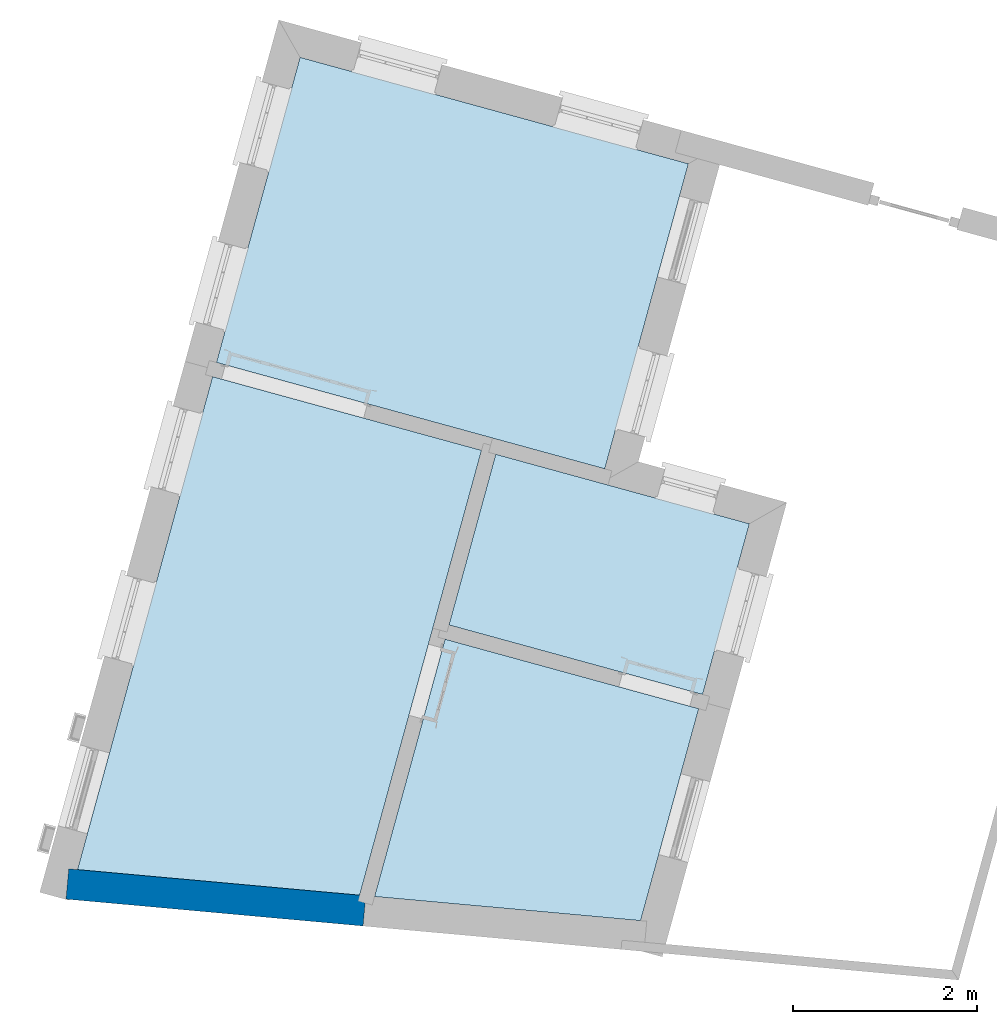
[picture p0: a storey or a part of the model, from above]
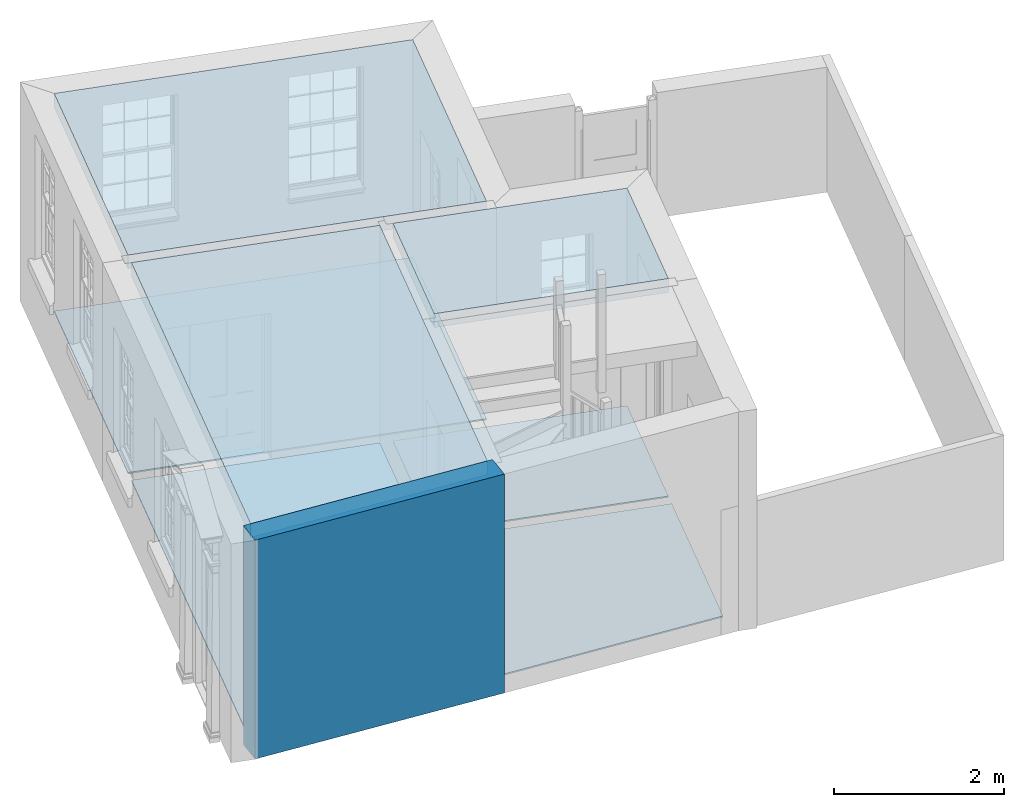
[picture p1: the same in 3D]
Properties of the parts of a building model (IFC4), part 1 of 4

# File
Description: ViewDefinition[DesignTransferView]
File name: model.ifc
Time: 2024-10-11T11:25:13+01:00
Author: bruno
Written by: IfcOpenShell 0.0.0
Made in: Bonsai 0.0.0

# IfcProject, Molior Project
Document: Building plot-0; plot-0 0; plot-0 1; plot-0 2; Building plot-0 NORTH; Building plot-0 SOUTH; Building plot-0 WEST; Building plot-0 EAST; Building plot-0 LOCATION; Building plot-1; plot-1 0; plot-1 1; plot-1 2; Building plot-1 NORTH; Building plot-1 SOUTH; Building plot-1 WEST; Building plot-1 EAST; Building plot-1 LOCATION; Building plot-2; plot-2 0; plot-2 1; plot-2 2; Building plot-2 NORTH; Building plot-2 SOUTH; Building plot-2 WEST; Building plot-2 EAST; Building plot-2 LOCATION; Building plot-3; plot-3 0; plot-3 1; plot-3 2; Building plot-3 NORTH; Building plot-3 SOUTH; Building plot-3 WEST; Building plot-3 EAST; Building plot-3 LOCATION; Building plot-4; plot-4 0; plot-4 1; plot-4 2; Building plot-4 NORTH; Building plot-4 SOUTH; Building plot-4 WEST; Building plot-4 EAST; Building plot-4 LOCATION; Building plot-5; plot-5 0; plot-5 1; plot-5 2; Building plot-5 NORTH; Building plot-5 SOUTH; Building plot-5 WEST; Building plot-5 EAST; Building plot-5 LOCATION; Building plot-6; plot-6 0; plot-6 1; plot-6 2; Building plot-6 NORTH; Building plot-6 SOUTH; Building plot-6 WEST; Building plot-6 EAST; Building plot-6 LOCATION; Building plot-7; plot-7 0; plot-7 1; plot-7 2; Building plot-7 NORTH; Building plot-7 SOUTH; Building plot-7 WEST; Building plot-7 EAST; Building plot-7 LOCATION; Building plot-8; plot-8 0; plot-8 1; plot-8 2; Building plot-8 NORTH; Building plot-8 SOUTH; Building plot-8 WEST; Building plot-8 EAST; Building plot-8 LOCATION; Building plot-9; plot-9 0; plot-9 1; Building plot-9 NORTH; Building plot-9 SOUTH; Building plot-9 WEST; Building plot-9 EAST; Building plot-9 LOCATION; Building plot-10; plot-10 0; plot-10 1; plot-10 2; plot-10 3; Building plot-10 NORTH; Building plot-10 SOUTH; Building plot-10 WEST; Building plot-10 EAST; Building plot-10 LOCATION; Building plot-11; plot-11 0; plot-11 1; plot-11 2; Building plot-11 NORTH; Building plot-11 SOUTH; Building plot-11 WEST; Building plot-11 EAST; Building plot-11 LOCATION; Building plot-12; plot-12 0; plot-12 1; plot-12 2; Building plot-12 NORTH; Building plot-12 SOUTH; Building plot-12 WEST; Building plot-12 EAST; Building plot-12 LOCATION; Building plot-13; plot-13 0; plot-13 1; plot-13 2; Building plot-13 NORTH; Building plot-13 SOUTH; Building plot-13 WEST; Building plot-13 EAST; Building plot-13 LOCATION; Building plot-14; plot-14 0; plot-14 1; plot-14 2; plot-14 3; Building plot-14 NORTH; Building plot-14 SOUTH; Building plot-14 WEST; Building plot-14 EAST; Building plot-14 LOCATION; Building plot-15; plot-15 0; plot-15 1; plot-15 2; Building plot-15 NORTH; Building plot-15 SOUTH; Building plot-15 WEST; Building plot-15 EAST; Building plot-15 LOCATION; Building plot-16; plot-16 0; plot-16 1; plot-16 2; plot-16 3; Building plot-16 NORTH; Building plot-16 SOUTH; Building plot-16 WEST; Building plot-16 EAST; Building plot-16 LOCATION; Building plot-17; plot-17 0; plot-17 1; plot-17 2; Building plot-17 NORTH; Building plot-17 SOUTH; Building plot-17 WEST; Building plot-17 EAST; Building plot-17 LOCATION; Building plot-18; plot-18 0; plot-18 1; plot-18 2; plot-18 3; Building plot-18 NORTH; Building plot-18 SOUTH; Building plot-18 WEST; Building plot-18 EAST; Building plot-18 LOCATION; Building plot-19; plot-19 0; plot-19 1; Building plot-19 NORTH; Building plot-19 SOUTH; Building plot-19 WEST; Building plot-19 EAST; Building plot-19 LOCATION; Building plot-20; plot-20 0; plot-20 1; plot-20 2; Building plot-20 NORTH; Building plot-20 SOUTH; Building plot-20 WEST; Building plot-20 EAST; Building plot-20 LOCATION; Building plot-21; plot-21 0; plot-21 1; plot-21 2; Building plot-21 NORTH; Building plot-21 SOUTH; Building plot-21 WEST; Building plot-21 EAST; Building plot-21 LOCATION; Building plot-22; plot-22 0; plot-22 1; plot-22 2; Building plot-22 NORTH; Building plot-22 SOUTH; Building plot-22 WEST; Building plot-22 EAST; Building plot-22 LOCATION; Building plot-23; plot-23 0; plot-23 1; plot-23 2; Building plot-23 NORTH; Building plot-23 SOUTH; Building plot-23 WEST; Building plot-23 EAST; Building plot-23 LOCATION; Building plot-24; plot-24 0; plot-24 1; plot-24 2; Building plot-24 NORTH; Building plot-24 SOUTH; Building plot-24 WEST; Building plot-24 EAST; Building plot-24 LOCATION; Building plot-25; plot-25 0; plot-25 1; Building plot-25 NORTH; Building plot-25 SOUTH; Building plot-25 WEST; Building plot-25 EAST; Building plot-25 LOCATION; Building plot-26; plot-26 0; plot-26 1; plot-26 2; Building plot-26 NORTH; Building plot-26 SOUTH; Building plot-26 WEST; Building plot-26 EAST; Building plot-26 LOCATION; Building plot-27; plot-27 0; plot-27 1; plot-27 2; Building plot-27 NORTH; Building plot-27 SOUTH; Building plot-27 WEST; Building plot-27 EAST; Building plot-27 LOCATION; Building plot-28; plot-28 0; plot-28 1; plot-28 2; Building plot-28 NORTH; Building plot-28 SOUTH; Building plot-28 WEST; Building plot-28 EAST; Building plot-28 LOCATION; Building plot-29; plot-29 0; plot-29 1; plot-29 2; Building plot-29 NORTH; Building plot-29 SOUTH; Building plot-29 WEST; Building plot-29 EAST; Building plot-29 LOCATION; Building plot-30; plot-30 0; plot-30 1; plot-30 2; Building plot-30 NORTH; Building plot-30 SOUTH; Building plot-30 WEST; Building plot-30 EAST; Building plot-30 LOCATION; Building plot-31; plot-31 0; plot-31 1; plot-31 2; Building plot-31 NORTH; Building plot-31 SOUTH; Building plot-31 WEST; Building plot-31 EAST; Building plot-31 LOCATION

# IfcSite (33)
Name
Site plot-0
Site plot-1
Site plot-10
Site plot-11
Site plot-12
Site plot-13
Site plot-14
Site plot-15
Site plot-16
Site plot-17
Site plot-18
Site plot-19
Site plot-2
Site plot-20
Site plot-21
Site plot-22
Site plot-23
Site plot-24
Site plot-25
Site plot-26
Site plot-27
Site plot-28
Site plot-29
Site plot-3
Site plot-30
Site plot-31
Site plot-4
Site plot-5
Site plot-6
Site plot-7
Site plot-8
Site plot-9
Tamar | RefLatitude: 50, 417; RefLongitude: -4, 25

# IfcBuildingStorey (97)
Name | In | Elevation (m)
plot-0 0 | Building plot-0 | 26
plot-0 1 | Building plot-0 | 29.3
plot-0 2 | Building plot-0 | 32.3
plot-1 0 | Building plot-1 | 26
plot-1 1 | Building plot-1 | 29.6
plot-1 2 | Building plot-1 | 33.2
plot-10 0 | Building plot-10 | 26.8
plot-10 1 | Building plot-10 | 30.1
plot-10 2 | Building plot-10 | 32.8
plot-10 3 | Building plot-10 | 35.5
plot-11 0 | Building plot-11 | 26.8
plot-11 1 | Building plot-11 | 30.1
plot-11 2 | Building plot-11 | 33.4
plot-12 0 | Building plot-12 | 26
plot-12 1 | Building plot-12 | 29.6
plot-12 2 | Building plot-12 | 32.3
plot-13 0 | Building plot-13 | 26
plot-13 1 | Building plot-13 | 29
plot-13 2 | Building plot-13 | 31.85
plot-14 0 | Building plot-14 | 26.8
plot-14 1 | Building plot-14 | 30.4
plot-14 2 | Building plot-14 | 33.55
plot-14 3 | Building plot-14 | 36.25
plot-15 0 | Building plot-15 | 26.8
plot-15 1 | Building plot-15 | 29.95
plot-15 2 | Building plot-15 | 32.95
plot-16 0 | Building plot-16 | 26
plot-16 1 | Building plot-16 | 29.45
plot-16 2 | Building plot-16 | 32.15
plot-16 3 | Building plot-16 | 34.85
plot-17 0 | Building plot-17 | 26.8
plot-17 1 | Building plot-17 | 30.4
plot-17 2 | Building plot-17 | 34
plot-18 0 | Building plot-18 | 26
plot-18 1 | Building plot-18 | 29.6
plot-18 2 | Building plot-18 | 32.3
plot-18 3 | Building plot-18 | 35.3
plot-19 0 | Building plot-19 | 26.8
plot-19 1 | Building plot-19 | 30.4
plot-2 0 | Building plot-2 | 26
plot-2 1 | Building plot-2 | 28.7
plot-2 2 | Building plot-2 | 31.55
plot-20 0 | Building plot-20 | 26
plot-20 1 | Building plot-20 | 29.15
plot-20 2 | Building plot-20 | 31.85
plot-21 0 | Building plot-21 | 26
plot-21 1 | Building plot-21 | 29.6
plot-21 2 | Building plot-21 | 32.3
plot-22 0 | Building plot-22 | 24.5
plot-22 1 | Building plot-22 | 27.8
plot-22 2 | Building plot-22 | 30.5
plot-23 0 | Building plot-23 | 26
plot-23 1 | Building plot-23 | 29.6
plot-23 2 | Building plot-23 | 33.2
plot-24 0 | Building plot-24 | 26
plot-24 1 | Building plot-24 | 29.3
plot-24 2 | Building plot-24 | 32
plot-25 0 | Building plot-25 | 26
plot-25 1 | Building plot-25 | 29.45
plot-26 0 | Building plot-26 | 26
plot-26 1 | Building plot-26 | 29.15
plot-26 2 | Building plot-26 | 32.75
plot-27 0 | Building plot-27 | 26
plot-27 1 | Building plot-27 | 29.3
plot-27 2 | Building plot-27 | 32
plot-28 0 | Building plot-28 | 24
plot-28 1 | Building plot-28 | 27.15
plot-28 2 | Building plot-28 | 29.85
plot-29 0 | Building plot-29 | 25
plot-29 1 | Building plot-29 | 27.85
plot-29 2 | Building plot-29 | 30.55
plot-3 0 | Building plot-3 | 24.5
plot-3 1 | Building plot-3 | 27.8
plot-3 2 | Building plot-3 | 30.5
plot-30 0 | Building plot-30 | 25
plot-30 1 | Building plot-30 | 28.3
plot-30 2 | Building plot-30 | 31
plot-31 0 | Building plot-31 | 25.5
plot-31 1 | Building plot-31 | 28.65
plot-31 2 | Building plot-31 | 31.35
plot-4 0 | Building plot-4 | 24.5
plot-4 1 | Building plot-4 | 27.8
plot-4 2 | Building plot-4 | 31.4
plot-5 0 | Building plot-5 | 24
plot-5 1 | Building plot-5 | 26.85
plot-5 2 | Building plot-5 | 30.15
plot-6 0 | Building plot-6 | 24.5
plot-6 1 | Building plot-6 | 28.1
plot-6 2 | Building plot-6 | 31.7
plot-7 0 | Building plot-7 | 26
plot-7 1 | Building plot-7 | 29.15
plot-7 2 | Building plot-7 | 31.85
plot-8 0 | Building plot-8 | 26
plot-8 1 | Building plot-8 | 28.85
plot-8 2 | Building plot-8 | 31.55
plot-9 0 | Building plot-9 | 26.8
plot-9 1 | Building plot-9 | 30.1

# IfcSpace (375)
Name | In | LongName | PredefinedType | NetFloorArea (m2) | Height (m) | NetVolume (m3)
Stair | plot-0 0 | Stair 0 lll | INTERNAL | 5.96703 | 3.08 | 18.3784
Circulation | plot-0 0 | Circulation 0 lrll | INTERNAL | 3.54437 | 3.08 | 10.9167
Bedroom | plot-0 0 | Bedroom 0 llr | INTERNAL | 8.87304 | 3.08 | 27.329
Bedroom | plot-0 0 | Bedroom 0 lrr | INTERNAL | 11.3388 | 3.08 | 34.9236
Toilet | plot-0 0 | Toilet 0 lrlr | INTERNAL | 2.95732 | 3.08 | 9.10855
Outside | plot-0 0 | Outside 0 r | EXTERNAL | 21.0555 | 3.08 | 64.8511
Stair | plot-0 1 | Stair 1 lll | INTERNAL | 5.96703 | 2.78 | 16.5883
Living | plot-0 1 | Living 1 lr | INTERNAL | 18.7241 | 2.78 | 52.0531
Kitchen | plot-0 1 | Kitchen 1 llr | INTERNAL | 8.87304 | 2.78 | 24.667
Bedroom | plot-0 2 | Bedroom 2 llr | INTERNAL | 8.87304 | 2.48 | 22.0051
Outside | plot-0 2 | Outside 2 lr | EXTERNAL | 18.7241 | 2.48 | 46.4359
Stair | plot-0 2 | Stair 2 lll | INTERNAL | 5.96703 | 2.48 | 14.7982
Circulation | plot-1 0 | Circulation 0 lrll | INTERNAL | 5.14544 | 3.38 | 17.3916
Bedroom | plot-1 0 | Bedroom 0 lrr | INTERNAL | 15.0023 | 3.38 | 50.7076
Outside | plot-1 0 | Outside 0 lrlr | EXTERNAL | 5.23166 | 3.38 | 17.683
Stair | plot-1 0 | Stair 0 lll | INTERNAL | 7.57512 | 3.38 | 25.6039
Toilet | plot-1 0 | Toilet 0 llr | INTERNAL | 10.7025 | 3.38 | 36.1743
Outside | plot-1 0 | Outside 0 r | EXTERNAL | 22.0098 | 3.38 | 74.3931
Stair | plot-1 1 | Stair 1 lll | INTERNAL | 7.57512 | 3.38 | 25.6039
Kitchen | plot-1 1 | Kitchen 1 llr | INTERNAL | 10.7025 | 3.38 | 36.1743
Living | plot-1 1 | Living 1 lr | INTERNAL | 26.5038 | 3.38 | 89.5828
Stair | plot-1 2 | Stair 2 lll | INTERNAL | 7.57512 | 2.48 | 18.7863
Bedroom | plot-1 2 | Bedroom 2 llr | INTERNAL | 10.7025 | 2.48 | 26.5421
Outside | plot-1 2 | Outside 2 lr | EXTERNAL | 26.5038 | 2.48 | 65.7294
Stair | plot-10 0 | Stair 0 rl | INTERNAL | 5.94535 | 3.08 | 18.3117
Kitchen | plot-10 0 | Kitchen 0 rr | INTERNAL | 8.41021 | 3.08 | 25.9034
Living | plot-10 0 | Living 0 ll | INTERNAL | 17.3902 | 3.08 | 53.5619
Outside | plot-10 0 | Outside 0 lr | EXTERNAL | 15.8102 | 3.08 | 48.6955
Stair | plot-10 1 | Stair 1 rl | INTERNAL | 5.94535 | 2.48 | 14.7445
Toilet | plot-10 1 | Toilet 1 rr | INTERNAL | 8.41021 | 2.48 | 20.8573
Outside | plot-10 1 | Outside 1 ll | EXTERNAL | 17.3902 | 2.48 | 43.1278
Stair | plot-10 2 | Stair 2 rl | INTERNAL | 5.94535 | 2.48 | 14.7445
Bedroom | plot-10 2 | Bedroom 2 rr | INTERNAL | 8.41021 | 2.48 | 20.8573
Stair | plot-10 3 | Stair 3 rl | INTERNAL | 5.94535 | 2.48 | 14.7445
Bedroom | plot-10 3 | Bedroom 3 rr | INTERNAL | 8.41021 | 2.48 | 20.8573
Outside | plot-11 0 | Outside 0 rll | EXTERNAL | 12.8188 | 3.08 | 39.482
Bedroom | plot-11 0 | Bedroom 0 rlr | INTERNAL | 12.1352 | 3.08 | 37.3764
Circulation | plot-11 0 | Circulation 0 lll | INTERNAL | 6.95787 | 3.08 | 21.4302
Toilet | plot-11 0 | Toilet 0 lrl | INTERNAL | 10.7166 | 3.08 | 33.0072
Outside | plot-11 0 | Outside 0 llr | EXTERNAL | 10.2707 | 3.08 | 31.6338
Outside | plot-11 0 | Outside 0 lrr | EXTERNAL | 9.70752 | 3.08 | 29.8992
Stair | plot-11 0 | Stair 0 rr | INTERNAL | 10.1278 | 3.08 | 31.1937
Bedroom | plot-11 1 | Bedroom 1 rlr | INTERNAL | 12.1352 | 3.08 | 37.3764
Living | plot-11 1 | Living 1 ll | INTERNAL | 17.7529 | 3.08 | 54.6789
Kitchen | plot-11 1 | Kitchen 1 lrl | INTERNAL | 10.7166 | 3.08 | 33.0072
Stair | plot-11 1 | Stair 1 rr | INTERNAL | 10.1278 | 3.08 | 31.1937
Stair | plot-11 2 | Stair 2 rr | INTERNAL | 10.1278 | 2.48 | 25.117
Bedroom | plot-11 2 | Bedroom 2 rlr | INTERNAL | 12.1352 | 2.48 | 30.0953
Outside | plot-11 2 | Outside 2 ll | EXTERNAL | 17.7529 | 2.48 | 44.0271
Outside | plot-11 2 | Outside 2 lrl | EXTERNAL | 10.7166 | 2.48 | 26.5772
Stair | plot-12 0 | Stair 0 rll | INTERNAL | 8.0224 | 3.38 | 27.1157
Kitchen | plot-12 0 | Kitchen 0 rlr | INTERNAL | 9.74623 | 3.38 | 32.9423
Outside | plot-12 0 | Outside 0 l | EXTERNAL | 27.2026 | 3.38 | 91.9449
Living | plot-12 0 | Living 0 rr | INTERNAL | 19.1112 | 3.38 | 64.5959
Stair | plot-12 1 | Stair 1 rll | INTERNAL | 8.0224 | 2.48 | 19.8956
Bedroom | plot-12 1 | Bedroom 1 rr | INTERNAL | 19.1112 | 2.48 | 47.3958
Toilet | plot-12 1 | Toilet 1 rlr | INTERNAL | 9.74623 | 2.48 | 24.1706
Stair | plot-12 2 | Stair 2 rll | INTERNAL | 8.0224 | 2.48 | 19.8956
Outside | plot-12 2 | Outside 2 rr | EXTERNAL | 19.1112 | 2.48 | 47.3958
Bedroom | plot-12 2 | Bedroom 2 rlr | INTERNAL | 9.74623 | 2.48 | 24.1706
Outside | plot-13 0 | Outside 0 ll | EXTERNAL | 26.1804 | 2.78 | 72.7814
Stair | plot-13 0 | Stair 0 lrl | INTERNAL | 6.69457 | 2.78 | 18.6109
Kitchen | plot-13 0 | Kitchen 0 lrr | INTERNAL | 8.50893 | 2.78 | 23.6548
Living | plot-13 0 | Living 0 r | INTERNAL | 25.9567 | 2.78 | 72.1597
Bedroom | plot-13 1 | Bedroom 1 rl | INTERNAL | 13.2145 | 2.63 | 34.7543
Outside | plot-13 1 | Outside 1 rr | EXTERNAL | 12.1835 | 2.63 | 32.0427
Stair | plot-13 1 | Stair 1 lrl | INTERNAL | 6.69457 | 2.63 | 17.6067
Toilet | plot-13 1 | Toilet 1 lrr | INTERNAL | 8.50893 | 2.63 | 22.3785
Stair | plot-13 2 | Stair 2 lrl | INTERNAL | 6.69457 | 2.48 | 16.6025
Bedroom | plot-13 2 | Bedroom 2 rl | INTERNAL | 13.2145 | 2.48 | 32.7721
Bedroom | plot-13 2 | Bedroom 2 lrr | INTERNAL | 8.50893 | 2.48 | 21.1022
Living | plot-14 0 | Living 0 rrl | INTERNAL | 10.6065 | 3.38 | 35.8499
Kitchen | plot-14 0 | Kitchen 0 rrr | INTERNAL | 7.65437 | 3.38 | 25.8718
Outside | plot-14 0 | Outside 0 l | EXTERNAL | 25.6621 | 3.38 | 86.7379
Stair | plot-14 0 | Stair 0 rll | INTERNAL | 6.82289 | 3.38 | 23.0614
Outside | plot-14 0 | Outside 0 rlr | EXTERNAL | 10.4119 | 3.38 | 35.1921
Stair | plot-14 1 | Stair 1 rll | INTERNAL | 6.82289 | 2.93 | 19.9911
Bedroom | plot-14 1 | Bedroom 1 rr | INTERNAL | 18.8516 | 2.93 | 55.2351
Toilet | plot-14 1 | Toilet 1 rlr | INTERNAL | 10.4119 | 2.93 | 30.5067
Stair | plot-14 2 | Stair 2 rll | INTERNAL | 6.82289 | 2.48 | 16.9208
Bedroom | plot-14 2 | Bedroom 2 rr | INTERNAL | 18.8516 | 2.48 | 46.7519
Outside | plot-14 2 | Outside 2 rlr | EXTERNAL | 10.4119 | 2.48 | 25.8214
Stair | plot-14 3 | Stair 3 rll | INTERNAL | 6.82289 | 2.48 | 16.9208
Outside | plot-14 3 | Outside 3 rr | EXTERNAL | 18.8516 | 2.48 | 46.7519
Stair | plot-15 0 | Stair 0 rl | INTERNAL | 11.7611 | 2.93 | 34.4601
Outside | plot-15 0 | Outside 0 rr | EXTERNAL | 10.9395 | 2.93 | 32.0527
Kitchen | plot-15 0 | Kitchen 0 lrl | INTERNAL | 14.1652 | 2.93 | 41.5041
Sahn | plot-15 0 | Sahn 0 lrr | EXTERNAL | 7.60435 | 2.93 | 22.2807
Living | plot-15 0 | Living 0 lll | INTERNAL | 22.7517 | 2.93 | 66.6625
Sahn | plot-15 0 | Sahn 0 llr | EXTERNAL | 12.5578 | 2.93 | 36.7943
Bedroom | plot-15 1 | Bedroom 1 llll | INTERNAL | 8.3033 | 2.78 | 23.0832
Stair | plot-15 1 | Stair 1 rl | INTERNAL | 11.7611 | 2.78 | 32.6959
Bedroom | plot-15 1 | Bedroom 1 lllr | INTERNAL | 13.7534 | 2.78 | 38.2343
Outside | plot-15 1 | Outside 1 lrl | EXTERNAL | 14.1652 | 2.78 | 39.3793
Toilet | plot-15 2 | Toilet 2 llll | INTERNAL | 8.3033 | 2.48 | 20.5922
Stair | plot-15 2 | Stair 2 rl | INTERNAL | 11.7611 | 2.48 | 29.1676
Bedroom | plot-15 2 | Bedroom 2 lllr | INTERNAL | 13.7534 | 2.48 | 34.1083
Stair | plot-16 0 | Stair 0 rrl | INTERNAL | 7.2059 | 3.23 | 23.275
Kitchen | plot-16 0 | Kitchen 0 rrr | INTERNAL | 11.198 | 3.23 | 36.1696
Outside | plot-16 0 | Outside 0 l | EXTERNAL | 34.9474 | 3.23 | 112.88
Living | plot-16 0 | Living 0 rl | INTERNAL | 27.8434 | 3.23 | 89.9341
Stair | plot-16 1 | Stair 1 rrl | INTERNAL | 7.2059 | 2.48 | 17.8706
Bedroom | plot-16 1 | Bedroom 1 rrr | INTERNAL | 11.198 | 2.48 | 27.7711
Bedroom | plot-16 1 | Bedroom 1 rlr | INTERNAL | 14.487 | 2.48 | 35.9278
Outside | plot-16 1 | Outside 1 rll | EXTERNAL | 12.5021 | 2.48 | 31.0053
Bedroom | plot-16 2 | Bedroom 2 rlr | INTERNAL | 14.487 | 2.48 | 35.9278
Stair | plot-16 2 | Stair 2 rrl | INTERNAL | 7.2059 | 2.48 | 17.8706
Toilet | plot-16 2 | Toilet 2 rrr | INTERNAL | 11.198 | 2.48 | 27.7711
Outside | plot-16 3 | Outside 3 rlr | EXTERNAL | 14.487 | 2.48 | 35.9278
Stair | plot-16 3 | Stair 3 rrl | INTERNAL | 7.2059 | 2.48 | 17.8706
Outside | plot-16 3 | Outside 3 rrr | EXTERNAL | 11.198 | 2.48 | 27.7711
Living | plot-17 0 | Living 0 ll | INTERNAL | 18.1319 | 3.38 | 61.2857
Stair | plot-17 0 | Stair 0 lrl | INTERNAL | 6.08818 | 3.38 | 20.578
Kitchen | plot-17 0 | Kitchen 0 lrr | INTERNAL | 9.33892 | 3.38 | 31.5656
Outside | plot-17 0 | Outside 0 r | EXTERNAL | 15.3234 | 3.38 | 51.7931
Bedroom | plot-17 1 | Bedroom 1 ll | INTERNAL | 18.1319 | 3.38 | 61.2857
Stair | plot-17 1 | Stair 1 lrl | INTERNAL | 6.08818 | 3.38 | 20.578
Toilet | plot-17 1 | Toilet 1 lrr | INTERNAL | 9.33892 | 3.38 | 31.5656
Stair | plot-17 2 | Stair 2 lrl | INTERNAL | 6.08818 | 2.48 | 15.0987
Outside | plot-17 2 | Outside 2 lrr | EXTERNAL | 9.33892 | 2.48 | 23.1605
Outside | plot-17 2 | Outside 2 ll | EXTERNAL | 18.1319 | 2.48 | 44.967
Outside | plot-18 0 | Outside 0 l | EXTERNAL | 44.5235 | 3.38 | 150.489
Stair | plot-18 0 | Stair 0 rlr | INTERNAL | 8.11732 | 3.38 | 27.4366
Living | plot-18 0 | Living 0 rr | INTERNAL | 18.8792 | 3.38 | 63.8116
Kitchen | plot-18 0 | Kitchen 0 rll | INTERNAL | 10.1523 | 3.38 | 34.3148
Stair | plot-18 1 | Stair 1 rlr | INTERNAL | 8.11732 | 2.48 | 20.131
Bedroom | plot-18 1 | Bedroom 1 rr | INTERNAL | 18.8792 | 2.48 | 46.8204
Toilet | plot-18 1 | Toilet 1 rll | INTERNAL | 10.1523 | 2.48 | 25.1777
Bedroom | plot-18 2 | Bedroom 2 rll | INTERNAL | 10.1523 | 2.78 | 28.2234
Stair | plot-18 2 | Stair 2 rlr | INTERNAL | 8.11732 | 2.78 | 22.5662
Bedroom | plot-18 2 | Bedroom 2 rr | INTERNAL | 18.8792 | 2.78 | 52.4841
Outside | plot-18 3 | Outside 3 rll | EXTERNAL | 10.1523 | 2.48 | 25.1777
Outside | plot-18 3 | Outside 3 rr | EXTERNAL | 18.8792 | 2.48 | 46.8204
Stair | plot-18 3 | Stair 3 rlr | INTERNAL | 8.11732 | 2.48 | 20.131
Stair | plot-19 0 | Stair 0 ll | INTERNAL | 8.76168 | 3.38 | 29.6145
Outside | plot-19 0 | Outside 0 rll | EXTERNAL | 8.85172 | 3.38 | 29.9188
Toilet | plot-19 0 | Toilet 0 rlr | INTERNAL | 7.88164 | 3.38 | 26.6399
Living | plot-19 0 | Living 0 lr | INTERNAL | 17.1169 | 3.38 | 57.8552
Kitchen | plot-19 0 | Kitchen 0 rr | INTERNAL | 13.4656 | 3.38 | 45.5137
Outside | plot-19 1 | Outside 1 rr | EXTERNAL | 13.4656 | 2.48 | 33.3946
Stair | plot-19 1 | Stair 1 ll | INTERNAL | 8.76168 | 2.48 | 21.729
Bedroom | plot-19 1 | Bedroom 1 rlr | INTERNAL | 7.88164 | 2.48 | 19.5465
Bedroom | plot-19 1 | Bedroom 1 lr | INTERNAL | 17.1169 | 2.48 | 42.45
Kitchen | plot-2 0 | Kitchen 0 lrl | INTERNAL | 8.22136 | 2.48 | 20.389
Stair | plot-2 0 | Stair 0 lrr | INTERNAL | 5.70095 | 2.48 | 14.1384
Living | plot-2 0 | Living 0 ll | INTERNAL | 16.5054 | 2.48 | 40.9333
Sahn | plot-2 0 | Sahn 0 r | EXTERNAL | 20.1734 | 2.48 | 50.03
Bedroom | plot-2 1 | Bedroom 1 ll | INTERNAL | 16.5054 | 2.63 | 43.4091
Stair | plot-2 1 | Stair 1 lrr | INTERNAL | 5.70095 | 2.63 | 14.9935
Bedroom | plot-2 1 | Bedroom 1 lrl | INTERNAL | 8.22136 | 2.63 | 21.6222
Outside | plot-2 2 | Outside 2 ll | EXTERNAL | 16.5054 | 2.48 | 40.9333
Stair | plot-2 2 | Stair 2 lrr | INTERNAL | 5.70095 | 2.48 | 14.1384
Toilet | plot-2 2 | Toilet 2 lrl | INTERNAL | 8.22136 | 2.48 | 20.389
Kitchen | plot-20 0 | Kitchen 0 lll | INTERNAL | 9.07966 | 2.93 | 26.6034
Outside | plot-20 0 | Outside 0 lr | EXTERNAL | 14.7928 | 2.93 | 43.343
Outside | plot-20 0 | Outside 0 llr | EXTERNAL | 9.07966 | 2.93 | 26.6034
Stair | plot-20 0 | Stair 0 rll | INTERNAL | 6.41231 | 2.93 | 18.7881
Living | plot-20 0 | Living 0 rr | INTERNAL | 15.6897 | 2.93 | 45.9709
Toilet | plot-20 0 | Toilet 0 rlr | INTERNAL | 9.70942 | 2.93 | 28.4486
Stair | plot-20 1 | Stair 1 rll | INTERNAL | 6.41231 | 2.48 | 15.9025
Bedroom | plot-20 1 | Bedroom 1 rlr | INTERNAL | 9.70942 | 2.48 | 24.0794
Bedroom | plot-20 1 | Bedroom 1 rr | INTERNAL | 15.6897 | 2.48 | 38.9105
Outside | plot-20 1 | Outside 1 lll | EXTERNAL | 9.07966 | 2.48 | 22.5176
Stair | plot-20 2 | Stair 2 rll | INTERNAL | 6.41231 | 2.48 | 15.9025
Bedroom | plot-20 2 | Bedroom 2 rr | INTERNAL | 15.6897 | 2.48 | 38.9105
Outside | plot-20 2 | Outside 2 rlr | EXTERNAL | 9.70942 | 2.48 | 24.0794
Bedroom | plot-21 0 | Bedroom 0 llr | INTERNAL | 11.1374 | 3.38 | 37.6446
Outside | plot-21 0 | Outside 0 r | EXTERNAL | 24.025 | 3.38 | 81.2045
Toilet | plot-21 0 | Toilet 0 lrll | INTERNAL | 7.71286 | 3.38 | 26.0695
Bedroom | plot-21 0 | Bedroom 0 lrlr | INTERNAL | 5.62224 | 3.38 | 19.0032
Circulation | plot-21 0 | Circulation 0 lrr | INTERNAL | 8.27706 | 3.38 | 27.9765
Stair | plot-21 0 | Stair 0 lll | INTERNAL | 7.19696 | 3.38 | 24.3257
Kitchen | plot-21 1 | Kitchen 1 llr | INTERNAL | 11.1374 | 2.48 | 27.6209
Living | plot-21 1 | Living 1 lr | INTERNAL | 22.8295 | 2.48 | 56.6171
Stair | plot-21 1 | Stair 1 lll | INTERNAL | 7.19696 | 2.48 | 17.8485
Bedroom | plot-21 2 | Bedroom 2 llr | INTERNAL | 11.1374 | 2.48 | 27.6209
Outside | plot-21 2 | Outside 2 lr | EXTERNAL | 22.8295 | 2.48 | 56.6171
Stair | plot-21 2 | Stair 2 lll | INTERNAL | 7.19696 | 2.48 | 17.8485
Stair | plot-22 0 | Stair 0 lll | INTERNAL | 5.97909 | 3.08 | 18.4156
Kitchen | plot-22 0 | Kitchen 0 llr | INTERNAL | 7.14744 | 3.08 | 22.0141
Living | plot-22 0 | Living 0 lr | INTERNAL | 17.3171 | 3.08 | 53.3366
Outside | plot-22 0 | Outside 0 r | EXTERNAL | 22.0597 | 3.08 | 67.9439
Stair | plot-22 1 | Stair 1 lll | INTERNAL | 5.97909 | 2.48 | 14.8281
Toilet | plot-22 1 | Toilet 1 llr | INTERNAL | 7.14744 | 2.48 | 17.7256
Bedroom | plot-22 1 | Bedroom 1 lr | INTERNAL | 17.3171 | 2.48 | 42.9463
Stair | plot-22 2 | Stair 2 lll | INTERNAL | 5.97909 | 2.48 | 14.8281
Outside | plot-22 2 | Outside 2 lr | EXTERNAL | 17.3171 | 2.48 | 42.9463
Bedroom | plot-22 2 | Bedroom 2 llr | INTERNAL | 7.14744 | 2.48 | 17.7256
Outside | plot-23 0 | Outside 0 ll | EXTERNAL | 11.583 | 3.38 | 39.1506
Living | plot-23 0 | Living 0 lr | INTERNAL | 16.5872 | 3.38 | 56.0648
Outside | plot-23 0 | Outside 0 rll | EXTERNAL | 14.298 | 3.38 | 48.3272
Stair | plot-23 0 | Stair 0 rrl | INTERNAL | 7.45306 | 3.38 | 25.1914
Outside | plot-23 0 | Outside 0 rrr | EXTERNAL | 10.6533 | 3.38 | 36.0083
Bedroom | plot-23 0 | Bedroom 0 rlr | INTERNAL | 9.02983 | 3.38 | 30.5208
Stair | plot-23 1 | Stair 1 rrl | INTERNAL | 7.45306 | 3.38 | 25.1914
Kitchen | plot-23 1 | Kitchen 1 rlr | INTERNAL | 9.02983 | 3.38 | 30.5208
Living | plot-23 1 | Living 1 lr | INTERNAL | 16.5872 | 3.38 | 56.0648
Stair | plot-23 2 | Stair 2 rrl | INTERNAL | 7.45306 | 2.63 | 19.6016
Toilet | plot-23 2 | Toilet 2 rlr | INTERNAL | 9.02983 | 2.63 | 23.7484
Bedroom | plot-23 2 | Bedroom 2 lr | INTERNAL | 16.5872 | 2.63 | 43.6244
Outside | plot-24 0 | Outside 0 rll | EXTERNAL | 6.08469 | 3.08 | 18.7408
Bedroom | plot-24 0 | Bedroom 0 rlr | INTERNAL | 8.2591 | 3.08 | 25.438
Sahn | plot-24 0 | Sahn 0 rr | EXTERNAL | 18.4006 | 3.08 | 56.6738
Stair | plot-24 0 | Stair 0 ll | INTERNAL | 7.57451 | 3.08 | 23.3295
Sahn | plot-24 0 | Sahn 0 lr | EXTERNAL | 6.59171 | 3.08 | 20.3025
Stair | plot-24 1 | Stair 1 ll | INTERNAL | 7.57451 | 2.48 | 18.7848
Living | plot-24 1 | Living 1 rl | INTERNAL | 14.7868 | 2.48 | 36.6714
Kitchen | plot-24 1 | Kitchen 1 lr | INTERNAL | 6.59171 | 2.48 | 16.3475
Stair | plot-24 2 | Stair 2 ll | INTERNAL | 7.57451 | 3.08 | 23.3295
Toilet | plot-24 2 | Toilet 2 lr | INTERNAL | 6.59171 | 3.08 | 20.3025
Bedroom | plot-24 2 | Bedroom 2 rl | INTERNAL | 14.7868 | 3.08 | 45.5435
Living | plot-25 0 | Living 0 lll | INTERNAL | 9.01577 | 3.23 | 29.1209
Kitchen | plot-25 0 | Kitchen 0 llr | INTERNAL | 6.65477 | 3.23 | 21.4949
Outside | plot-25 0 | Outside 0 rl | EXTERNAL | 6.10543 | 3.23 | 19.7205
Stair | plot-25 0 | Stair 0 rr | INTERNAL | 8.10948 | 3.23 | 26.1936
Outside | plot-25 0 | Outside 0 lr | EXTERNAL | 12.0182 | 3.23 | 38.8189
Bedroom | plot-25 1 | Bedroom 1 ll | INTERNAL | 16.1546 | 3.38 | 54.6024
Toilet | plot-25 1 | Toilet 1 rl | INTERNAL | 6.10543 | 3.38 | 20.6364
Stair | plot-25 1 | Stair 1 rr | INTERNAL | 8.10948 | 3.38 | 27.4101
Outside | plot-26 0 | Outside 0 ll | EXTERNAL | 13.4634 | 2.93 | 39.4478
Stair | plot-26 0 | Stair 0 lrl | INTERNAL | 6.06499 | 2.93 | 17.7704
Toilet | plot-26 0 | Toilet 0 lrr | INTERNAL | 9.30718 | 2.93 | 27.27
Outside | plot-26 0 | Outside 0 r | EXTERNAL | 20.8294 | 2.93 | 61.0303
Bedroom | plot-26 1 | Bedroom 1 ll | INTERNAL | 13.4634 | 3.38 | 45.5064
Stair | plot-26 1 | Stair 1 lrl | INTERNAL | 6.06499 | 3.38 | 20.4997
Bedroom | plot-26 1 | Bedroom 1 lrr | INTERNAL | 9.30718 | 3.38 | 31.4583
Kitchen | plot-26 2 | Kitchen 2 lll | INTERNAL | 7.35882 | 2.48 | 18.2499
Bedroom | plot-26 2 | Bedroom 2 llr | INTERNAL | 5.67529 | 2.48 | 14.0747
Living | plot-26 2 | Living 2 lrr | INTERNAL | 9.30718 | 2.48 | 23.0818
Stair | plot-26 2 | Stair 2 lrl | INTERNAL | 6.06499 | 2.48 | 15.0412
Living | plot-27 0 | Living 0 lll | INTERNAL | 10.7571 | 3.08 | 33.1318
Kitchen | plot-27 0 | Kitchen 0 lrl | INTERNAL | 7.6863 | 3.08 | 23.6738
Toilet | plot-27 0 | Toilet 0 lrr | INTERNAL | 6.9563 | 3.08 | 21.4254
Stair | plot-27 0 | Stair 0 llr | INTERNAL | 6.17774 | 3.08 | 19.0275
Outside | plot-27 0 | Outside 0 r | EXTERNAL | 17.1042 | 3.08 | 52.6809
Outside | plot-27 1 | Outside 1 lll | EXTERNAL | 10.7571 | 2.48 | 26.6776
Bedroom | plot-27 1 | Bedroom 1 lr | INTERNAL | 15.0789 | 2.48 | 37.3957
Stair | plot-27 1 | Stair 1 llr | INTERNAL | 6.17774 | 2.48 | 15.3208
Stair | plot-27 2 | Stair 2 llr | INTERNAL | 6.17774 | 2.48 | 15.3208
Bedroom | plot-27 2 | Bedroom 2 lr | INTERNAL | 15.0789 | 2.48 | 37.3957
Outside | plot-28 0 | Outside 0 ll | EXTERNAL | 16.0677 | 2.93 | 47.0785
Kitchen | plot-28 0 | Kitchen 0 lr | INTERNAL | 15.0025 | 2.93 | 43.9573
Stair | plot-28 0 | Stair 0 rrll | INTERNAL | 7.53615 | 2.93 | 22.0809
Toilet | plot-28 0 | Toilet 0 rrlr | INTERNAL | 5.48273 | 2.93 | 16.0644
Outside | plot-28 0 | Outside 0 rrr | EXTERNAL | 12.5433 | 2.93 | 36.7519
Living | plot-28 0 | Living 0 rl | INTERNAL | 15.9702 | 2.93 | 46.7928
Bedroom | plot-28 1 | Bedroom 1 rl | INTERNAL | 15.9702 | 2.48 | 39.6062
Stair | plot-28 1 | Stair 1 rrll | INTERNAL | 7.53615 | 2.48 | 18.6897
Circulation | plot-28 1 | Circulation 1 rrlr | INTERNAL | 5.48273 | 2.48 | 13.5972
Bedroom | plot-28 1 | Bedroom 1 lr | INTERNAL | 15.0025 | 2.48 | 37.2062
Bedroom | plot-28 2 | Bedroom 2 rl | INTERNAL | 15.9702 | 2.48 | 39.6062
Stair | plot-28 2 | Stair 2 rrll | INTERNAL | 7.53615 | 2.48 | 18.6897
Toilet | plot-28 2 | Toilet 2 rrlr | INTERNAL | 5.48273 | 2.48 | 13.5972
Outside | plot-28 2 | Outside 2 lr | EXTERNAL | 15.0025 | 2.48 | 37.2062
Outside | plot-29 0 | Outside 0 lll | EXTERNAL | 19.6404 | 2.63 | 51.6543
Kitchen | plot-29 0 | Kitchen 0 llr | INTERNAL | 9.86388 | 2.63 | 25.942
Stair | plot-29 0 | Stair 0 lrl | INTERNAL | 8.93355 | 2.63 | 23.4952
Outside | plot-29 0 | Outside 0 lrr | EXTERNAL | 8.60522 | 2.63 | 22.6317
Living | plot-29 0 | Living 0 rl | INTERNAL | 14.3189 | 2.63 | 37.6587
Outside | plot-29 0 | Outside 0 rr | EXTERNAL | 8.50913 | 2.63 | 22.379
Bedroom | plot-29 1 | Bedroom 1 llr | INTERNAL | 9.86388 | 2.48 | 24.4624
Bedroom | plot-29 1 | Bedroom 1 rl | INTERNAL | 14.3189 | 2.48 | 35.5109
Stair | plot-29 1 | Stair 1 lrl | INTERNAL | 8.93355 | 2.48 | 22.1552
Toilet | plot-29 1 | Toilet 1 lrr | INTERNAL | 8.60522 | 2.48 | 21.3409
Bedroom | plot-29 2 | Bedroom 2 llr | INTERNAL | 9.86388 | 2.48 | 24.4624
Stair | plot-29 2 | Stair 2 lrl | INTERNAL | 8.93355 | 2.48 | 22.1552
Bedroom | plot-29 2 | Bedroom 2 lrr | INTERNAL | 8.60522 | 2.48 | 21.3409
Outside | plot-29 2 | Outside 2 rl | EXTERNAL | 14.3189 | 2.48 | 35.5109
Sahn | plot-3 0 | Sahn 0 rl | EXTERNAL | 14.0888 | 3.08 | 43.3934
Bedroom | plot-3 0 | Bedroom 0 rr | INTERNAL | 17.138 | 3.08 | 52.785
Sahn | plot-3 0 | Sahn 0 ll | EXTERNAL | 6.51275 | 3.08 | 20.0593
Stair | plot-3 0 | Stair 0 lr | INTERNAL | 7.25922 | 3.08 | 22.3584
Toilet | plot-3 1 | Toilet 1 ll | INTERNAL | 6.51275 | 2.48 | 16.1516
Stair | plot-3 1 | Stair 1 lr | INTERNAL | 7.25922 | 2.48 | 18.0029
Living | plot-3 1 | Living 1 rrl | INTERNAL | 9.48783 | 2.48 | 23.5298
Kitchen | plot-3 1 | Kitchen 1 rrr | INTERNAL | 7.15739 | 2.48 | 17.7503
Sahn | plot-3 2 | Sahn 2 rrl | EXTERNAL | 9.48783 | 2.48 | 23.5298
Sahn | plot-3 2 | Sahn 2 rrr | EXTERNAL | 7.15739 | 2.48 | 17.7503
Bedroom | plot-3 2 | Bedroom 2 ll | INTERNAL | 6.51275 | 2.48 | 16.1516
Stair | plot-3 2 | Stair 2 lr | INTERNAL | 7.25922 | 2.48 | 18.0029
Sahn | plot-30 0 | Sahn 0 rrl | EXTERNAL | 7.11086 | 3.08 | 21.9015
Stair | plot-30 0 | Stair 0 rrr | INTERNAL | 7.81924 | 3.08 | 24.0833
Outside | plot-30 0 | Outside 0 ll | EXTERNAL | 19.7831 | 3.08 | 60.9318
Living | plot-30 0 | Living 0 rll | INTERNAL | 16.8432 | 3.08 | 51.8772
Kitchen | plot-30 0 | Kitchen 0 lr | INTERNAL | 16.9754 | 3.08 | 52.2841
Sahn | plot-30 0 | Sahn 0 rlr | EXTERNAL | 11.8267 | 3.08 | 36.4261
Toilet | plot-30 1 | Toilet 1 rrl | INTERNAL | 7.11086 | 2.48 | 17.6349
Stair | plot-30 1 | Stair 1 rrr | INTERNAL | 7.81924 | 2.48 | 19.3917
Bedroom | plot-30 1 | Bedroom 1 rll | INTERNAL | 16.8432 | 2.48 | 41.7712
Bedroom | plot-30 1 | Bedroom 1 lr | INTERNAL | 16.9754 | 2.48 | 42.0989
Sahn | plot-30 2 | Sahn 2 lr | EXTERNAL | 16.9754 | 2.48 | 42.0989
Bedroom | plot-30 2 | Bedroom 2 rll | INTERNAL | 16.8432 | 2.48 | 41.7712
Toilet | plot-30 2 | Toilet 2 rrl | INTERNAL | 7.11086 | 2.48 | 17.6349
Stair | plot-30 2 | Stair 2 rrr | INTERNAL | 7.81924 | 2.48 | 19.3917
Kitchen | plot-31 0 | Kitchen 0 lrl | INTERNAL | 12.6575 | 2.93 | 37.0865
Outside | plot-31 0 | Outside 0 lrr | EXTERNAL | 8.46453 | 2.93 | 24.8011
Living | plot-31 0 | Living 0 lll | INTERNAL | 14.5604 | 2.93 | 42.662
Stair | plot-31 0 | Stair 0 llr | INTERNAL | 8.84252 | 2.93 | 25.9086
Outside | plot-31 0 | Outside 0 r | EXTERNAL | 18.8292 | 2.93 | 55.1696
Bedroom | plot-31 1 | Bedroom 1 lll | INTERNAL | 14.5604 | 2.48 | 36.1098
Outside | plot-31 1 | Outside 1 lrl | EXTERNAL | 12.6575 | 2.48 | 31.3906
Toilet | plot-31 1 | Toilet 1 lrr | INTERNAL | 8.46453 | 2.48 | 20.992
Stair | plot-31 1 | Stair 1 llr | INTERNAL | 8.84252 | 2.48 | 21.9294
Bedroom | plot-31 2 | Bedroom 2 lll | INTERNAL | 14.5604 | 2.48 | 36.1098
Stair | plot-31 2 | Stair 2 llr | INTERNAL | 8.84252 | 2.48 | 21.9294
Bedroom | plot-31 2 | Bedroom 2 lrr | INTERNAL | 8.46453 | 2.48 | 20.992
Stair | plot-4 0 | Stair 0 lrl | INTERNAL | 7.59727 | 3.08 | 23.3996
Bedroom | plot-4 0 | Bedroom 0 lrr | INTERNAL | 8.33222 | 3.08 | 25.6632
Bedroom | plot-4 0 | Bedroom 0 llr | INTERNAL | 13.9316 | 3.08 | 42.9094
Outside | plot-4 0 | Outside 0 r | EXTERNAL | 25.6083 | 3.08 | 78.8735
Circulation | plot-4 0 | Circulation 0 llll | INTERNAL | 4.37765 | 3.08 | 13.4832
Toilet | plot-4 0 | Toilet 0 lllr | INTERNAL | 5.91378 | 3.08 | 18.2145
Stair | plot-4 1 | Stair 1 lrl | INTERNAL | 7.59727 | 3.38 | 25.6788
Kitchen | plot-4 1 | Kitchen 1 lrr | INTERNAL | 8.33222 | 3.38 | 28.1629
Living | plot-4 1 | Living 1 ll | INTERNAL | 25.3394 | 3.38 | 85.6472
Stair | plot-4 2 | Stair 2 lrl | INTERNAL | 7.59727 | 2.48 | 18.8412
Bedroom | plot-4 2 | Bedroom 2 lrr | INTERNAL | 8.33222 | 2.48 | 20.6639
Outside | plot-4 2 | Outside 2 ll | EXTERNAL | 25.3394 | 2.48 | 62.8418
Living | plot-5 0 | Living 0 rlr | INTERNAL | 13.853 | 2.63 | 36.4333
Stair | plot-5 0 | Stair 0 rrl | INTERNAL | 7.46739 | 2.63 | 19.6392
Toilet | plot-5 0 | Toilet 0 rrr | INTERNAL | 9.57936 | 2.63 | 25.1937
Outside | plot-5 0 | Outside 0 rll | EXTERNAL | 9.06254 | 2.63 | 23.8345
Outside | plot-5 0 | Outside 0 ll | EXTERNAL | 8.8756 | 2.63 | 23.3428
Kitchen | plot-5 0 | Kitchen 0 lr | INTERNAL | 9.55096 | 2.63 | 25.119
Stair | plot-5 1 | Stair 1 rrl | INTERNAL | 7.46739 | 3.08 | 22.9996
Bedroom | plot-5 1 | Bedroom 1 rrr | INTERNAL | 9.57936 | 3.08 | 29.5044
Bedroom | plot-5 1 | Bedroom 1 rlr | INTERNAL | 13.853 | 3.08 | 42.6672
Outside | plot-5 1 | Outside 1 lr | EXTERNAL | 9.55096 | 3.08 | 29.417
Stair | plot-5 2 | Stair 2 rrl | INTERNAL | 7.46739 | 2.48 | 18.5191
Bedroom | plot-5 2 | Bedroom 2 rrr | INTERNAL | 9.57936 | 2.48 | 23.7568
Outside | plot-5 2 | Outside 2 rlr | EXTERNAL | 13.853 | 2.48 | 34.3554
Bedroom | plot-6 0 | Bedroom 0 lll | INTERNAL | 11.217 | 3.38 | 37.9135
Sahn | plot-6 0 | Sahn 0 r | EXTERNAL | 25.5523 | 3.38 | 86.3667
Sahn | plot-6 0 | Sahn 0 lr | EXTERNAL | 15.9535 | 3.38 | 53.923
Stair | plot-6 0 | Stair 0 llr | INTERNAL | 8.52052 | 3.38 | 28.7994
Bedroom | plot-6 1 | Bedroom 1 lll | INTERNAL | 11.217 | 3.38 | 37.9135
Kitchen | plot-6 1 | Kitchen 1 lrl | INTERNAL | 6.73331 | 3.38 | 22.7586
Living | plot-6 1 | Living 1 lrr | INTERNAL | 8.75548 | 3.38 | 29.5935
Stair | plot-6 1 | Stair 1 llr | INTERNAL | 8.52052 | 3.38 | 28.7994
Toilet | plot-6 2 | Toilet 2 lll | INTERNAL | 11.217 | 2.63 | 29.5007
Bedroom | plot-6 2 | Bedroom 2 lr | INTERNAL | 15.9535 | 2.63 | 41.9578
Stair | plot-6 2 | Stair 2 llr | INTERNAL | 8.52052 | 2.63 | 22.409
Stair | plot-7 0 | Stair 0 rll | INTERNAL | 6.10293 | 2.93 | 17.8816
Living | plot-7 0 | Living 0 rr | INTERNAL | 22.0338 | 2.93 | 64.5592
Kitchen | plot-7 0 | Kitchen 0 rlr | INTERNAL | 10.6682 | 2.93 | 31.2579
Outside | plot-7 0 | Outside 0 l | EXTERNAL | 24.8 | 2.93 | 72.6641
Stair | plot-7 1 | Stair 1 rll | INTERNAL | 6.10293 | 2.48 | 15.1353
Bedroom | plot-7 1 | Bedroom 1 rlr | INTERNAL | 10.6682 | 2.48 | 26.4572
Bedroom | plot-7 1 | Bedroom 1 rrl | INTERNAL | 11.7137 | 2.48 | 29.05
Outside | plot-7 1 | Outside 1 rrr | EXTERNAL | 9.66529 | 2.48 | 23.9699
Stair | plot-7 2 | Stair 2 rll | INTERNAL | 6.10293 | 2.48 | 15.1353
Bedroom | plot-7 2 | Bedroom 2 rrl | INTERNAL | 11.7137 | 2.48 | 29.05
Toilet | plot-7 2 | Toilet 2 rlr | INTERNAL | 10.6682 | 2.48 | 26.4572
Outside | plot-8 0 | Outside 0 rll | EXTERNAL | 10.3995 | 2.63 | 27.3507
Living | plot-8 0 | Living 0 rlr | INTERNAL | 16.3947 | 2.63 | 43.1182
Bedroom | plot-8 0 | Bedroom 0 lrl | INTERNAL | 10.3433 | 2.63 | 27.2028
Stair | plot-8 0 | Stair 0 lrr | INTERNAL | 10.4106 | 2.63 | 27.3798
Outside | plot-8 0 | Outside 0 ll | EXTERNAL | 22.6439 | 2.63 | 59.5534
Kitchen | plot-8 0 | Kitchen 0 rr | INTERNAL | 14.079 | 2.63 | 37.0278
Toilet | plot-8 1 | Toilet 1 lrl | INTERNAL | 10.3433 | 2.48 | 25.6513
Bedroom | plot-8 1 | Bedroom 1 rlr | INTERNAL | 16.3947 | 2.48 | 40.659
Stair | plot-8 1 | Stair 1 lrr | INTERNAL | 10.4106 | 2.48 | 25.8182
Bedroom | plot-8 1 | Bedroom 1 rr | INTERNAL | 14.079 | 2.48 | 34.9159
Outside | plot-8 2 | Outside 2 rlr | EXTERNAL | 16.3947 | 2.48 | 40.659
Bedroom | plot-8 2 | Bedroom 2 lrl | INTERNAL | 10.3433 | 2.48 | 25.6513
Stair | plot-8 2 | Stair 2 lrr | INTERNAL | 10.4106 | 2.48 | 25.8182
Outside | plot-8 2 | Outside 2 rr | EXTERNAL | 14.079 | 2.48 | 34.9159
Living | plot-9 0 | Living 0 ll | INTERNAL | 18.3581 | 3.08 | 56.5429
Sahn | plot-9 0 | Sahn 0 lrl | EXTERNAL | 6.08953 | 3.08 | 18.7557
Kitchen | plot-9 0 | Kitchen 0 lrr | INTERNAL | 8.38945 | 3.08 | 25.8395
Stair | plot-9 0 | Stair 0 r | INTERNAL | 9.34363 | 3.08 | 28.7784
Bedroom | plot-9 1 | Bedroom 1 lll | INTERNAL | 9.90633 | 3.38 | 33.4834
Outside | plot-9 1 | Outside 1 lrr | EXTERNAL | 8.38945 | 3.38 | 28.3564
Toilet | plot-9 1 | Toilet 1 llr | INTERNAL | 7.84489 | 3.38 | 26.5157
Stair | plot-9 1 | Stair 1 r | INTERNAL | 9.34363 | 3.38 | 31.5815

# IfcAnnotation: DRAWING (257)
EPset_Drawing - HasUnderlay: no; HasLinework: yes; HasAnnotation: yes; GlobalReferencing: yes; Stylesheet: drawings/assets/default.css; Markers: drawings/assets/markers.svg; Symbols: drawings/assets/symbols.svg; Patterns: drawings/assets/patterns.svg; ShadingStyles: drawings/assets/shading_styles.json; CurrentShadingStyle: Blender Default
Name | Document | TargetView | Scale | HumanScale | PositionX | PositionY | Group | Include
plot-0 0 | drawings/plot-0 0.svg drawings/plot-0 0.svg | PLAN_VIEW | 1/100 | 1:100 | 30 | 30 | plot-0 0
plot-0 1 | drawings/plot-0 1.svg drawings/plot-0 1.svg | PLAN_VIEW | 1/100 | 1:100 | 164.2 | 30 | plot-0 1
plot-0 2 | drawings/plot-0 2.svg drawings/plot-0 2.svg | PLAN_VIEW | 1/100 | 1:100 | 298.4 | 30 | plot-0 2
Building plot-0 NORTH | drawings/Building plot-0 NORTH.svg drawings/Building plot-0 NORTH.svg | ELEVATION_VIEW | 1/100 | 1:100 | 30 | 179.245 | Building plot-0 NORTH | IfcTypeProduct, IfcProduct, location="Building plot-0"
Building plot-0 SOUTH | drawings/Building plot-0 SOUTH.svg drawings/Building plot-0 SOUTH.svg | ELEVATION_VIEW | 1/100 | 1:100 | 164.2 | 179.245 | Building plot-0 SOUTH | IfcTypeProduct, IfcProduct, location="Building plot-0"
Building plot-0 WEST | drawings/Building plot-0 WEST.svg drawings/Building plot-0 WEST.svg | ELEVATION_VIEW | 1/100 | 1:100 | 298.4 | 179.245 | Building plot-0 WEST | IfcTypeProduct, IfcProduct, location="Building plot-0"
Building plot-0 EAST | drawings/Building plot-0 EAST.svg drawings/Building plot-0 EAST.svg | ELEVATION_VIEW | 1/100 | 1:100 | 437.646 | 179.245 | Building plot-0 EAST | IfcTypeProduct, IfcProduct, location="Building plot-0"
Building plot-0 LOCATION | drawings/Building plot-0 LOCATION.svg drawings/Building plot-0 LOCATION.svg | PLAN_VIEW | 1/1000 | 1:1000 | 576.891 | 179.245 | Building plot-0 LOCATION | IfcSite + IfcRoof, IfcWall, IfcSlab, location="Building plot-0"
plot-1 0 | drawings/plot-1 0.svg drawings/plot-1 0.svg | PLAN_VIEW | 1/100 | 1:100 | 30 | 30 | plot-1 0
plot-1 1 | drawings/plot-1 1.svg drawings/plot-1 1.svg | PLAN_VIEW | 1/100 | 1:100 | 173.473 | 30 | plot-1 1
plot-1 2 | drawings/plot-1 2.svg drawings/plot-1 2.svg | PLAN_VIEW | 1/100 | 1:100 | 316.946 | 30 | plot-1 2
Building plot-1 NORTH | drawings/Building plot-1 NORTH.svg drawings/Building plot-1 NORTH.svg | ELEVATION_VIEW | 1/100 | 1:100 | 30 | 187.814 | Building plot-1 NORTH | IfcTypeProduct, IfcProduct, location="Building plot-1"
Building plot-1 SOUTH | drawings/Building plot-1 SOUTH.svg drawings/Building plot-1 SOUTH.svg | ELEVATION_VIEW | 1/100 | 1:100 | 173.473 | 187.814 | Building plot-1 SOUTH | IfcTypeProduct, IfcProduct, location="Building plot-1"
Building plot-1 WEST | drawings/Building plot-1 WEST.svg drawings/Building plot-1 WEST.svg | ELEVATION_VIEW | 1/100 | 1:100 | 316.946 | 187.814 | Building plot-1 WEST | IfcTypeProduct, IfcProduct, location="Building plot-1"
Building plot-1 EAST | drawings/Building plot-1 EAST.svg drawings/Building plot-1 EAST.svg | ELEVATION_VIEW | 1/100 | 1:100 | 464.759 | 187.814 | Building plot-1 EAST | IfcTypeProduct, IfcProduct, location="Building plot-1"
Building plot-1 LOCATION | drawings/Building plot-1 LOCATION.svg drawings/Building plot-1 LOCATION.svg | PLAN_VIEW | 1/1000 | 1:1000 | 612.573 | 187.814 | Building plot-1 LOCATION | IfcSite + IfcRoof, IfcWall, IfcSlab, location="Building plot-1"
plot-2 0 | drawings/plot-2 0.svg drawings/plot-2 0.svg | PLAN_VIEW | 1/100 | 1:100 | 30 | 30 | plot-2 0
plot-2 1 | drawings/plot-2 1.svg drawings/plot-2 1.svg | PLAN_VIEW | 1/100 | 1:100 | 159.797 | 30 | plot-2 1
plot-2 2 | drawings/plot-2 2.svg drawings/plot-2 2.svg | PLAN_VIEW | 1/100 | 1:100 | 289.594 | 30 | plot-2 2
Building plot-2 NORTH | drawings/Building plot-2 NORTH.svg drawings/Building plot-2 NORTH.svg | ELEVATION_VIEW | 1/100 | 1:100 | 30 | 180.217 | Building plot-2 NORTH | IfcTypeProduct, IfcProduct, location="Building plot-2"
Building plot-2 SOUTH | drawings/Building plot-2 SOUTH.svg drawings/Building plot-2 SOUTH.svg | ELEVATION_VIEW | 1/100 | 1:100 | 159.797 | 180.217 | Building plot-2 SOUTH | IfcTypeProduct, IfcProduct, location="Building plot-2"
Building plot-2 WEST | drawings/Building plot-2 WEST.svg drawings/Building plot-2 WEST.svg | ELEVATION_VIEW | 1/100 | 1:100 | 289.594 | 180.217 | Building plot-2 WEST | IfcTypeProduct, IfcProduct, location="Building plot-2"
Building plot-2 EAST | drawings/Building plot-2 EAST.svg drawings/Building plot-2 EAST.svg | ELEVATION_VIEW | 1/100 | 1:100 | 429.811 | 180.217 | Building plot-2 EAST | IfcTypeProduct, IfcProduct, location="Building plot-2"
Building plot-2 LOCATION | drawings/Building plot-2 LOCATION.svg drawings/Building plot-2 LOCATION.svg | PLAN_VIEW | 1/1000 | 1:1000 | 570.027 | 180.217 | Building plot-2 LOCATION | IfcSite + IfcRoof, IfcWall, IfcSlab, location="Building plot-2"
plot-3 0 | drawings/plot-3 0.svg drawings/plot-3 0.svg | PLAN_VIEW | 1/100 | 1:100 | 30 | 30 | plot-3 0
plot-3 1 | drawings/plot-3 1.svg drawings/plot-3 1.svg | PLAN_VIEW | 1/100 | 1:100 | 151.145 | 30 | plot-3 1
plot-3 2 | drawings/plot-3 2.svg drawings/plot-3 2.svg | PLAN_VIEW | 1/100 | 1:100 | 272.29 | 30 | plot-3 2
Building plot-3 NORTH | drawings/Building plot-3 NORTH.svg drawings/Building plot-3 NORTH.svg | ELEVATION_VIEW | 1/100 | 1:100 | 30 | 189.786 | Building plot-3 NORTH | IfcTypeProduct, IfcProduct, location="Building plot-3"
Building plot-3 SOUTH | drawings/Building plot-3 SOUTH.svg drawings/Building plot-3 SOUTH.svg | ELEVATION_VIEW | 1/100 | 1:100 | 151.145 | 189.786 | Building plot-3 SOUTH | IfcTypeProduct, IfcProduct, location="Building plot-3"
Building plot-3 WEST | drawings/Building plot-3 WEST.svg drawings/Building plot-3 WEST.svg | ELEVATION_VIEW | 1/100 | 1:100 | 272.29 | 189.786 | Building plot-3 WEST | IfcTypeProduct, IfcProduct, location="Building plot-3"
Building plot-3 EAST | drawings/Building plot-3 EAST.svg drawings/Building plot-3 EAST.svg | ELEVATION_VIEW | 1/100 | 1:100 | 422.076 | 189.786 | Building plot-3 EAST | IfcTypeProduct, IfcProduct, location="Building plot-3"
Building plot-3 LOCATION | drawings/Building plot-3 LOCATION.svg drawings/Building plot-3 LOCATION.svg | PLAN_VIEW | 1/1000 | 1:1000 | 571.863 | 189.786 | Building plot-3 LOCATION | IfcSite + IfcRoof, IfcWall, IfcSlab, location="Building plot-3"
plot-4 0 | drawings/plot-4 0.svg drawings/plot-4 0.svg | PLAN_VIEW | 1/100 | 1:100 | 30 | 30 | plot-4 0
plot-4 1 | drawings/plot-4 1.svg drawings/plot-4 1.svg | PLAN_VIEW | 1/100 | 1:100 | 180.17 | 30 | plot-4 1
plot-4 2 | drawings/plot-4 2.svg drawings/plot-4 2.svg | PLAN_VIEW | 1/100 | 1:100 | 330.34 | 30 | plot-4 2
Building plot-4 NORTH | drawings/Building plot-4 NORTH.svg drawings/Building plot-4 NORTH.svg | ELEVATION_VIEW | 1/100 | 1:100 | 30 | 195.301 | Building plot-4 NORTH | IfcTypeProduct, IfcProduct, location="Building plot-4"
Building plot-4 SOUTH | drawings/Building plot-4 SOUTH.svg drawings/Building plot-4 SOUTH.svg | ELEVATION_VIEW | 1/100 | 1:100 | 180.17 | 195.301 | Building plot-4 SOUTH | IfcTypeProduct, IfcProduct, location="Building plot-4"
Building plot-4 WEST | drawings/Building plot-4 WEST.svg drawings/Building plot-4 WEST.svg | ELEVATION_VIEW | 1/100 | 1:100 | 330.34 | 195.301 | Building plot-4 WEST | IfcTypeProduct, IfcProduct, location="Building plot-4"
Building plot-4 EAST | drawings/Building plot-4 EAST.svg drawings/Building plot-4 EAST.svg | ELEVATION_VIEW | 1/100 | 1:100 | 485.641 | 195.301 | Building plot-4 EAST | IfcTypeProduct, IfcProduct, location="Building plot-4"
Building plot-4 LOCATION | drawings/Building plot-4 LOCATION.svg drawings/Building plot-4 LOCATION.svg | PLAN_VIEW | 1/1000 | 1:1000 | 640.941 | 195.301 | Building plot-4 LOCATION | IfcSite + IfcRoof, IfcWall, IfcSlab, location="Building plot-4"
plot-5 0 | drawings/plot-5 0.svg drawings/plot-5 0.svg | PLAN_VIEW | 1/100 | 1:100 | 30 | 30 | plot-5 0
plot-5 1 | drawings/plot-5 1.svg drawings/plot-5 1.svg | PLAN_VIEW | 1/100 | 1:100 | 198.333 | 30 | plot-5 1
plot-5 2 | drawings/plot-5 2.svg drawings/plot-5 2.svg | PLAN_VIEW | 1/100 | 1:100 | 366.665 | 30 | plot-5 2
Building plot-5 NORTH | drawings/Building plot-5 NORTH.svg drawings/Building plot-5 NORTH.svg | ELEVATION_VIEW | 1/100 | 1:100 | 30 | 169.298 | Building plot-5 NORTH | IfcTypeProduct, IfcProduct, location="Building plot-5"
Building plot-5 SOUTH | drawings/Building plot-5 SOUTH.svg drawings/Building plot-5 SOUTH.svg | ELEVATION_VIEW | 1/100 | 1:100 | 198.333 | 169.298 | Building plot-5 SOUTH | IfcTypeProduct, IfcProduct, location="Building plot-5"
Building plot-5 WEST | drawings/Building plot-5 WEST.svg drawings/Building plot-5 WEST.svg | ELEVATION_VIEW | 1/100 | 1:100 | 366.665 | 169.298 | Building plot-5 WEST | IfcTypeProduct, IfcProduct, location="Building plot-5"
Building plot-5 EAST | drawings/Building plot-5 EAST.svg drawings/Building plot-5 EAST.svg | ELEVATION_VIEW | 1/100 | 1:100 | 495.963 | 169.298 | Building plot-5 EAST | IfcTypeProduct, IfcProduct, location="Building plot-5"
Building plot-5 LOCATION | drawings/Building plot-5 LOCATION.svg drawings/Building plot-5 LOCATION.svg | PLAN_VIEW | 1/1000 | 1:1000 | 625.261 | 169.298 | Building plot-5 LOCATION | IfcSite + IfcRoof, IfcWall, IfcSlab, location="Building plot-5"
plot-6 0 | drawings/plot-6 0.svg drawings/plot-6 0.svg | PLAN_VIEW | 1/100 | 1:100 | 30 | 30 | plot-6 0
plot-6 1 | drawings/plot-6 1.svg drawings/plot-6 1.svg | PLAN_VIEW | 1/100 | 1:100 | 188.716 | 30 | plot-6 1
plot-6 2 | drawings/plot-6 2.svg drawings/plot-6 2.svg | PLAN_VIEW | 1/100 | 1:100 | 347.431 | 30 | plot-6 2
Building plot-6 NORTH | drawings/Building plot-6 NORTH.svg drawings/Building plot-6 NORTH.svg | ELEVATION_VIEW | 1/100 | 1:100 | 30 | 186.206 | Building plot-6 NORTH | IfcTypeProduct, IfcProduct, location="Building plot-6"
Building plot-6 SOUTH | drawings/Building plot-6 SOUTH.svg drawings/Building plot-6 SOUTH.svg | ELEVATION_VIEW | 1/100 | 1:100 | 188.716 | 186.206 | Building plot-6 SOUTH | IfcTypeProduct, IfcProduct, location="Building plot-6"
Building plot-6 WEST | drawings/Building plot-6 WEST.svg drawings/Building plot-6 WEST.svg | ELEVATION_VIEW | 1/100 | 1:100 | 347.431 | 186.206 | Building plot-6 WEST | IfcTypeProduct, IfcProduct, location="Building plot-6"
Building plot-6 EAST | drawings/Building plot-6 EAST.svg drawings/Building plot-6 EAST.svg | ELEVATION_VIEW | 1/100 | 1:100 | 493.638 | 186.206 | Building plot-6 EAST | IfcTypeProduct, IfcProduct, location="Building plot-6"
Building plot-6 LOCATION | drawings/Building plot-6 LOCATION.svg drawings/Building plot-6 LOCATION.svg | PLAN_VIEW | 1/1000 | 1:1000 | 639.844 | 186.206 | Building plot-6 LOCATION | IfcSite + IfcRoof, IfcWall, IfcSlab, location="Building plot-6"
plot-7 0 | drawings/plot-7 0.svg drawings/plot-7 0.svg | PLAN_VIEW | 1/100 | 1:100 | 30 | 30 | plot-7 0
plot-7 1 | drawings/plot-7 1.svg drawings/plot-7 1.svg | PLAN_VIEW | 1/100 | 1:100 | 173.112 | 30 | plot-7 1
plot-7 2 | drawings/plot-7 2.svg drawings/plot-7 2.svg | PLAN_VIEW | 1/100 | 1:100 | 316.224 | 30 | plot-7 2
Building plot-7 NORTH | drawings/Building plot-7 NORTH.svg drawings/Building plot-7 NORTH.svg | ELEVATION_VIEW | 1/100 | 1:100 | 30 | 205.054 | Building plot-7 NORTH | IfcTypeProduct, IfcProduct, location="Building plot-7"
Building plot-7 SOUTH | drawings/Building plot-7 SOUTH.svg drawings/Building plot-7 SOUTH.svg | ELEVATION_VIEW | 1/100 | 1:100 | 173.112 | 205.054 | Building plot-7 SOUTH | IfcTypeProduct, IfcProduct, location="Building plot-7"
Building plot-7 WEST | drawings/Building plot-7 WEST.svg drawings/Building plot-7 WEST.svg | ELEVATION_VIEW | 1/100 | 1:100 | 316.224 | 205.054 | Building plot-7 WEST | IfcTypeProduct, IfcProduct, location="Building plot-7"
Building plot-7 EAST | drawings/Building plot-7 EAST.svg drawings/Building plot-7 EAST.svg | ELEVATION_VIEW | 1/100 | 1:100 | 481.278 | 205.054 | Building plot-7 EAST | IfcTypeProduct, IfcProduct, location="Building plot-7"
Building plot-7 LOCATION | drawings/Building plot-7 LOCATION.svg drawings/Building plot-7 LOCATION.svg | PLAN_VIEW | 1/1000 | 1:1000 | 646.331 | 205.054 | Building plot-7 LOCATION | IfcSite + IfcRoof, IfcWall, IfcSlab, location="Building plot-7"
plot-8 0 | drawings/plot-8 0.svg drawings/plot-8 0.svg | PLAN_VIEW | 1/100 | 1:100 | 30 | 30 | plot-8 0
plot-8 1 | drawings/plot-8 1.svg drawings/plot-8 1.svg | PLAN_VIEW | 1/100 | 1:100 | 184.386 | 30 | plot-8 1
plot-8 2 | drawings/plot-8 2.svg drawings/plot-8 2.svg | PLAN_VIEW | 1/100 | 1:100 | 338.771 | 30 | plot-8 2
Building plot-8 NORTH | drawings/Building plot-8 NORTH.svg drawings/Building plot-8 NORTH.svg | ELEVATION_VIEW | 1/100 | 1:100 | 30 | 196.712 | Building plot-8 NORTH | IfcTypeProduct, IfcProduct, location="Building plot-8"
Building plot-8 SOUTH | drawings/Building plot-8 SOUTH.svg drawings/Building plot-8 SOUTH.svg | ELEVATION_VIEW | 1/100 | 1:100 | 184.386 | 196.712 | Building plot-8 SOUTH | IfcTypeProduct, IfcProduct, location="Building plot-8"
Building plot-8 WEST | drawings/Building plot-8 WEST.svg drawings/Building plot-8 WEST.svg | ELEVATION_VIEW | 1/100 | 1:100 | 338.771 | 196.712 | Building plot-8 WEST | IfcTypeProduct, IfcProduct, location="Building plot-8"
Building plot-8 EAST | drawings/Building plot-8 EAST.svg drawings/Building plot-8 EAST.svg | ELEVATION_VIEW | 1/100 | 1:100 | 495.483 | 196.712 | Building plot-8 EAST | IfcTypeProduct, IfcProduct, location="Building plot-8"
Building plot-8 LOCATION | drawings/Building plot-8 LOCATION.svg drawings/Building plot-8 LOCATION.svg | PLAN_VIEW | 1/1000 | 1:1000 | 652.195 | 196.712 | Building plot-8 LOCATION | IfcSite + IfcRoof, IfcWall, IfcSlab, location="Building plot-8"
plot-9 0 | drawings/plot-9 0.svg drawings/plot-9 0.svg | PLAN_VIEW | 1/100 | 1:100 | 30 | 30 | plot-9 0
plot-9 1 | drawings/plot-9 1.svg drawings/plot-9 1.svg | PLAN_VIEW | 1/100 | 1:100 | 151.181 | 30 | plot-9 1
Building plot-9 NORTH | drawings/Building plot-9 NORTH.svg drawings/Building plot-9 NORTH.svg | ELEVATION_VIEW | 1/100 | 1:100 | 30 | 171.04 | Building plot-9 NORTH | IfcTypeProduct, IfcProduct, location="Building plot-9"
Building plot-9 SOUTH | drawings/Building plot-9 SOUTH.svg drawings/Building plot-9 SOUTH.svg | ELEVATION_VIEW | 1/100 | 1:100 | 151.181 | 171.04 | Building plot-9 SOUTH | IfcTypeProduct, IfcProduct, location="Building plot-9"
Building plot-9 WEST | drawings/Building plot-9 WEST.svg drawings/Building plot-9 WEST.svg | ELEVATION_VIEW | 1/100 | 1:100 | 272.362 | 171.04 | Building plot-9 WEST | IfcTypeProduct, IfcProduct, location="Building plot-9"
Building plot-9 EAST | drawings/Building plot-9 EAST.svg drawings/Building plot-9 EAST.svg | ELEVATION_VIEW | 1/100 | 1:100 | 403.402 | 171.04 | Building plot-9 EAST | IfcTypeProduct, IfcProduct, location="Building plot-9"
Building plot-9 LOCATION | drawings/Building plot-9 LOCATION.svg drawings/Building plot-9 LOCATION.svg | PLAN_VIEW | 1/1000 | 1:1000 | 534.441 | 171.04 | Building plot-9 LOCATION | IfcSite + IfcRoof, IfcWall, IfcSlab, location="Building plot-9"
plot-10 0 | drawings/plot-10 0.svg drawings/plot-10 0.svg | PLAN_VIEW | 1/100 | 1:100 | 30 | 30 | plot-10 0
plot-10 1 | drawings/plot-10 1.svg drawings/plot-10 1.svg | PLAN_VIEW | 1/100 | 1:100 | 151.279 | 30 | plot-10 1
plot-10 2 | drawings/plot-10 2.svg drawings/plot-10 2.svg | PLAN_VIEW | 1/100 | 1:100 | 272.559 | 30 | plot-10 2
plot-10 3 | drawings/plot-10 3.svg drawings/plot-10 3.svg | PLAN_VIEW | 1/100 | 1:100 | 393.838 | 30 | plot-10 3
Building plot-10 NORTH | drawings/Building plot-10 NORTH.svg drawings/Building plot-10 NORTH.svg | ELEVATION_VIEW | 1/100 | 1:100 | 30 | 182.941 | Building plot-10 NORTH | IfcTypeProduct, IfcProduct, location="Building plot-10"
Building plot-10 SOUTH | drawings/Building plot-10 SOUTH.svg drawings/Building plot-10 SOUTH.svg | ELEVATION_VIEW | 1/100 | 1:100 | 151.279 | 182.941 | Building plot-10 SOUTH | IfcTypeProduct, IfcProduct, location="Building plot-10"
Building plot-10 WEST | drawings/Building plot-10 WEST.svg drawings/Building plot-10 WEST.svg | ELEVATION_VIEW | 1/100 | 1:100 | 272.559 | 182.941 | Building plot-10 WEST | IfcTypeProduct, IfcProduct, location="Building plot-10"
Building plot-10 EAST | drawings/Building plot-10 EAST.svg drawings/Building plot-10 EAST.svg | ELEVATION_VIEW | 1/100 | 1:100 | 415.5 | 182.941 | Building plot-10 EAST | IfcTypeProduct, IfcProduct, location="Building plot-10"
Building plot-10 LOCATION | drawings/Building plot-10 LOCATION.svg drawings/Building plot-10 LOCATION.svg | PLAN_VIEW | 1/1000 | 1:1000 | 558.442 | 182.941 | Building plot-10 LOCATION | IfcSite + IfcRoof, IfcWall, IfcSlab, location="Building plot-10"
plot-11 0 | drawings/plot-11 0.svg drawings/plot-11 0.svg | PLAN_VIEW | 1/100 | 1:100 | 30 | 30 | plot-11 0
plot-11 1 | drawings/plot-11 1.svg drawings/plot-11 1.svg | PLAN_VIEW | 1/100 | 1:100 | 171.499 | 30 | plot-11 1
plot-11 2 | drawings/plot-11 2.svg drawings/plot-11 2.svg | PLAN_VIEW | 1/100 | 1:100 | 312.998 | 30 | plot-11 2
Building plot-11 NORTH | drawings/Building plot-11 NORTH.svg drawings/Building plot-11 NORTH.svg | ELEVATION_VIEW | 1/100 | 1:100 | 30 | 200.101 | Building plot-11 NORTH | IfcTypeProduct, IfcProduct, location="Building plot-11"
Building plot-11 SOUTH | drawings/Building plot-11 SOUTH.svg drawings/Building plot-11 SOUTH.svg | ELEVATION_VIEW | 1/100 | 1:100 | 171.499 | 200.101 | Building plot-11 SOUTH | IfcTypeProduct, IfcProduct, location="Building plot-11"
Building plot-11 WEST | drawings/Building plot-11 WEST.svg drawings/Building plot-11 WEST.svg | ELEVATION_VIEW | 1/100 | 1:100 | 312.998 | 200.101 | Building plot-11 WEST | IfcTypeProduct, IfcProduct, location="Building plot-11"
Building plot-11 EAST | drawings/Building plot-11 EAST.svg drawings/Building plot-11 EAST.svg | ELEVATION_VIEW | 1/100 | 1:100 | 473.099 | 200.101 | Building plot-11 EAST | IfcTypeProduct, IfcProduct, location="Building plot-11"
Building plot-11 LOCATION | drawings/Building plot-11 LOCATION.svg drawings/Building plot-11 LOCATION.svg | PLAN_VIEW | 1/1000 | 1:1000 | 633.199 | 200.101 | Building plot-11 LOCATION | IfcSite + IfcRoof, IfcWall, IfcSlab, location="Building plot-11"
plot-12 0 | drawings/plot-12 0.svg drawings/plot-12 0.svg | PLAN_VIEW | 1/100 | 1:100 | 30 | 30 | plot-12 0
plot-12 1 | drawings/plot-12 1.svg drawings/plot-12 1.svg | PLAN_VIEW | 1/100 | 1:100 | 165.91 | 30 | plot-12 1
plot-12 2 | drawings/plot-12 2.svg drawings/plot-12 2.svg | PLAN_VIEW | 1/100 | 1:100 | 301.821 | 30 | plot-12 2
Building plot-12 NORTH | drawings/Building plot-12 NORTH.svg drawings/Building plot-12 NORTH.svg | ELEVATION_VIEW | 1/100 | 1:100 | 30 | 182.226 | Building plot-12 NORTH | IfcTypeProduct, IfcProduct, location="Building plot-12"
Building plot-12 SOUTH | drawings/Building plot-12 SOUTH.svg drawings/Building plot-12 SOUTH.svg | ELEVATION_VIEW | 1/100 | 1:100 | 165.91 | 182.226 | Building plot-12 SOUTH | IfcTypeProduct, IfcProduct, location="Building plot-12"
Building plot-12 WEST | drawings/Building plot-12 WEST.svg drawings/Building plot-12 WEST.svg | ELEVATION_VIEW | 1/100 | 1:100 | 301.821 | 182.226 | Building plot-12 WEST | IfcTypeProduct, IfcProduct, location="Building plot-12"
Building plot-12 EAST | drawings/Building plot-12 EAST.svg drawings/Building plot-12 EAST.svg | ELEVATION_VIEW | 1/100 | 1:100 | 444.047 | 182.226 | Building plot-12 EAST | IfcTypeProduct, IfcProduct, location="Building plot-12"
Building plot-12 LOCATION | drawings/Building plot-12 LOCATION.svg drawings/Building plot-12 LOCATION.svg | PLAN_VIEW | 1/1000 | 1:1000 | 586.274 | 182.226 | Building plot-12 LOCATION | IfcSite + IfcRoof, IfcWall, IfcSlab, location="Building plot-12"
plot-13 0 | drawings/plot-13 0.svg drawings/plot-13 0.svg | PLAN_VIEW | 1/100 | 1:100 | 30 | 30 | plot-13 0
plot-13 1 | drawings/plot-13 1.svg drawings/plot-13 1.svg | PLAN_VIEW | 1/100 | 1:100 | 167.171 | 30 | plot-13 1
plot-13 2 | drawings/plot-13 2.svg drawings/plot-13 2.svg | PLAN_VIEW | 1/100 | 1:100 | 304.342 | 30 | plot-13 2
Building plot-13 NORTH | drawings/Building plot-13 NORTH.svg drawings/Building plot-13 NORTH.svg | ELEVATION_VIEW | 1/100 | 1:100 | 30 | 187.037 | Building plot-13 NORTH | IfcTypeProduct, IfcProduct, location="Building plot-13"
Building plot-13 SOUTH | drawings/Building plot-13 SOUTH.svg drawings/Building plot-13 SOUTH.svg | ELEVATION_VIEW | 1/100 | 1:100 | 167.171 | 187.037 | Building plot-13 SOUTH | IfcTypeProduct, IfcProduct, location="Building plot-13"
Building plot-13 WEST | drawings/Building plot-13 WEST.svg drawings/Building plot-13 WEST.svg | ELEVATION_VIEW | 1/100 | 1:100 | 304.342 | 187.037 | Building plot-13 WEST | IfcTypeProduct, IfcProduct, location="Building plot-13"
Building plot-13 EAST | drawings/Building plot-13 EAST.svg drawings/Building plot-13 EAST.svg | ELEVATION_VIEW | 1/100 | 1:100 | 451.379 | 187.037 | Building plot-13 EAST | IfcTypeProduct, IfcProduct, location="Building plot-13"
Building plot-13 LOCATION | drawings/Building plot-13 LOCATION.svg drawings/Building plot-13 LOCATION.svg | PLAN_VIEW | 1/1000 | 1:1000 | 598.416 | 187.037 | Building plot-13 LOCATION | IfcSite + IfcRoof, IfcWall, IfcSlab, location="Building plot-13"
plot-14 0 | drawings/plot-14 0.svg drawings/plot-14 0.svg | PLAN_VIEW | 1/100 | 1:100 | 30 | 30 | plot-14 0
plot-14 1 | drawings/plot-14 1.svg drawings/plot-14 1.svg | PLAN_VIEW | 1/100 | 1:100 | 159.587 | 30 | plot-14 1
plot-14 2 | drawings/plot-14 2.svg drawings/plot-14 2.svg | PLAN_VIEW | 1/100 | 1:100 | 289.174 | 30 | plot-14 2
plot-14 3 | drawings/plot-14 3.svg drawings/plot-14 3.svg | PLAN_VIEW | 1/100 | 1:100 | 418.761 | 30 | plot-14 3
Building plot-14 NORTH | drawings/Building plot-14 NORTH.svg drawings/Building plot-14 NORTH.svg | ELEVATION_VIEW | 1/100 | 1:100 | 30 | 193.687 | Building plot-14 NORTH | IfcTypeProduct, IfcProduct, location="Building plot-14"
Building plot-14 SOUTH | drawings/Building plot-14 SOUTH.svg drawings/Building plot-14 SOUTH.svg | ELEVATION_VIEW | 1/100 | 1:100 | 159.587 | 193.687 | Building plot-14 SOUTH | IfcTypeProduct, IfcProduct, location="Building plot-14"
Building plot-14 WEST | drawings/Building plot-14 WEST.svg drawings/Building plot-14 WEST.svg | ELEVATION_VIEW | 1/100 | 1:100 | 289.174 | 193.687 | Building plot-14 WEST | IfcTypeProduct, IfcProduct, location="Building plot-14"
Building plot-14 EAST | drawings/Building plot-14 EAST.svg drawings/Building plot-14 EAST.svg | ELEVATION_VIEW | 1/100 | 1:100 | 442.861 | 193.687 | Building plot-14 EAST | IfcTypeProduct, IfcProduct, location="Building plot-14"
Building plot-14 LOCATION | drawings/Building plot-14 LOCATION.svg drawings/Building plot-14 LOCATION.svg | PLAN_VIEW | 1/1000 | 1:1000 | 596.548 | 193.687 | Building plot-14 LOCATION | IfcSite + IfcRoof, IfcWall, IfcSlab, location="Building plot-14"
plot-15 0 | drawings/plot-15 0.svg drawings/plot-15 0.svg | PLAN_VIEW | 1/100 | 1:100 | 30 | 30 | plot-15 0
plot-15 1 | drawings/plot-15 1.svg drawings/plot-15 1.svg | PLAN_VIEW | 1/100 | 1:100 | 178.491 | 30 | plot-15 1
plot-15 2 | drawings/plot-15 2.svg drawings/plot-15 2.svg | PLAN_VIEW | 1/100 | 1:100 | 326.981 | 30 | plot-15 2
Building plot-15 NORTH | drawings/Building plot-15 NORTH.svg drawings/Building plot-15 NORTH.svg | ELEVATION_VIEW | 1/100 | 1:100 | 30 | 192.104 | Building plot-15 NORTH | IfcTypeProduct, IfcProduct, location="Building plot-15"
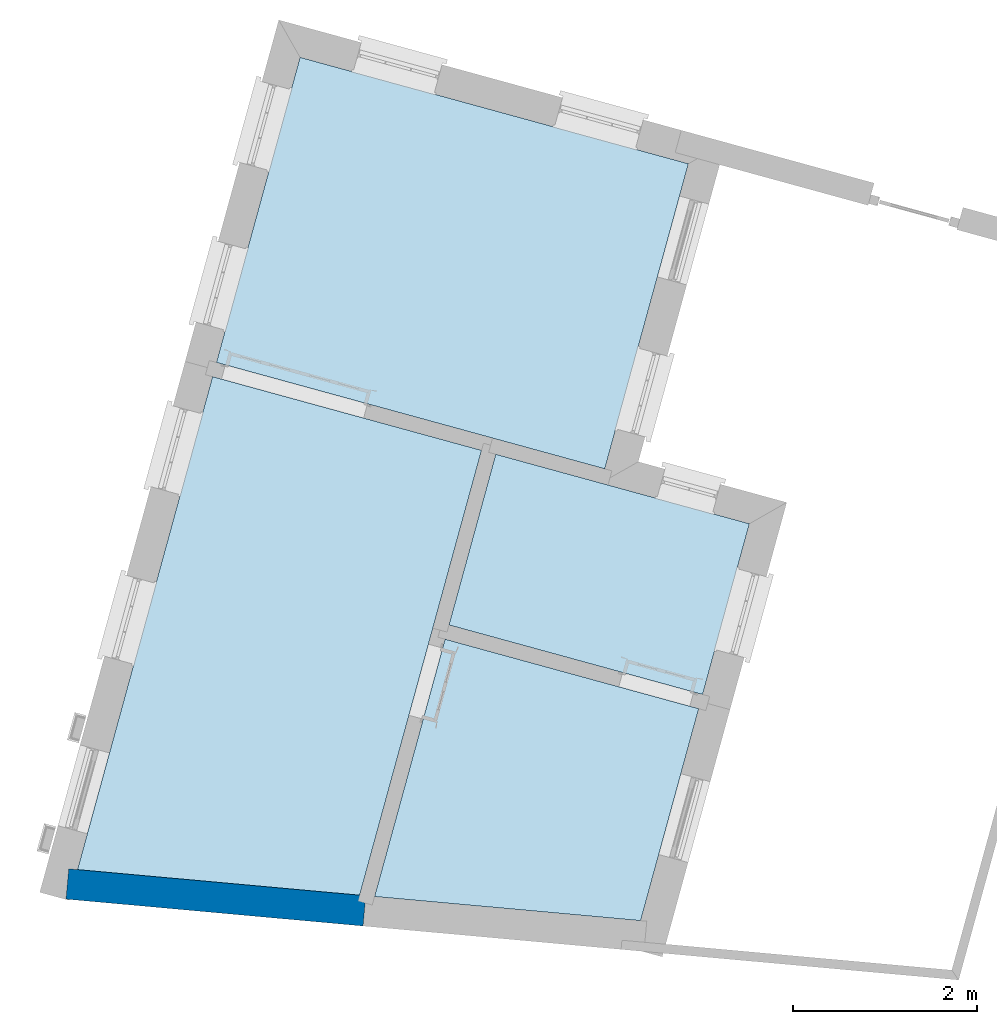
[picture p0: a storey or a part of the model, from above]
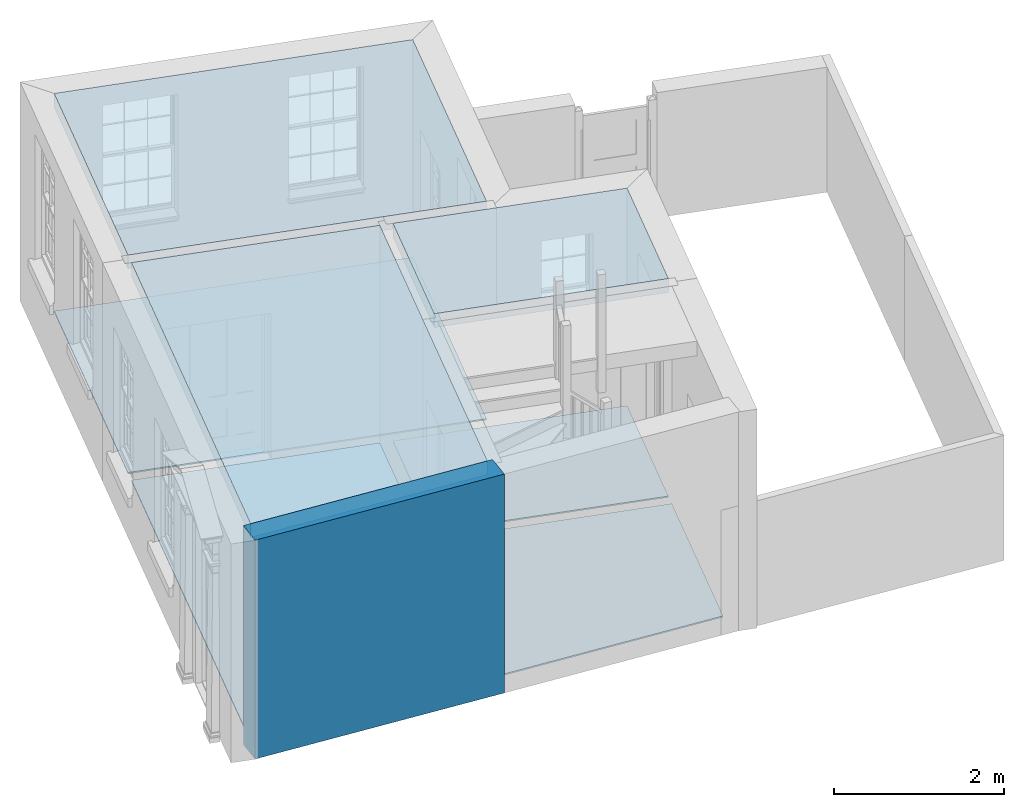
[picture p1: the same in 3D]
Properties of the parts of a building model (IFC4), part 2 of 4

# IfcAnnotation: DRAWING (257)
Name | Document | TargetView | Scale | HumanScale | PositionX | PositionY | Group | Include
Building plot-15 SOUTH | drawings/Building plot-15 SOUTH.svg drawings/Building plot-15 SOUTH.svg | ELEVATION_VIEW | 1/100 | 1:100 | 178.491 | 192.104 | Building plot-15 SOUTH | IfcTypeProduct, IfcProduct, location="Building plot-15"
Building plot-15 WEST | drawings/Building plot-15 WEST.svg drawings/Building plot-15 WEST.svg | ELEVATION_VIEW | 1/100 | 1:100 | 326.981 | 192.104 | Building plot-15 WEST | IfcTypeProduct, IfcProduct, location="Building plot-15"
Building plot-15 EAST | drawings/Building plot-15 EAST.svg drawings/Building plot-15 EAST.svg | ELEVATION_VIEW | 1/100 | 1:100 | 479.085 | 192.104 | Building plot-15 EAST | IfcTypeProduct, IfcProduct, location="Building plot-15"
Building plot-15 LOCATION | drawings/Building plot-15 LOCATION.svg drawings/Building plot-15 LOCATION.svg | PLAN_VIEW | 1/1000 | 1:1000 | 631.19 | 192.104 | Building plot-15 LOCATION | IfcSite + IfcRoof, IfcWall, IfcSlab, location="Building plot-15"
plot-16 0 | drawings/plot-16 0.svg drawings/plot-16 0.svg | PLAN_VIEW | 1/100 | 1:100 | 30 | 30 | plot-16 0
plot-16 1 | drawings/plot-16 1.svg drawings/plot-16 1.svg | PLAN_VIEW | 1/100 | 1:100 | 183.713 | 30 | plot-16 1
plot-16 2 | drawings/plot-16 2.svg drawings/plot-16 2.svg | PLAN_VIEW | 1/100 | 1:100 | 337.427 | 30 | plot-16 2
plot-16 3 | drawings/plot-16 3.svg drawings/plot-16 3.svg | PLAN_VIEW | 1/100 | 1:100 | 491.14 | 30 | plot-16 3
Building plot-16 NORTH | drawings/Building plot-16 NORTH.svg drawings/Building plot-16 NORTH.svg | ELEVATION_VIEW | 1/100 | 1:100 | 30 | 191.142 | Building plot-16 NORTH | IfcTypeProduct, IfcProduct, location="Building plot-16"
Building plot-16 SOUTH | drawings/Building plot-16 SOUTH.svg drawings/Building plot-16 SOUTH.svg | ELEVATION_VIEW | 1/100 | 1:100 | 183.713 | 191.142 | Building plot-16 SOUTH | IfcTypeProduct, IfcProduct, location="Building plot-16"
Building plot-16 WEST | drawings/Building plot-16 WEST.svg drawings/Building plot-16 WEST.svg | ELEVATION_VIEW | 1/100 | 1:100 | 337.427 | 191.142 | Building plot-16 WEST | IfcTypeProduct, IfcProduct, location="Building plot-16"
Building plot-16 EAST | drawings/Building plot-16 EAST.svg drawings/Building plot-16 EAST.svg | ELEVATION_VIEW | 1/100 | 1:100 | 488.569 | 191.142 | Building plot-16 EAST | IfcTypeProduct, IfcProduct, location="Building plot-16"
Building plot-16 LOCATION | drawings/Building plot-16 LOCATION.svg drawings/Building plot-16 LOCATION.svg | PLAN_VIEW | 1/1000 | 1:1000 | 639.71 | 191.142 | Building plot-16 LOCATION | IfcSite + IfcRoof, IfcWall, IfcSlab, location="Building plot-16"
plot-17 0 | drawings/plot-17 0.svg drawings/plot-17 0.svg | PLAN_VIEW | 1/100 | 1:100 | 30 | 30 | plot-17 0
plot-17 1 | drawings/plot-17 1.svg drawings/plot-17 1.svg | PLAN_VIEW | 1/100 | 1:100 | 155.005 | 30 | plot-17 1
plot-17 2 | drawings/plot-17 2.svg drawings/plot-17 2.svg | PLAN_VIEW | 1/100 | 1:100 | 280.01 | 30 | plot-17 2
Building plot-17 NORTH | drawings/Building plot-17 NORTH.svg drawings/Building plot-17 NORTH.svg | ELEVATION_VIEW | 1/100 | 1:100 | 30 | 170.358 | Building plot-17 NORTH | IfcTypeProduct, IfcProduct, location="Building plot-17"
Building plot-17 SOUTH | drawings/Building plot-17 SOUTH.svg drawings/Building plot-17 SOUTH.svg | ELEVATION_VIEW | 1/100 | 1:100 | 155.005 | 170.358 | Building plot-17 SOUTH | IfcTypeProduct, IfcProduct, location="Building plot-17"
Building plot-17 WEST | drawings/Building plot-17 WEST.svg drawings/Building plot-17 WEST.svg | ELEVATION_VIEW | 1/100 | 1:100 | 280.01 | 170.358 | Building plot-17 WEST | IfcTypeProduct, IfcProduct, location="Building plot-17"
Building plot-17 EAST | drawings/Building plot-17 EAST.svg drawings/Building plot-17 EAST.svg | ELEVATION_VIEW | 1/100 | 1:100 | 410.368 | 170.358 | Building plot-17 EAST | IfcTypeProduct, IfcProduct, location="Building plot-17"
Building plot-17 LOCATION | drawings/Building plot-17 LOCATION.svg drawings/Building plot-17 LOCATION.svg | PLAN_VIEW | 1/1000 | 1:1000 | 540.726 | 170.358 | Building plot-17 LOCATION | IfcSite + IfcRoof, IfcWall, IfcSlab, location="Building plot-17"
plot-18 0 | drawings/plot-18 0.svg drawings/plot-18 0.svg | PLAN_VIEW | 1/100 | 1:100 | 30 | 30 | plot-18 0
plot-18 1 | drawings/plot-18 1.svg drawings/plot-18 1.svg | PLAN_VIEW | 1/100 | 1:100 | 170.588 | 30 | plot-18 1
plot-18 2 | drawings/plot-18 2.svg drawings/plot-18 2.svg | PLAN_VIEW | 1/100 | 1:100 | 311.176 | 30 | plot-18 2
plot-18 3 | drawings/plot-18 3.svg drawings/plot-18 3.svg | PLAN_VIEW | 1/100 | 1:100 | 451.764 | 30 | plot-18 3
Building plot-18 NORTH | drawings/Building plot-18 NORTH.svg drawings/Building plot-18 NORTH.svg | ELEVATION_VIEW | 1/100 | 1:100 | 30 | 208.846 | Building plot-18 NORTH | IfcTypeProduct, IfcProduct, location="Building plot-18"
Building plot-18 SOUTH | drawings/Building plot-18 SOUTH.svg drawings/Building plot-18 SOUTH.svg | ELEVATION_VIEW | 1/100 | 1:100 | 170.588 | 208.846 | Building plot-18 SOUTH | IfcTypeProduct, IfcProduct, location="Building plot-18"
Building plot-18 WEST | drawings/Building plot-18 WEST.svg drawings/Building plot-18 WEST.svg | ELEVATION_VIEW | 1/100 | 1:100 | 311.176 | 208.846 | Building plot-18 WEST | IfcTypeProduct, IfcProduct, location="Building plot-18"
Building plot-18 EAST | drawings/Building plot-18 EAST.svg drawings/Building plot-18 EAST.svg | ELEVATION_VIEW | 1/100 | 1:100 | 480.022 | 208.846 | Building plot-18 EAST | IfcTypeProduct, IfcProduct, location="Building plot-18"
Building plot-18 LOCATION | drawings/Building plot-18 LOCATION.svg drawings/Building plot-18 LOCATION.svg | PLAN_VIEW | 1/1000 | 1:1000 | 648.867 | 208.846 | Building plot-18 LOCATION | IfcSite + IfcRoof, IfcWall, IfcSlab, location="Building plot-18"
plot-19 0 | drawings/plot-19 0.svg drawings/plot-19 0.svg | PLAN_VIEW | 1/100 | 1:100 | 30 | 30 | plot-19 0
plot-19 1 | drawings/plot-19 1.svg drawings/plot-19 1.svg | PLAN_VIEW | 1/100 | 1:100 | 158.045 | 30 | plot-19 1
Building plot-19 NORTH | drawings/Building plot-19 NORTH.svg drawings/Building plot-19 NORTH.svg | ELEVATION_VIEW | 1/100 | 1:100 | 30 | 181.347 | Building plot-19 NORTH | IfcTypeProduct, IfcProduct, location="Building plot-19"
Building plot-19 SOUTH | drawings/Building plot-19 SOUTH.svg drawings/Building plot-19 SOUTH.svg | ELEVATION_VIEW | 1/100 | 1:100 | 158.045 | 181.347 | Building plot-19 SOUTH | IfcTypeProduct, IfcProduct, location="Building plot-19"
Building plot-19 WEST | drawings/Building plot-19 WEST.svg drawings/Building plot-19 WEST.svg | ELEVATION_VIEW | 1/100 | 1:100 | 286.09 | 181.347 | Building plot-19 WEST | IfcTypeProduct, IfcProduct, location="Building plot-19"
Building plot-19 EAST | drawings/Building plot-19 EAST.svg drawings/Building plot-19 EAST.svg | ELEVATION_VIEW | 1/100 | 1:100 | 427.437 | 181.347 | Building plot-19 EAST | IfcTypeProduct, IfcProduct, location="Building plot-19"
Building plot-19 LOCATION | drawings/Building plot-19 LOCATION.svg drawings/Building plot-19 LOCATION.svg | PLAN_VIEW | 1/1000 | 1:1000 | 568.784 | 181.347 | Building plot-19 LOCATION | IfcSite + IfcRoof, IfcWall, IfcSlab, location="Building plot-19"
plot-20 0 | drawings/plot-20 0.svg drawings/plot-20 0.svg | PLAN_VIEW | 1/100 | 1:100 | 30 | 30 | plot-20 0
plot-20 1 | drawings/plot-20 1.svg drawings/plot-20 1.svg | PLAN_VIEW | 1/100 | 1:100 | 161.634 | 30 | plot-20 1
plot-20 2 | drawings/plot-20 2.svg drawings/plot-20 2.svg | PLAN_VIEW | 1/100 | 1:100 | 293.267 | 30 | plot-20 2
Building plot-20 NORTH | drawings/Building plot-20 NORTH.svg drawings/Building plot-20 NORTH.svg | ELEVATION_VIEW | 1/100 | 1:100 | 30 | 184.687 | Building plot-20 NORTH | IfcTypeProduct, IfcProduct, location="Building plot-20"
Building plot-20 SOUTH | drawings/Building plot-20 SOUTH.svg drawings/Building plot-20 SOUTH.svg | ELEVATION_VIEW | 1/100 | 1:100 | 161.634 | 184.687 | Building plot-20 SOUTH | IfcTypeProduct, IfcProduct, location="Building plot-20"
Building plot-20 WEST | drawings/Building plot-20 WEST.svg drawings/Building plot-20 WEST.svg | ELEVATION_VIEW | 1/100 | 1:100 | 293.267 | 184.687 | Building plot-20 WEST | IfcTypeProduct, IfcProduct, location="Building plot-20"
Building plot-20 EAST | drawings/Building plot-20 EAST.svg drawings/Building plot-20 EAST.svg | ELEVATION_VIEW | 1/100 | 1:100 | 437.955 | 184.687 | Building plot-20 EAST | IfcTypeProduct, IfcProduct, location="Building plot-20"
Building plot-20 LOCATION | drawings/Building plot-20 LOCATION.svg drawings/Building plot-20 LOCATION.svg | PLAN_VIEW | 1/1000 | 1:1000 | 582.642 | 184.687 | Building plot-20 LOCATION | IfcSite + IfcRoof, IfcWall, IfcSlab, location="Building plot-20"
plot-21 0 | drawings/plot-21 0.svg drawings/plot-21 0.svg | PLAN_VIEW | 1/100 | 1:100 | 30 | 30 | plot-21 0
plot-21 1 | drawings/plot-21 1.svg drawings/plot-21 1.svg | PLAN_VIEW | 1/100 | 1:100 | 165.101 | 30 | plot-21 1
plot-21 2 | drawings/plot-21 2.svg drawings/plot-21 2.svg | PLAN_VIEW | 1/100 | 1:100 | 300.202 | 30 | plot-21 2
Building plot-21 NORTH | drawings/Building plot-21 NORTH.svg drawings/Building plot-21 NORTH.svg | ELEVATION_VIEW | 1/100 | 1:100 | 30 | 182.08 | Building plot-21 NORTH | IfcTypeProduct, IfcProduct, location="Building plot-21"
Building plot-21 SOUTH | drawings/Building plot-21 SOUTH.svg drawings/Building plot-21 SOUTH.svg | ELEVATION_VIEW | 1/100 | 1:100 | 165.101 | 182.08 | Building plot-21 SOUTH | IfcTypeProduct, IfcProduct, location="Building plot-21"
Building plot-21 WEST | drawings/Building plot-21 WEST.svg drawings/Building plot-21 WEST.svg | ELEVATION_VIEW | 1/100 | 1:100 | 300.202 | 182.08 | Building plot-21 WEST | IfcTypeProduct, IfcProduct, location="Building plot-21"
Building plot-21 EAST | drawings/Building plot-21 EAST.svg drawings/Building plot-21 EAST.svg | ELEVATION_VIEW | 1/100 | 1:100 | 442.282 | 182.08 | Building plot-21 EAST | IfcTypeProduct, IfcProduct, location="Building plot-21"
Building plot-21 LOCATION | drawings/Building plot-21 LOCATION.svg drawings/Building plot-21 LOCATION.svg | PLAN_VIEW | 1/1000 | 1:1000 | 584.362 | 182.08 | Building plot-21 LOCATION | IfcSite + IfcRoof, IfcWall, IfcSlab, location="Building plot-21"
plot-22 0 | drawings/plot-22 0.svg drawings/plot-22 0.svg | PLAN_VIEW | 1/100 | 1:100 | 30 | 30 | plot-22 0
plot-22 1 | drawings/plot-22 1.svg drawings/plot-22 1.svg | PLAN_VIEW | 1/100 | 1:100 | 155.518 | 30 | plot-22 1
plot-22 2 | drawings/plot-22 2.svg drawings/plot-22 2.svg | PLAN_VIEW | 1/100 | 1:100 | 281.037 | 30 | plot-22 2
Building plot-22 NORTH | drawings/Building plot-22 NORTH.svg drawings/Building plot-22 NORTH.svg | ELEVATION_VIEW | 1/100 | 1:100 | 30 | 171.262 | Building plot-22 NORTH | IfcTypeProduct, IfcProduct, location="Building plot-22"
Building plot-22 SOUTH | drawings/Building plot-22 SOUTH.svg drawings/Building plot-22 SOUTH.svg | ELEVATION_VIEW | 1/100 | 1:100 | 155.518 | 171.262 | Building plot-22 SOUTH | IfcTypeProduct, IfcProduct, location="Building plot-22"
Building plot-22 WEST | drawings/Building plot-22 WEST.svg drawings/Building plot-22 WEST.svg | ELEVATION_VIEW | 1/100 | 1:100 | 281.037 | 171.262 | Building plot-22 WEST | IfcTypeProduct, IfcProduct, location="Building plot-22"
Building plot-22 EAST | drawings/Building plot-22 EAST.svg drawings/Building plot-22 EAST.svg | ELEVATION_VIEW | 1/100 | 1:100 | 412.298 | 171.262 | Building plot-22 EAST | IfcTypeProduct, IfcProduct, location="Building plot-22"
Building plot-22 LOCATION | drawings/Building plot-22 LOCATION.svg drawings/Building plot-22 LOCATION.svg | PLAN_VIEW | 1/1000 | 1:1000 | 543.56 | 171.262 | Building plot-22 LOCATION | IfcSite + IfcRoof, IfcWall, IfcSlab, location="Building plot-22"
plot-23 0 | drawings/plot-23 0.svg drawings/plot-23 0.svg | PLAN_VIEW | 1/100 | 1:100 | 30 | 30 | plot-23 0
plot-23 1 | drawings/plot-23 1.svg drawings/plot-23 1.svg | PLAN_VIEW | 1/100 | 1:100 | 171.25 | 30 | plot-23 1
plot-23 2 | drawings/plot-23 2.svg drawings/plot-23 2.svg | PLAN_VIEW | 1/100 | 1:100 | 312.5 | 30 | plot-23 2
Building plot-23 NORTH | drawings/Building plot-23 NORTH.svg drawings/Building plot-23 NORTH.svg | ELEVATION_VIEW | 1/100 | 1:100 | 30 | 184.692 | Building plot-23 NORTH | IfcTypeProduct, IfcProduct, location="Building plot-23"
Building plot-23 SOUTH | drawings/Building plot-23 SOUTH.svg drawings/Building plot-23 SOUTH.svg | ELEVATION_VIEW | 1/100 | 1:100 | 171.25 | 184.692 | Building plot-23 SOUTH | IfcTypeProduct, IfcProduct, location="Building plot-23"
Building plot-23 WEST | drawings/Building plot-23 WEST.svg drawings/Building plot-23 WEST.svg | ELEVATION_VIEW | 1/100 | 1:100 | 312.5 | 184.692 | Building plot-23 WEST | IfcTypeProduct, IfcProduct, location="Building plot-23"
Building plot-23 EAST | drawings/Building plot-23 EAST.svg drawings/Building plot-23 EAST.svg | ELEVATION_VIEW | 1/100 | 1:100 | 457.192 | 184.692 | Building plot-23 EAST | IfcTypeProduct, IfcProduct, location="Building plot-23"
Building plot-23 LOCATION | drawings/Building plot-23 LOCATION.svg drawings/Building plot-23 LOCATION.svg | PLAN_VIEW | 1/1000 | 1:1000 | 601.884 | 184.692 | Building plot-23 LOCATION | IfcSite + IfcRoof, IfcWall, IfcSlab, location="Building plot-23"
plot-24 0 | drawings/plot-24 0.svg drawings/plot-24 0.svg | PLAN_VIEW | 1/100 | 1:100 | 30 | 30 | plot-24 0
plot-24 1 | drawings/plot-24 1.svg drawings/plot-24 1.svg | PLAN_VIEW | 1/100 | 1:100 | 144.18 | 30 | plot-24 1
plot-24 2 | drawings/plot-24 2.svg drawings/plot-24 2.svg | PLAN_VIEW | 1/100 | 1:100 | 258.361 | 30 | plot-24 2
Building plot-24 NORTH | drawings/Building plot-24 NORTH.svg drawings/Building plot-24 NORTH.svg | ELEVATION_VIEW | 1/100 | 1:100 | 30 | 179.403 | Building plot-24 NORTH | IfcTypeProduct, IfcProduct, location="Building plot-24"
Building plot-24 SOUTH | drawings/Building plot-24 SOUTH.svg drawings/Building plot-24 SOUTH.svg | ELEVATION_VIEW | 1/100 | 1:100 | 144.18 | 179.403 | Building plot-24 SOUTH | IfcTypeProduct, IfcProduct, location="Building plot-24"
Building plot-24 WEST | drawings/Building plot-24 WEST.svg drawings/Building plot-24 WEST.svg | ELEVATION_VIEW | 1/100 | 1:100 | 258.361 | 179.403 | Building plot-24 WEST | IfcTypeProduct, IfcProduct, location="Building plot-24"
Building plot-24 EAST | drawings/Building plot-24 EAST.svg drawings/Building plot-24 EAST.svg | ELEVATION_VIEW | 1/100 | 1:100 | 397.764 | 179.403 | Building plot-24 EAST | IfcTypeProduct, IfcProduct, location="Building plot-24"
Building plot-24 LOCATION | drawings/Building plot-24 LOCATION.svg drawings/Building plot-24 LOCATION.svg | PLAN_VIEW | 1/1000 | 1:1000 | 537.167 | 179.403 | Building plot-24 LOCATION | IfcSite + IfcRoof, IfcWall, IfcSlab, location="Building plot-24"
plot-25 0 | drawings/plot-25 0.svg drawings/plot-25 0.svg | PLAN_VIEW | 1/100 | 1:100 | 30 | 30 | plot-25 0
plot-25 1 | drawings/plot-25 1.svg drawings/plot-25 1.svg | PLAN_VIEW | 1/100 | 1:100 | 143.133 | 30 | plot-25 1
Building plot-25 NORTH | drawings/Building plot-25 NORTH.svg drawings/Building plot-25 NORTH.svg | ELEVATION_VIEW | 1/100 | 1:100 | 30 | 172.818 | Building plot-25 NORTH | IfcTypeProduct, IfcProduct, location="Building plot-25"
Building plot-25 SOUTH | drawings/Building plot-25 SOUTH.svg drawings/Building plot-25 SOUTH.svg | ELEVATION_VIEW | 1/100 | 1:100 | 143.133 | 172.818 | Building plot-25 SOUTH | IfcTypeProduct, IfcProduct, location="Building plot-25"
Building plot-25 WEST | drawings/Building plot-25 WEST.svg drawings/Building plot-25 WEST.svg | ELEVATION_VIEW | 1/100 | 1:100 | 256.265 | 172.818 | Building plot-25 WEST | IfcTypeProduct, IfcProduct, location="Building plot-25"
Building plot-25 EAST | drawings/Building plot-25 EAST.svg drawings/Building plot-25 EAST.svg | ELEVATION_VIEW | 1/100 | 1:100 | 389.084 | 172.818 | Building plot-25 EAST | IfcTypeProduct, IfcProduct, location="Building plot-25"
Building plot-25 LOCATION | drawings/Building plot-25 LOCATION.svg drawings/Building plot-25 LOCATION.svg | PLAN_VIEW | 1/1000 | 1:1000 | 521.902 | 172.818 | Building plot-25 LOCATION | IfcSite + IfcRoof, IfcWall, IfcSlab, location="Building plot-25"
plot-26 0 | drawings/plot-26 0.svg drawings/plot-26 0.svg | PLAN_VIEW | 1/100 | 1:100 | 30 | 30 | plot-26 0
plot-26 1 | drawings/plot-26 1.svg drawings/plot-26 1.svg | PLAN_VIEW | 1/100 | 1:100 | 141.775 | 30 | plot-26 1
plot-26 2 | drawings/plot-26 2.svg drawings/plot-26 2.svg | PLAN_VIEW | 1/100 | 1:100 | 253.549 | 30 | plot-26 2
Building plot-26 NORTH | drawings/Building plot-26 NORTH.svg drawings/Building plot-26 NORTH.svg | ELEVATION_VIEW | 1/100 | 1:100 | 30 | 173.583 | Building plot-26 NORTH | IfcTypeProduct, IfcProduct, location="Building plot-26"
Building plot-26 SOUTH | drawings/Building plot-26 SOUTH.svg drawings/Building plot-26 SOUTH.svg | ELEVATION_VIEW | 1/100 | 1:100 | 141.775 | 173.583 | Building plot-26 SOUTH | IfcTypeProduct, IfcProduct, location="Building plot-26"
Building plot-26 WEST | drawings/Building plot-26 WEST.svg drawings/Building plot-26 WEST.svg | ELEVATION_VIEW | 1/100 | 1:100 | 253.549 | 173.583 | Building plot-26 WEST | IfcTypeProduct, IfcProduct, location="Building plot-26"
Building plot-26 EAST | drawings/Building plot-26 EAST.svg drawings/Building plot-26 EAST.svg | ELEVATION_VIEW | 1/100 | 1:100 | 387.132 | 173.583 | Building plot-26 EAST | IfcTypeProduct, IfcProduct, location="Building plot-26"
Building plot-26 LOCATION | drawings/Building plot-26 LOCATION.svg drawings/Building plot-26 LOCATION.svg | PLAN_VIEW | 1/1000 | 1:1000 | 520.716 | 173.583 | Building plot-26 LOCATION | IfcSite + IfcRoof, IfcWall, IfcSlab, location="Building plot-26"
plot-27 0 | drawings/plot-27 0.svg drawings/plot-27 0.svg | PLAN_VIEW | 1/100 | 1:100 | 30 | 30 | plot-27 0
plot-27 1 | drawings/plot-27 1.svg drawings/plot-27 1.svg | PLAN_VIEW | 1/100 | 1:100 | 157.835 | 30 | plot-27 1
plot-27 2 | drawings/plot-27 2.svg drawings/plot-27 2.svg | PLAN_VIEW | 1/100 | 1:100 | 285.671 | 30 | plot-27 2
Building plot-27 NORTH | drawings/Building plot-27 NORTH.svg drawings/Building plot-27 NORTH.svg | ELEVATION_VIEW | 1/100 | 1:100 | 30 | 148.146 | Building plot-27 NORTH | IfcTypeProduct, IfcProduct, location="Building plot-27"
Building plot-27 SOUTH | drawings/Building plot-27 SOUTH.svg drawings/Building plot-27 SOUTH.svg | ELEVATION_VIEW | 1/100 | 1:100 | 157.835 | 148.146 | Building plot-27 SOUTH | IfcTypeProduct, IfcProduct, location="Building plot-27"
Building plot-27 WEST | drawings/Building plot-27 WEST.svg drawings/Building plot-27 WEST.svg | ELEVATION_VIEW | 1/100 | 1:100 | 285.671 | 148.146 | Building plot-27 WEST | IfcTypeProduct, IfcProduct, location="Building plot-27"
Building plot-27 EAST | drawings/Building plot-27 EAST.svg drawings/Building plot-27 EAST.svg | ELEVATION_VIEW | 1/100 | 1:100 | 393.817 | 148.146 | Building plot-27 EAST | IfcTypeProduct, IfcProduct, location="Building plot-27"
Building plot-27 LOCATION | drawings/Building plot-27 LOCATION.svg drawings/Building plot-27 LOCATION.svg | PLAN_VIEW | 1/1000 | 1:1000 | 501.962 | 148.146 | Building plot-27 LOCATION | IfcSite + IfcRoof, IfcWall, IfcSlab, location="Building plot-27"
plot-28 0 | drawings/plot-28 0.svg drawings/plot-28 0.svg | PLAN_VIEW | 1/100 | 1:100 | 30 | 30 | plot-28 0
plot-28 1 | drawings/plot-28 1.svg drawings/plot-28 1.svg | PLAN_VIEW | 1/100 | 1:100 | 178.288 | 30 | plot-28 1
plot-28 2 | drawings/plot-28 2.svg drawings/plot-28 2.svg | PLAN_VIEW | 1/100 | 1:100 | 326.577 | 30 | plot-28 2
Building plot-28 NORTH | drawings/Building plot-28 NORTH.svg drawings/Building plot-28 NORTH.svg | ELEVATION_VIEW | 1/100 | 1:100 | 30 | 174.547 | Building plot-28 NORTH | IfcTypeProduct, IfcProduct, location="Building plot-28"
Building plot-28 SOUTH | drawings/Building plot-28 SOUTH.svg drawings/Building plot-28 SOUTH.svg | ELEVATION_VIEW | 1/100 | 1:100 | 178.288 | 174.547 | Building plot-28 SOUTH | IfcTypeProduct, IfcProduct, location="Building plot-28"
Building plot-28 WEST | drawings/Building plot-28 WEST.svg drawings/Building plot-28 WEST.svg | ELEVATION_VIEW | 1/100 | 1:100 | 326.577 | 174.547 | Building plot-28 WEST | IfcTypeProduct, IfcProduct, location="Building plot-28"
Building plot-28 EAST | drawings/Building plot-28 EAST.svg drawings/Building plot-28 EAST.svg | ELEVATION_VIEW | 1/100 | 1:100 | 461.124 | 174.547 | Building plot-28 EAST | IfcTypeProduct, IfcProduct, location="Building plot-28"
Building plot-28 LOCATION | drawings/Building plot-28 LOCATION.svg drawings/Building plot-28 LOCATION.svg | PLAN_VIEW | 1/1000 | 1:1000 | 595.671 | 174.547 | Building plot-28 LOCATION | IfcSite + IfcRoof, IfcWall, IfcSlab, location="Building plot-28"
plot-29 0 | drawings/plot-29 0.svg drawings/plot-29 0.svg | PLAN_VIEW | 1/100 | 1:100 | 30 | 30 | plot-29 0
plot-29 1 | drawings/plot-29 1.svg drawings/plot-29 1.svg | PLAN_VIEW | 1/100 | 1:100 | 185.56 | 30 | plot-29 1
plot-29 2 | drawings/plot-29 2.svg drawings/plot-29 2.svg | PLAN_VIEW | 1/100 | 1:100 | 341.119 | 30 | plot-29 2
Building plot-29 NORTH | drawings/Building plot-29 NORTH.svg drawings/Building plot-29 NORTH.svg | ELEVATION_VIEW | 1/100 | 1:100 | 30 | 168.58 | Building plot-29 NORTH | IfcTypeProduct, IfcProduct, location="Building plot-29"
Building plot-29 SOUTH | drawings/Building plot-29 SOUTH.svg drawings/Building plot-29 SOUTH.svg | ELEVATION_VIEW | 1/100 | 1:100 | 185.56 | 168.58 | Building plot-29 SOUTH | IfcTypeProduct, IfcProduct, location="Building plot-29"
Building plot-29 WEST | drawings/Building plot-29 WEST.svg drawings/Building plot-29 WEST.svg | ELEVATION_VIEW | 1/100 | 1:100 | 341.119 | 168.58 | Building plot-29 WEST | IfcTypeProduct, IfcProduct, location="Building plot-29"
Building plot-29 EAST | drawings/Building plot-29 EAST.svg drawings/Building plot-29 EAST.svg | ELEVATION_VIEW | 1/100 | 1:100 | 469.7 | 168.58 | Building plot-29 EAST | IfcTypeProduct, IfcProduct, location="Building plot-29"
Building plot-29 LOCATION | drawings/Building plot-29 LOCATION.svg drawings/Building plot-29 LOCATION.svg | PLAN_VIEW | 1/1000 | 1:1000 | 598.28 | 168.58 | Building plot-29 LOCATION | IfcSite + IfcRoof, IfcWall, IfcSlab, location="Building plot-29"
plot-30 0 | drawings/plot-30 0.svg drawings/plot-30 0.svg | PLAN_VIEW | 1/100 | 1:100 | 30 | 30 | plot-30 0
plot-30 1 | drawings/plot-30 1.svg drawings/plot-30 1.svg | PLAN_VIEW | 1/100 | 1:100 | 197.813 | 30 | plot-30 1
plot-30 2 | drawings/plot-30 2.svg drawings/plot-30 2.svg | PLAN_VIEW | 1/100 | 1:100 | 365.625 | 30 | plot-30 2
Building plot-30 NORTH | drawings/Building plot-30 NORTH.svg drawings/Building plot-30 NORTH.svg | ELEVATION_VIEW | 1/100 | 1:100 | 30 | 169.283 | Building plot-30 NORTH | IfcTypeProduct, IfcProduct, location="Building plot-30"
Building plot-30 SOUTH | drawings/Building plot-30 SOUTH.svg drawings/Building plot-30 SOUTH.svg | ELEVATION_VIEW | 1/100 | 1:100 | 197.813 | 169.283 | Building plot-30 SOUTH | IfcTypeProduct, IfcProduct, location="Building plot-30"
Building plot-30 WEST | drawings/Building plot-30 WEST.svg drawings/Building plot-30 WEST.svg | ELEVATION_VIEW | 1/100 | 1:100 | 365.625 | 169.283 | Building plot-30 WEST | IfcTypeProduct, IfcProduct, location="Building plot-30"
Building plot-30 EAST | drawings/Building plot-30 EAST.svg drawings/Building plot-30 EAST.svg | ELEVATION_VIEW | 1/100 | 1:100 | 494.908 | 169.283 | Building plot-30 EAST | IfcTypeProduct, IfcProduct, location="Building plot-30"
Building plot-30 LOCATION | drawings/Building plot-30 LOCATION.svg drawings/Building plot-30 LOCATION.svg | PLAN_VIEW | 1/1000 | 1:1000 | 624.191 | 169.283 | Building plot-30 LOCATION | IfcSite + IfcRoof, IfcWall, IfcSlab, location="Building plot-30"
plot-31 0 | drawings/plot-31 0.svg drawings/plot-31 0.svg | PLAN_VIEW | 1/100 | 1:100 | 30 | 30 | plot-31 0
plot-31 1 | drawings/plot-31 1.svg drawings/plot-31 1.svg | PLAN_VIEW | 1/100 | 1:100 | 153.862 | 30 | plot-31 1
plot-31 2 | drawings/plot-31 2.svg drawings/plot-31 2.svg | PLAN_VIEW | 1/100 | 1:100 | 277.724 | 30 | plot-31 2
Building plot-31 NORTH | drawings/Building plot-31 NORTH.svg drawings/Building plot-31 NORTH.svg | ELEVATION_VIEW | 1/100 | 1:100 | 30 | 175.757 | Building plot-31 NORTH | IfcTypeProduct, IfcProduct, location="Building plot-31"
Building plot-31 SOUTH | drawings/Building plot-31 SOUTH.svg drawings/Building plot-31 SOUTH.svg | ELEVATION_VIEW | 1/100 | 1:100 | 153.862 | 175.757 | Building plot-31 SOUTH | IfcTypeProduct, IfcProduct, location="Building plot-31"
Building plot-31 WEST | drawings/Building plot-31 WEST.svg drawings/Building plot-31 WEST.svg | ELEVATION_VIEW | 1/100 | 1:100 | 277.724 | 175.757 | Building plot-31 WEST | IfcTypeProduct, IfcProduct, location="Building plot-31"
Building plot-31 EAST | drawings/Building plot-31 EAST.svg drawings/Building plot-31 EAST.svg | ELEVATION_VIEW | 1/100 | 1:100 | 413.481 | 175.757 | Building plot-31 EAST | IfcTypeProduct, IfcProduct, location="Building plot-31"
Building plot-31 LOCATION | drawings/Building plot-31 LOCATION.svg drawings/Building plot-31 LOCATION.svg | PLAN_VIEW | 1/1000 | 1:1000 | 549.238 | 175.757 | Building plot-31 LOCATION | IfcSite + IfcRoof, IfcWall, IfcSlab, location="Building plot-31"

# IfcAnnotation: ELEVATION (1369)
Name | Group
IfcAnnotation/Building plot-0 NORTH | Building plot-1 LOCATION
IfcAnnotation/Building plot-0 SOUTH | Building plot-1 LOCATION
IfcAnnotation/Building plot-0 NORTH | Building plot-10 LOCATION
IfcAnnotation/Building plot-0 SOUTH | Building plot-10 LOCATION
IfcAnnotation/Building plot-0 NORTH | Building plot-11 LOCATION
IfcAnnotation/Building plot-0 SOUTH | Building plot-11 LOCATION
IfcAnnotation/Building plot-0 NORTH | Building plot-12 LOCATION
IfcAnnotation/Building plot-0 SOUTH | Building plot-12 LOCATION
IfcAnnotation/Building plot-0 NORTH | Building plot-13 LOCATION
IfcAnnotation/Building plot-0 SOUTH | Building plot-13 LOCATION
IfcAnnotation/Building plot-0 NORTH | Building plot-14 LOCATION
IfcAnnotation/Building plot-0 SOUTH | Building plot-14 LOCATION
IfcAnnotation/Building plot-0 NORTH | Building plot-15 LOCATION
IfcAnnotation/Building plot-0 SOUTH | Building plot-15 LOCATION
IfcAnnotation/Building plot-0 NORTH | Building plot-16 LOCATION
IfcAnnotation/Building plot-0 SOUTH | Building plot-16 LOCATION
IfcAnnotation/Building plot-0 NORTH | Building plot-17 LOCATION
IfcAnnotation/Building plot-0 SOUTH | Building plot-17 LOCATION
IfcAnnotation/Building plot-0 NORTH | Building plot-18 LOCATION
IfcAnnotation/Building plot-0 SOUTH | Building plot-18 LOCATION
IfcAnnotation/Building plot-0 NORTH | Building plot-19 LOCATION
IfcAnnotation/Building plot-0 SOUTH | Building plot-19 LOCATION
IfcAnnotation/Building plot-0 NORTH | Building plot-2 LOCATION
IfcAnnotation/Building plot-0 SOUTH | Building plot-2 LOCATION
IfcAnnotation/Building plot-0 NORTH | Building plot-20 LOCATION
IfcAnnotation/Building plot-0 SOUTH | Building plot-20 LOCATION
IfcAnnotation/Building plot-0 NORTH | Building plot-21 LOCATION
IfcAnnotation/Building plot-0 SOUTH | Building plot-21 LOCATION
IfcAnnotation/Building plot-0 NORTH | Building plot-22 LOCATION
IfcAnnotation/Building plot-0 SOUTH | Building plot-22 LOCATION
IfcAnnotation/Building plot-0 NORTH | Building plot-23 LOCATION
IfcAnnotation/Building plot-0 SOUTH | Building plot-23 LOCATION
IfcAnnotation/Building plot-0 NORTH | Building plot-24 LOCATION
IfcAnnotation/Building plot-0 SOUTH | Building plot-24 LOCATION
IfcAnnotation/Building plot-0 NORTH | Building plot-25 LOCATION
IfcAnnotation/Building plot-0 SOUTH | Building plot-25 LOCATION
IfcAnnotation/Building plot-0 NORTH | Building plot-26 LOCATION
IfcAnnotation/Building plot-0 SOUTH | Building plot-26 LOCATION
IfcAnnotation/Building plot-0 NORTH | Building plot-27 LOCATION
IfcAnnotation/Building plot-0 SOUTH | Building plot-27 LOCATION
IfcAnnotation/Building plot-0 NORTH | Building plot-28 LOCATION
IfcAnnotation/Building plot-0 SOUTH | Building plot-28 LOCATION
IfcAnnotation/Building plot-0 NORTH | Building plot-29 LOCATION
IfcAnnotation/Building plot-0 SOUTH | Building plot-29 LOCATION
IfcAnnotation/Building plot-0 NORTH | Building plot-3 LOCATION
IfcAnnotation/Building plot-0 SOUTH | Building plot-3 LOCATION
IfcAnnotation/Building plot-0 NORTH | Building plot-30 LOCATION
IfcAnnotation/Building plot-0 SOUTH | Building plot-30 LOCATION
IfcAnnotation/Building plot-0 NORTH | Building plot-31 LOCATION
IfcAnnotation/Building plot-0 SOUTH | Building plot-31 LOCATION
IfcAnnotation/Building plot-0 NORTH | Building plot-4 LOCATION
IfcAnnotation/Building plot-0 SOUTH | Building plot-4 LOCATION
IfcAnnotation/Building plot-0 NORTH | Building plot-5 LOCATION
IfcAnnotation/Building plot-0 SOUTH | Building plot-5 LOCATION
IfcAnnotation/Building plot-0 NORTH | Building plot-6 LOCATION
IfcAnnotation/Building plot-0 SOUTH | Building plot-6 LOCATION
IfcAnnotation/Building plot-0 NORTH | Building plot-7 LOCATION
IfcAnnotation/Building plot-0 SOUTH | Building plot-7 LOCATION
IfcAnnotation/Building plot-0 NORTH | Building plot-8 LOCATION
IfcAnnotation/Building plot-0 SOUTH | Building plot-8 LOCATION
IfcAnnotation/Building plot-0 NORTH | Building plot-9 LOCATION
IfcAnnotation/Building plot-0 SOUTH | Building plot-9 LOCATION
IfcAnnotation/Building plot-0 NORTH | plot-0 0
IfcAnnotation/Building plot-0 SOUTH | plot-0 0
IfcAnnotation/Building plot-0 WEST | plot-0 0
IfcAnnotation/Building plot-0 EAST | plot-0 0
IfcAnnotation/Building plot-0 NORTH | plot-0 1
IfcAnnotation/Building plot-0 SOUTH | plot-0 1
IfcAnnotation/Building plot-0 WEST | plot-0 1
IfcAnnotation/Building plot-0 EAST | plot-0 1
IfcAnnotation/Building plot-1 NORTH | plot-0 1
IfcAnnotation/Building plot-1 SOUTH | plot-0 1
IfcAnnotation/Building plot-1 WEST | plot-0 1
IfcAnnotation/Building plot-1 EAST | plot-0 1
IfcAnnotation/Building plot-0 NORTH | plot-0 2
IfcAnnotation/Building plot-0 SOUTH | plot-0 2
IfcAnnotation/Building plot-0 EAST | plot-0 2
IfcAnnotation/Building plot-1 NORTH | plot-0 2
IfcAnnotation/Building plot-1 SOUTH | plot-0 2
IfcAnnotation/Building plot-1 WEST | plot-0 2
IfcAnnotation/Building plot-1 EAST | plot-0 2
IfcAnnotation/Building plot-0 NORTH | plot-1 0
IfcAnnotation/Building plot-0 SOUTH | plot-1 0
IfcAnnotation/Building plot-0 WEST | plot-1 0
IfcAnnotation/Building plot-0 EAST | plot-1 0
IfcAnnotation/Building plot-2 NORTH | plot-1 0
IfcAnnotation/Building plot-2 SOUTH | plot-1 0
IfcAnnotation/Building plot-2 WEST | plot-1 0
IfcAnnotation/Building plot-2 EAST | plot-1 0
IfcAnnotation/Building plot-3 NORTH | plot-1 0
IfcAnnotation/Building plot-3 SOUTH | plot-1 0
IfcAnnotation/Building plot-0 NORTH | plot-1 1
IfcAnnotation/Building plot-0 SOUTH | plot-1 1
IfcAnnotation/Building plot-0 WEST | plot-1 1
IfcAnnotation/Building plot-0 EAST | plot-1 1
IfcAnnotation/Building plot-1 NORTH | plot-1 1
IfcAnnotation/Building plot-1 SOUTH | plot-1 1
IfcAnnotation/Building plot-1 WEST | plot-1 1
IfcAnnotation/Building plot-1 EAST | plot-1 1
IfcAnnotation/Building plot-2 NORTH | plot-1 1
IfcAnnotation/Building plot-2 SOUTH | plot-1 1
IfcAnnotation/Building plot-2 WEST | plot-1 1
IfcAnnotation/Building plot-2 EAST | plot-1 1
IfcAnnotation/Building plot-3 NORTH | plot-1 1
IfcAnnotation/Building plot-3 SOUTH | plot-1 1
IfcAnnotation/Building plot-0 NORTH | plot-1 2
IfcAnnotation/Building plot-0 SOUTH | plot-1 2
IfcAnnotation/Building plot-0 WEST | plot-1 2
IfcAnnotation/Building plot-0 EAST | plot-1 2
IfcAnnotation/Building plot-2 NORTH | plot-1 2
IfcAnnotation/Building plot-2 SOUTH | plot-1 2
IfcAnnotation/Building plot-2 WEST | plot-1 2
IfcAnnotation/Building plot-2 EAST | plot-1 2
IfcAnnotation/Building plot-3 NORTH | plot-1 2
IfcAnnotation/Building plot-3 SOUTH | plot-1 2
IfcAnnotation/Building plot-8 NORTH | plot-10 0
IfcAnnotation/Building plot-8 SOUTH | plot-10 0
IfcAnnotation/Building plot-8 WEST | plot-10 0
IfcAnnotation/Building plot-8 EAST | plot-10 0
IfcAnnotation/Building plot-9 NORTH | plot-10 0
IfcAnnotation/Building plot-9 SOUTH | plot-10 0
IfcAnnotation/Building plot-9 WEST | plot-10 0
IfcAnnotation/Building plot-9 EAST | plot-10 0
IfcAnnotation/Building plot-11 WEST | plot-10 0
IfcAnnotation/Building plot-11 EAST | plot-10 0
IfcAnnotation/Building plot-8 NORTH | plot-10 1
IfcAnnotation/Building plot-8 SOUTH | plot-10 1
IfcAnnotation/Building plot-8 WEST | plot-10 1
IfcAnnotation/Building plot-8 EAST | plot-10 1
IfcAnnotation/Building plot-9 NORTH | plot-10 1
IfcAnnotation/Building plot-9 SOUTH | plot-10 1
IfcAnnotation/Building plot-9 WEST | plot-10 1
IfcAnnotation/Building plot-9 EAST | plot-10 1
IfcAnnotation/Building plot-10 NORTH | plot-10 1
IfcAnnotation/Building plot-10 SOUTH | plot-10 1
IfcAnnotation/Building plot-10 WEST | plot-10 1
IfcAnnotation/Building plot-10 EAST | plot-10 1
IfcAnnotation/Building plot-11 WEST | plot-10 1
IfcAnnotation/Building plot-11 EAST | plot-10 1
IfcAnnotation/Building plot-8 NORTH | plot-10 2
IfcAnnotation/Building plot-8 SOUTH | plot-10 2
IfcAnnotation/Building plot-8 WEST | plot-10 2
IfcAnnotation/Building plot-8 EAST | plot-10 2
IfcAnnotation/Building plot-9 NORTH | plot-10 2
IfcAnnotation/Building plot-9 SOUTH | plot-10 2
IfcAnnotation/Building plot-9 WEST | plot-10 2
IfcAnnotation/Building plot-9 EAST | plot-10 2
IfcAnnotation/Building plot-10 NORTH | plot-10 2
IfcAnnotation/Building plot-10 SOUTH | plot-10 2
IfcAnnotation/Building plot-10 WEST | plot-10 2
IfcAnnotation/Building plot-10 EAST | plot-10 2
IfcAnnotation/Building plot-11 WEST | plot-10 2
IfcAnnotation/Building plot-11 EAST | plot-10 2
IfcAnnotation/Building plot-8 NORTH | plot-10 3
IfcAnnotation/Building plot-8 SOUTH | plot-10 3
IfcAnnotation/Building plot-8 WEST | plot-10 3
IfcAnnotation/Building plot-8 EAST | plot-10 3
IfcAnnotation/Building plot-9 NORTH | plot-10 3
IfcAnnotation/Building plot-9 SOUTH | plot-10 3
IfcAnnotation/Building plot-9 WEST | plot-10 3
IfcAnnotation/Building plot-9 EAST | plot-10 3
IfcAnnotation/Building plot-11 WEST | plot-10 3
IfcAnnotation/Building plot-11 EAST | plot-10 3
IfcAnnotation/Building plot-11 NORTH | plot-11 0
IfcAnnotation/Building plot-11 SOUTH | plot-11 0
IfcAnnotation/Building plot-11 WEST | plot-11 0
IfcAnnotation/Building plot-11 EAST | plot-11 0
IfcAnnotation/Building plot-12 NORTH | plot-11 0
IfcAnnotation/Building plot-12 SOUTH | plot-11 0
IfcAnnotation/Building plot-12 WEST | plot-11 0
IfcAnnotation/Building plot-12 EAST | plot-11 0
IfcAnnotation/Building plot-13 NORTH | plot-11 0
IfcAnnotation/Building plot-13 SOUTH | plot-11 0
IfcAnnotation/Building plot-10 WEST | plot-11 1
IfcAnnotation/Building plot-10 EAST | plot-11 1
IfcAnnotation/Building plot-11 NORTH | plot-11 1
IfcAnnotation/Building plot-11 SOUTH | plot-11 1
IfcAnnotation/Building plot-11 WEST | plot-11 1
IfcAnnotation/Building plot-11 EAST | plot-11 1
IfcAnnotation/Building plot-12 NORTH | plot-11 1
IfcAnnotation/Building plot-12 SOUTH | plot-11 1
IfcAnnotation/Building plot-12 WEST | plot-11 1
IfcAnnotation/Building plot-12 EAST | plot-11 1
IfcAnnotation/Building plot-13 NORTH | plot-11 1
IfcAnnotation/Building plot-13 SOUTH | plot-11 1
IfcAnnotation/Building plot-14 NORTH | plot-11 1
IfcAnnotation/Building plot-14 SOUTH | plot-11 1
IfcAnnotation/Building plot-14 WEST | plot-11 1
IfcAnnotation/Building plot-14 EAST | plot-11 1
IfcAnnotation/Building plot-10 WEST | plot-11 2
IfcAnnotation/Building plot-10 EAST | plot-11 2
IfcAnnotation/Building plot-12 NORTH | plot-11 2
IfcAnnotation/Building plot-12 SOUTH | plot-11 2
IfcAnnotation/Building plot-12 WEST | plot-11 2
IfcAnnotation/Building plot-12 EAST | plot-11 2
IfcAnnotation/Building plot-13 NORTH | plot-11 2
IfcAnnotation/Building plot-13 SOUTH | plot-11 2
IfcAnnotation/Building plot-14 NORTH | plot-11 2
IfcAnnotation/Building plot-14 SOUTH | plot-11 2
IfcAnnotation/Building plot-14 WEST | plot-11 2
IfcAnnotation/Building plot-14 EAST | plot-11 2
IfcAnnotation/Building plot-8 WEST | plot-12 0
IfcAnnotation/Building plot-8 EAST | plot-12 0
IfcAnnotation/Building plot-12 NORTH | plot-12 0
IfcAnnotation/Building plot-12 SOUTH | plot-12 0
IfcAnnotation/Building plot-12 WEST | plot-12 0
IfcAnnotation/Building plot-12 EAST | plot-12 0
IfcAnnotation/Building plot-13 NORTH | plot-12 0
IfcAnnotation/Building plot-13 SOUTH | plot-12 0
IfcAnnotation/Building plot-13 WEST | plot-12 0
IfcAnnotation/Building plot-13 EAST | plot-12 0
IfcAnnotation/Building plot-8 WEST | plot-12 1
IfcAnnotation/Building plot-8 EAST | plot-12 1
IfcAnnotation/Building plot-11 NORTH | plot-12 1
IfcAnnotation/Building plot-11 SOUTH | plot-12 1
IfcAnnotation/Building plot-12 NORTH | plot-12 1
IfcAnnotation/Building plot-12 SOUTH | plot-12 1
IfcAnnotation/Building plot-12 WEST | plot-12 1
IfcAnnotation/Building plot-12 EAST | plot-12 1
IfcAnnotation/Building plot-13 NORTH | plot-12 1
IfcAnnotation/Building plot-13 SOUTH | plot-12 1
IfcAnnotation/Building plot-13 WEST | plot-12 1
IfcAnnotation/Building plot-13 EAST | plot-12 1
IfcAnnotation/Building plot-8 WEST | plot-12 2
IfcAnnotation/Building plot-8 EAST | plot-12 2
IfcAnnotation/Building plot-11 NORTH | plot-12 2
IfcAnnotation/Building plot-11 SOUTH | plot-12 2
IfcAnnotation/Building plot-13 NORTH | plot-12 2
IfcAnnotation/Building plot-13 SOUTH | plot-12 2
IfcAnnotation/Building plot-13 WEST | plot-12 2
IfcAnnotation/Building plot-13 EAST | plot-12 2
IfcAnnotation/Building plot-12 NORTH | plot-13 0
IfcAnnotation/Building plot-12 SOUTH | plot-13 0
IfcAnnotation/Building plot-12 WEST | plot-13 0
IfcAnnotation/Building plot-12 EAST | plot-13 0
IfcAnnotation/Building plot-13 NORTH | plot-13 0
IfcAnnotation/Building plot-13 SOUTH | plot-13 0
IfcAnnotation/Building plot-13 WEST | plot-13 0
IfcAnnotation/Building plot-13 EAST | plot-13 0
IfcAnnotation/Building plot-11 NORTH | plot-13 1
IfcAnnotation/Building plot-11 SOUTH | plot-13 1
IfcAnnotation/Building plot-12 NORTH | plot-13 1
IfcAnnotation/Building plot-12 SOUTH | plot-13 1
IfcAnnotation/Building plot-12 WEST | plot-13 1
IfcAnnotation/Building plot-12 EAST | plot-13 1
IfcAnnotation/Building plot-13 NORTH | plot-13 1
IfcAnnotation/Building plot-13 SOUTH | plot-13 1
IfcAnnotation/Building plot-13 WEST | plot-13 1
IfcAnnotation/Building plot-13 EAST | plot-13 1
IfcAnnotation/Building plot-14 NORTH | plot-13 1
IfcAnnotation/Building plot-14 SOUTH | plot-13 1
IfcAnnotation/Building plot-14 WEST | plot-13 1
IfcAnnotation/Building plot-14 EAST | plot-13 1
IfcAnnotation/Building plot-16 WEST | plot-13 1
IfcAnnotation/Building plot-16 EAST | plot-13 1
IfcAnnotation/Building plot-11 NORTH | plot-13 2
IfcAnnotation/Building plot-11 SOUTH | plot-13 2
IfcAnnotation/Building plot-12 NORTH | plot-13 2
IfcAnnotation/Building plot-12 SOUTH | plot-13 2
IfcAnnotation/Building plot-12 WEST | plot-13 2
IfcAnnotation/Building plot-12 EAST | plot-13 2
IfcAnnotation/Building plot-14 NORTH | plot-13 2
IfcAnnotation/Building plot-14 SOUTH | plot-13 2
IfcAnnotation/Building plot-14 WEST | plot-13 2
IfcAnnotation/Building plot-14 EAST | plot-13 2
IfcAnnotation/Building plot-16 WEST | plot-13 2
IfcAnnotation/Building plot-16 EAST | plot-13 2
IfcAnnotation/Building plot-11 NORTH | plot-14 0
IfcAnnotation/Building plot-11 SOUTH | plot-14 0
IfcAnnotation/Building plot-11 WEST | plot-14 0
IfcAnnotation/Building plot-11 EAST | plot-14 0
IfcAnnotation/Building plot-13 NORTH | plot-14 0
IfcAnnotation/Building plot-13 SOUTH | plot-14 0
IfcAnnotation/Building plot-13 WEST | plot-14 0
IfcAnnotation/Building plot-13 EAST | plot-14 0
IfcAnnotation/Building plot-15 WEST | plot-14 0
IfcAnnotation/Building plot-15 EAST | plot-14 0
IfcAnnotation/Building plot-11 NORTH | plot-14 1
IfcAnnotation/Building plot-11 SOUTH | plot-14 1
IfcAnnotation/Building plot-11 WEST | plot-14 1
IfcAnnotation/Building plot-11 EAST | plot-14 1
IfcAnnotation/Building plot-13 NORTH | plot-14 1
IfcAnnotation/Building plot-13 SOUTH | plot-14 1
IfcAnnotation/Building plot-13 WEST | plot-14 1
IfcAnnotation/Building plot-13 EAST | plot-14 1
IfcAnnotation/Building plot-14 NORTH | plot-14 1
IfcAnnotation/Building plot-14 SOUTH | plot-14 1
IfcAnnotation/Building plot-14 WEST | plot-14 1
IfcAnnotation/Building plot-14 EAST | plot-14 1
IfcAnnotation/Building plot-15 WEST | plot-14 1
IfcAnnotation/Building plot-15 EAST | plot-14 1
IfcAnnotation/Building plot-16 NORTH | plot-14 1
IfcAnnotation/Building plot-16 SOUTH | plot-14 1
IfcAnnotation/Building plot-11 NORTH | plot-14 2
IfcAnnotation/Building plot-11 SOUTH | plot-14 2
IfcAnnotation/Building plot-11 WEST | plot-14 2
IfcAnnotation/Building plot-11 EAST | plot-14 2
IfcAnnotation/Building plot-13 NORTH | plot-14 2
IfcAnnotation/Building plot-13 SOUTH | plot-14 2
IfcAnnotation/Building plot-13 WEST | plot-14 2
IfcAnnotation/Building plot-13 EAST | plot-14 2
IfcAnnotation/Building plot-14 NORTH | plot-14 2
IfcAnnotation/Building plot-14 SOUTH | plot-14 2
IfcAnnotation/Building plot-14 WEST | plot-14 2
IfcAnnotation/Building plot-14 EAST | plot-14 2
IfcAnnotation/Building plot-15 WEST | plot-14 2
IfcAnnotation/Building plot-15 EAST | plot-14 2
IfcAnnotation/Building plot-16 NORTH | plot-14 2
IfcAnnotation/Building plot-16 SOUTH | plot-14 2
IfcAnnotation/Building plot-11 NORTH | plot-14 3
IfcAnnotation/Building plot-11 SOUTH | plot-14 3
IfcAnnotation/Building plot-11 WEST | plot-14 3
IfcAnnotation/Building plot-11 EAST | plot-14 3
IfcAnnotation/Building plot-13 NORTH | plot-14 3
IfcAnnotation/Building plot-13 SOUTH | plot-14 3
IfcAnnotation/Building plot-13 WEST | plot-14 3
IfcAnnotation/Building plot-13 EAST | plot-14 3
IfcAnnotation/Building plot-15 WEST | plot-14 3
IfcAnnotation/Building plot-15 EAST | plot-14 3
IfcAnnotation/Building plot-16 NORTH | plot-14 3
IfcAnnotation/Building plot-16 SOUTH | plot-14 3
IfcAnnotation/Building plot-15 NORTH | plot-15 0
IfcAnnotation/Building plot-15 SOUTH | plot-15 0
IfcAnnotation/Building plot-15 WEST | plot-15 0
IfcAnnotation/Building plot-15 EAST | plot-15 0
IfcAnnotation/Building plot-14 WEST | plot-15 1
IfcAnnotation/Building plot-14 EAST | plot-15 1
IfcAnnotation/Building plot-15 NORTH | plot-15 1
IfcAnnotation/Building plot-15 SOUTH | plot-15 1
IfcAnnotation/Building plot-15 WEST | plot-15 1
IfcAnnotation/Building plot-15 EAST | plot-15 1
IfcAnnotation/Building plot-16 NORTH | plot-15 1
IfcAnnotation/Building plot-16 SOUTH | plot-15 1
IfcAnnotation/Building plot-16 WEST | plot-15 1
IfcAnnotation/Building plot-16 EAST | plot-15 1
IfcAnnotation/Building plot-17 NORTH | plot-15 1
IfcAnnotation/Building plot-17 SOUTH | plot-15 1
IfcAnnotation/Building plot-17 WEST | plot-15 1
IfcAnnotation/Building plot-17 EAST | plot-15 1
IfcAnnotation/Building plot-18 NORTH | plot-15 1
IfcAnnotation/Building plot-18 SOUTH | plot-15 1
IfcAnnotation/Building plot-14 WEST | plot-15 2
IfcAnnotation/Building plot-14 EAST | plot-15 2
IfcAnnotation/Building plot-16 NORTH | plot-15 2
IfcAnnotation/Building plot-16 SOUTH | plot-15 2
IfcAnnotation/Building plot-16 WEST | plot-15 2
IfcAnnotation/Building plot-16 EAST | plot-15 2
IfcAnnotation/Building plot-17 NORTH | plot-15 2
IfcAnnotation/Building plot-17 SOUTH | plot-15 2
IfcAnnotation/Building plot-17 WEST | plot-15 2
IfcAnnotation/Building plot-17 EAST | plot-15 2
IfcAnnotation/Building plot-18 NORTH | plot-15 2
IfcAnnotation/Building plot-18 SOUTH | plot-15 2
IfcAnnotation/Building plot-13 WEST | plot-16 0
IfcAnnotation/Building plot-13 EAST | plot-16 0
IfcAnnotation/Building plot-13 WEST | plot-16 1
IfcAnnotation/Building plot-13 EAST | plot-16 1
IfcAnnotation/Building plot-14 NORTH | plot-16 1
IfcAnnotation/Building plot-14 SOUTH | plot-16 1
IfcAnnotation/Building plot-15 NORTH | plot-16 1
IfcAnnotation/Building plot-15 SOUTH | plot-16 1
IfcAnnotation/Building plot-15 WEST | plot-16 1
IfcAnnotation/Building plot-15 EAST | plot-16 1
IfcAnnotation/Building plot-16 NORTH | plot-16 1
IfcAnnotation/Building plot-16 SOUTH | plot-16 1
IfcAnnotation/Building plot-16 WEST | plot-16 1
IfcAnnotation/Building plot-16 EAST | plot-16 1
IfcAnnotation/Building plot-17 WEST | plot-16 1
IfcAnnotation/Building plot-17 EAST | plot-16 1
IfcAnnotation/Building plot-18 NORTH | plot-16 1
IfcAnnotation/Building plot-18 SOUTH | plot-16 1
IfcAnnotation/Building plot-18 WEST | plot-16 1
IfcAnnotation/Building plot-18 EAST | plot-16 1
IfcAnnotation/Building plot-13 WEST | plot-16 2
IfcAnnotation/Building plot-13 EAST | plot-16 2
IfcAnnotation/Building plot-14 NORTH | plot-16 2
IfcAnnotation/Building plot-14 SOUTH | plot-16 2
IfcAnnotation/Building plot-15 NORTH | plot-16 2
IfcAnnotation/Building plot-15 SOUTH | plot-16 2
IfcAnnotation/Building plot-15 WEST | plot-16 2
IfcAnnotation/Building plot-15 EAST | plot-16 2
IfcAnnotation/Building plot-16 NORTH | plot-16 2
IfcAnnotation/Building plot-16 SOUTH | plot-16 2
IfcAnnotation/Building plot-16 WEST | plot-16 2
IfcAnnotation/Building plot-16 EAST | plot-16 2
IfcAnnotation/Building plot-17 WEST | plot-16 2
IfcAnnotation/Building plot-17 EAST | plot-16 2
IfcAnnotation/Building plot-18 NORTH | plot-16 2
IfcAnnotation/Building plot-18 SOUTH | plot-16 2
IfcAnnotation/Building plot-18 WEST | plot-16 2
IfcAnnotation/Building plot-18 EAST | plot-16 2
IfcAnnotation/Building plot-13 WEST | plot-16 3
IfcAnnotation/Building plot-13 EAST | plot-16 3
IfcAnnotation/Building plot-14 NORTH | plot-16 3
IfcAnnotation/Building plot-14 SOUTH | plot-16 3
IfcAnnotation/Building plot-15 NORTH | plot-16 3
IfcAnnotation/Building plot-15 SOUTH | plot-16 3
IfcAnnotation/Building plot-15 WEST | plot-16 3
IfcAnnotation/Building plot-15 EAST | plot-16 3
IfcAnnotation/Building plot-17 WEST | plot-16 3
IfcAnnotation/Building plot-17 EAST | plot-16 3
IfcAnnotation/Building plot-18 NORTH | plot-16 3
IfcAnnotation/Building plot-18 SOUTH | plot-16 3
IfcAnnotation/Building plot-18 WEST | plot-16 3
IfcAnnotation/Building plot-18 EAST | plot-16 3
IfcAnnotation/Building plot-15 NORTH | plot-17 0
IfcAnnotation/Building plot-15 SOUTH | plot-17 0
IfcAnnotation/Building plot-15 WEST | plot-17 0
IfcAnnotation/Building plot-15 EAST | plot-17 0
IfcAnnotation/Building plot-19 WEST | plot-17 0
IfcAnnotation/Building plot-19 EAST | plot-17 0
IfcAnnotation/Building plot-15 NORTH | plot-17 1
IfcAnnotation/Building plot-15 SOUTH | plot-17 1
IfcAnnotation/Building plot-15 WEST | plot-17 1
IfcAnnotation/Building plot-15 EAST | plot-17 1
IfcAnnotation/Building plot-16 WEST | plot-17 1
IfcAnnotation/Building plot-16 EAST | plot-17 1
IfcAnnotation/Building plot-17 NORTH | plot-17 1
IfcAnnotation/Building plot-17 SOUTH | plot-17 1
IfcAnnotation/Building plot-17 WEST | plot-17 1
IfcAnnotation/Building plot-17 EAST | plot-17 1
IfcAnnotation/Building plot-18 NORTH | plot-17 1
IfcAnnotation/Building plot-18 SOUTH | plot-17 1
IfcAnnotation/Building plot-19 WEST | plot-17 1
IfcAnnotation/Building plot-19 EAST | plot-17 1
IfcAnnotation/Building plot-15 NORTH | plot-17 2
IfcAnnotation/Building plot-15 SOUTH | plot-17 2
IfcAnnotation/Building plot-15 WEST | plot-17 2
IfcAnnotation/Building plot-15 EAST | plot-17 2
IfcAnnotation/Building plot-16 WEST | plot-17 2
IfcAnnotation/Building plot-16 EAST | plot-17 2
IfcAnnotation/Building plot-18 NORTH | plot-17 2
IfcAnnotation/Building plot-18 SOUTH | plot-17 2
IfcAnnotation/Building plot-19 WEST | plot-17 2
IfcAnnotation/Building plot-19 EAST | plot-17 2
IfcAnnotation/Building plot-20 WEST | plot-18 0
IfcAnnotation/Building plot-20 EAST | plot-18 0
IfcAnnotation/Building plot-15 NORTH | plot-18 1
IfcAnnotation/Building plot-15 SOUTH | plot-18 1
IfcAnnotation/Building plot-16 NORTH | plot-18 1
IfcAnnotation/Building plot-16 SOUTH | plot-18 1
IfcAnnotation/Building plot-16 WEST | plot-18 1
IfcAnnotation/Building plot-16 EAST | plot-18 1
IfcAnnotation/Building plot-17 NORTH | plot-18 1
IfcAnnotation/Building plot-17 SOUTH | plot-18 1
IfcAnnotation/Building plot-17 WEST | plot-18 1
IfcAnnotation/Building plot-17 EAST | plot-18 1
IfcAnnotation/Building plot-18 NORTH | plot-18 1
IfcAnnotation/Building plot-18 SOUTH | plot-18 1
IfcAnnotation/Building plot-18 WEST | plot-18 1
IfcAnnotation/Building plot-18 EAST | plot-18 1
IfcAnnotation/Building plot-20 WEST | plot-18 1
IfcAnnotation/Building plot-20 EAST | plot-18 1
IfcAnnotation/Building plot-15 NORTH | plot-18 2
IfcAnnotation/Building plot-15 SOUTH | plot-18 2
IfcAnnotation/Building plot-16 NORTH | plot-18 2
IfcAnnotation/Building plot-16 SOUTH | plot-18 2
IfcAnnotation/Building plot-16 WEST | plot-18 2
IfcAnnotation/Building plot-16 EAST | plot-18 2
IfcAnnotation/Building plot-17 NORTH | plot-18 2
IfcAnnotation/Building plot-17 SOUTH | plot-18 2
IfcAnnotation/Building plot-17 WEST | plot-18 2
IfcAnnotation/Building plot-17 EAST | plot-18 2
IfcAnnotation/Building plot-18 NORTH | plot-18 2
IfcAnnotation/Building plot-18 SOUTH | plot-18 2
IfcAnnotation/Building plot-18 WEST | plot-18 2
IfcAnnotation/Building plot-18 EAST | plot-18 2
IfcAnnotation/Building plot-20 WEST | plot-18 2
IfcAnnotation/Building plot-20 EAST | plot-18 2
IfcAnnotation/Building plot-15 NORTH | plot-18 3
IfcAnnotation/Building plot-15 SOUTH | plot-18 3
IfcAnnotation/Building plot-16 NORTH | plot-18 3
IfcAnnotation/Building plot-16 SOUTH | plot-18 3
IfcAnnotation/Building plot-16 WEST | plot-18 3
IfcAnnotation/Building plot-16 EAST | plot-18 3
IfcAnnotation/Building plot-17 NORTH | plot-18 3
IfcAnnotation/Building plot-17 SOUTH | plot-18 3
IfcAnnotation/Building plot-17 WEST | plot-18 3
IfcAnnotation/Building plot-17 EAST | plot-18 3
IfcAnnotation/Building plot-20 WEST | plot-18 3
IfcAnnotation/Building plot-20 EAST | plot-18 3
IfcAnnotation/Building plot-19 NORTH | plot-19 0
IfcAnnotation/Building plot-19 SOUTH | plot-19 0
IfcAnnotation/Building plot-19 WEST | plot-19 0
IfcAnnotation/Building plot-19 EAST | plot-19 0
IfcAnnotation/Building plot-20 NORTH | plot-19 0
IfcAnnotation/Building plot-20 SOUTH | plot-19 0
IfcAnnotation/Building plot-20 WEST | plot-19 0
IfcAnnotation/Building plot-20 EAST | plot-19 0
IfcAnnotation/Building plot-17 WEST | plot-19 1
IfcAnnotation/Building plot-17 EAST | plot-19 1
IfcAnnotation/Building plot-19 NORTH | plot-19 1
IfcAnnotation/Building plot-19 SOUTH | plot-19 1
IfcAnnotation/Building plot-19 WEST | plot-19 1
IfcAnnotation/Building plot-19 EAST | plot-19 1
IfcAnnotation/Building plot-20 NORTH | plot-19 1
IfcAnnotation/Building plot-20 SOUTH | plot-19 1
IfcAnnotation/Building plot-20 WEST | plot-19 1
IfcAnnotation/Building plot-20 EAST | plot-19 1
IfcAnnotation/Building plot-2 NORTH | plot-2 0
IfcAnnotation/Building plot-2 SOUTH | plot-2 0
IfcAnnotation/Building plot-2 WEST | plot-2 0
IfcAnnotation/Building plot-2 EAST | plot-2 0
IfcAnnotation/Building plot-6 NORTH | plot-2 0
IfcAnnotation/Building plot-6 SOUTH | plot-2 0
IfcAnnotation/Building plot-7 WEST | plot-2 0
IfcAnnotation/Building plot-7 EAST | plot-2 0
IfcAnnotation/Building plot-1 NORTH | plot-2 1
IfcAnnotation/Building plot-1 SOUTH | plot-2 1
IfcAnnotation/Building plot-1 WEST | plot-2 1
IfcAnnotation/Building plot-1 EAST | plot-2 1
IfcAnnotation/Building plot-2 NORTH | plot-2 1
IfcAnnotation/Building plot-2 SOUTH | plot-2 1
IfcAnnotation/Building plot-2 WEST | plot-2 1
IfcAnnotation/Building plot-2 EAST | plot-2 1
IfcAnnotation/Building plot-6 NORTH | plot-2 1
IfcAnnotation/Building plot-6 SOUTH | plot-2 1
IfcAnnotation/Building plot-7 WEST | plot-2 1
IfcAnnotation/Building plot-7 EAST | plot-2 1
IfcAnnotation/Building plot-1 NORTH | plot-2 2
IfcAnnotation/Building plot-1 SOUTH | plot-2 2
IfcAnnotation/Building plot-1 WEST | plot-2 2
IfcAnnotation/Building plot-1 EAST | plot-2 2
IfcAnnotation/Building plot-6 NORTH | plot-2 2
IfcAnnotation/Building plot-6 SOUTH | plot-2 2
IfcAnnotation/Building plot-7 WEST | plot-2 2
IfcAnnotation/Building plot-7 EAST | plot-2 2
IfcAnnotation/Building plot-19 NORTH | plot-20 0
IfcAnnotation/Building plot-19 SOUTH | plot-20 0
IfcAnnotation/Building plot-19 WEST | plot-20 0
IfcAnnotation/Building plot-19 EAST | plot-20 0
IfcAnnotation/Building plot-20 NORTH | plot-20 0
IfcAnnotation/Building plot-20 SOUTH | plot-20 0
IfcAnnotation/Building plot-20 WEST | plot-20 0
IfcAnnotation/Building plot-20 EAST | plot-20 0
IfcAnnotation/Building plot-18 WEST | plot-20 1
IfcAnnotation/Building plot-18 EAST | plot-20 1
IfcAnnotation/Building plot-19 NORTH | plot-20 1
IfcAnnotation/Building plot-19 SOUTH | plot-20 1
IfcAnnotation/Building plot-19 WEST | plot-20 1
IfcAnnotation/Building plot-19 EAST | plot-20 1
IfcAnnotation/Building plot-20 NORTH | plot-20 1
IfcAnnotation/Building plot-20 SOUTH | plot-20 1
IfcAnnotation/Building plot-20 WEST | plot-20 1
IfcAnnotation/Building plot-20 EAST | plot-20 1
IfcAnnotation/Building plot-18 WEST | plot-20 2
IfcAnnotation/Building plot-18 EAST | plot-20 2
IfcAnnotation/Building plot-19 NORTH | plot-20 2
IfcAnnotation/Building plot-19 SOUTH | plot-20 2
IfcAnnotation/Building plot-19 WEST | plot-20 2
IfcAnnotation/Building plot-19 EAST | plot-20 2
IfcAnnotation/Building plot-21 NORTH | plot-21 0
IfcAnnotation/Building plot-21 SOUTH | plot-21 0
IfcAnnotation/Building plot-21 WEST | plot-21 0
IfcAnnotation/Building plot-21 EAST | plot-21 0
IfcAnnotation/Building plot-22 NORTH | plot-21 0
IfcAnnotation/Building plot-22 SOUTH | plot-21 0
IfcAnnotation/Building plot-22 WEST | plot-21 0
IfcAnnotation/Building plot-22 EAST | plot-21 0
IfcAnnotation/Building plot-21 NORTH | plot-21 1
IfcAnnotation/Building plot-21 SOUTH | plot-21 1
IfcAnnotation/Building plot-21 WEST | plot-21 1
IfcAnnotation/Building plot-21 EAST | plot-21 1
IfcAnnotation/Building plot-22 NORTH | plot-21 1
IfcAnnotation/Building plot-22 SOUTH | plot-21 1
IfcAnnotation/Building plot-22 WEST | plot-21 1
IfcAnnotation/Building plot-22 EAST | plot-21 1
IfcAnnotation/Building plot-23 NORTH | plot-21 1
IfcAnnotation/Building plot-23 SOUTH | plot-21 1
IfcAnnotation/Building plot-23 WEST | plot-21 1
IfcAnnotation/Building plot-23 EAST | plot-21 1
IfcAnnotation/Building plot-22 NORTH | plot-21 2
IfcAnnotation/Building plot-22 SOUTH | plot-21 2
IfcAnnotation/Building plot-22 WEST | plot-21 2
IfcAnnotation/Building plot-22 EAST | plot-21 2
IfcAnnotation/Building plot-23 NORTH | plot-21 2
IfcAnnotation/Building plot-23 SOUTH | plot-21 2
IfcAnnotation/Building plot-23 WEST | plot-21 2
IfcAnnotation/Building plot-23 EAST | plot-21 2
IfcAnnotation/Building plot-22 NORTH | plot-22 0
IfcAnnotation/Building plot-22 SOUTH | plot-22 0
IfcAnnotation/Building plot-22 WEST | plot-22 0
IfcAnnotation/Building plot-22 EAST | plot-22 0
IfcAnnotation/Building plot-21 NORTH | plot-22 1
IfcAnnotation/Building plot-21 SOUTH | plot-22 1
IfcAnnotation/Building plot-21 WEST | plot-22 1
IfcAnnotation/Building plot-21 EAST | plot-22 1
IfcAnnotation/Building plot-22 NORTH | plot-22 1
IfcAnnotation/Building plot-22 SOUTH | plot-22 1
IfcAnnotation/Building plot-22 WEST | plot-22 1
IfcAnnotation/Building plot-22 EAST | plot-22 1
IfcAnnotation/Building plot-23 WEST | plot-22 1
IfcAnnotation/Building plot-23 EAST | plot-22 1
IfcAnnotation/Building plot-21 NORTH | plot-22 2
IfcAnnotation/Building plot-21 SOUTH | plot-22 2
IfcAnnotation/Building plot-21 WEST | plot-22 2
IfcAnnotation/Building plot-21 EAST | plot-22 2
IfcAnnotation/Building plot-23 WEST | plot-22 2
IfcAnnotation/Building plot-23 EAST | plot-22 2
IfcAnnotation/Building plot-21 NORTH | plot-23 0
IfcAnnotation/Building plot-21 SOUTH | plot-23 0
IfcAnnotation/Building plot-21 WEST | plot-23 0
IfcAnnotation/Building plot-21 EAST | plot-23 0
IfcAnnotation/Building plot-22 WEST | plot-23 0
IfcAnnotation/Building plot-22 EAST | plot-23 0
IfcAnnotation/Building plot-24 NORTH | plot-23 0
IfcAnnotation/Building plot-24 SOUTH | plot-23 0
IfcAnnotation/Building plot-24 WEST | plot-23 0
IfcAnnotation/Building plot-24 EAST | plot-23 0
IfcAnnotation/Building plot-21 NORTH | plot-23 1
IfcAnnotation/Building plot-21 SOUTH | plot-23 1
IfcAnnotation/Building plot-21 WEST | plot-23 1
IfcAnnotation/Building plot-21 EAST | plot-23 1
IfcAnnotation/Building plot-22 WEST | plot-23 1
IfcAnnotation/Building plot-22 EAST | plot-23 1
IfcAnnotation/Building plot-23 NORTH | plot-23 1
IfcAnnotation/Building plot-23 SOUTH | plot-23 1
IfcAnnotation/Building plot-23 WEST | plot-23 1
IfcAnnotation/Building plot-23 EAST | plot-23 1
IfcAnnotation/Building plot-24 NORTH | plot-23 1
IfcAnnotation/Building plot-24 SOUTH | plot-23 1
IfcAnnotation/Building plot-24 WEST | plot-23 1
IfcAnnotation/Building plot-24 EAST | plot-23 1
IfcAnnotation/Building plot-21 NORTH | plot-23 2
IfcAnnotation/Building plot-21 SOUTH | plot-23 2
IfcAnnotation/Building plot-21 WEST | plot-23 2
IfcAnnotation/Building plot-21 EAST | plot-23 2
IfcAnnotation/Building plot-22 WEST | plot-23 2
IfcAnnotation/Building plot-22 EAST | plot-23 2
IfcAnnotation/Building plot-24 NORTH | plot-23 2
IfcAnnotation/Building plot-24 SOUTH | plot-23 2
IfcAnnotation/Building plot-24 WEST | plot-23 2
IfcAnnotation/Building plot-24 EAST | plot-23 2
IfcAnnotation/Building plot-24 NORTH | plot-24 0
IfcAnnotation/Building plot-24 SOUTH | plot-24 0
IfcAnnotation/Building plot-24 WEST | plot-24 0
IfcAnnotation/Building plot-24 EAST | plot-24 0
IfcAnnotation/Building plot-25 NORTH | plot-24 0
IfcAnnotation/Building plot-25 SOUTH | plot-24 0
IfcAnnotation/Building plot-25 WEST | plot-24 0
IfcAnnotation/Building plot-25 EAST | plot-24 0
IfcAnnotation/Building plot-28 NORTH | plot-24 0
IfcAnnotation/Building plot-28 SOUTH | plot-24 0
IfcAnnotation/Building plot-23 NORTH | plot-24 1
IfcAnnotation/Building plot-23 SOUTH | plot-24 1
IfcAnnotation/Building plot-23 WEST | plot-24 1
IfcAnnotation/Building plot-23 EAST | plot-24 1
IfcAnnotation/Building plot-24 NORTH | plot-24 1
IfcAnnotation/Building plot-24 SOUTH | plot-24 1
IfcAnnotation/Building plot-24 WEST | plot-24 1
IfcAnnotation/Building plot-24 EAST | plot-24 1
IfcAnnotation/Building plot-25 NORTH | plot-24 1
IfcAnnotation/Building plot-25 SOUTH | plot-24 1
IfcAnnotation/Building plot-25 WEST | plot-24 1
IfcAnnotation/Building plot-25 EAST | plot-24 1
IfcAnnotation/Building plot-28 NORTH | plot-24 1
IfcAnnotation/Building plot-28 SOUTH | plot-24 1
IfcAnnotation/Building plot-23 NORTH | plot-24 2
IfcAnnotation/Building plot-23 SOUTH | plot-24 2
IfcAnnotation/Building plot-23 WEST | plot-24 2
IfcAnnotation/Building plot-23 EAST | plot-24 2
IfcAnnotation/Building plot-25 NORTH | plot-24 2
IfcAnnotation/Building plot-25 SOUTH | plot-24 2
IfcAnnotation/Building plot-25 WEST | plot-24 2
IfcAnnotation/Building plot-25 EAST | plot-24 2
IfcAnnotation/Building plot-28 NORTH | plot-24 2
IfcAnnotation/Building plot-28 SOUTH | plot-24 2
IfcAnnotation/Building plot-24 NORTH | plot-25 0
IfcAnnotation/Building plot-24 SOUTH | plot-25 0
IfcAnnotation/Building plot-24 WEST | plot-25 0
IfcAnnotation/Building plot-24 EAST | plot-25 0
IfcAnnotation/Building plot-25 NORTH | plot-25 0
IfcAnnotation/Building plot-25 SOUTH | plot-25 0
IfcAnnotation/Building plot-25 WEST | plot-25 0
IfcAnnotation/Building plot-25 EAST | plot-25 0
IfcAnnotation/Building plot-24 NORTH | plot-25 1
IfcAnnotation/Building plot-24 SOUTH | plot-25 1
IfcAnnotation/Building plot-24 WEST | plot-25 1
IfcAnnotation/Building plot-24 EAST | plot-25 1
IfcAnnotation/Building plot-25 NORTH | plot-25 1
IfcAnnotation/Building plot-25 SOUTH | plot-25 1
IfcAnnotation/Building plot-25 WEST | plot-25 1
IfcAnnotation/Building plot-25 EAST | plot-25 1
IfcAnnotation/Building plot-26 NORTH | plot-26 0
IfcAnnotation/Building plot-26 SOUTH | plot-26 0
IfcAnnotation/Building plot-26 WEST | plot-26 0
IfcAnnotation/Building plot-26 EAST | plot-26 0
IfcAnnotation/Building plot-27 NORTH | plot-26 0
IfcAnnotation/Building plot-27 SOUTH | plot-26 0
IfcAnnotation/Building plot-27 WEST | plot-26 0
IfcAnnotation/Building plot-27 EAST | plot-26 0
IfcAnnotation/Building plot-26 NORTH | plot-26 1
IfcAnnotation/Building plot-26 SOUTH | plot-26 1
IfcAnnotation/Building plot-26 WEST | plot-26 1
IfcAnnotation/Building plot-26 EAST | plot-26 1
IfcAnnotation/Building plot-27 NORTH | plot-26 1
IfcAnnotation/Building plot-27 SOUTH | plot-26 1
IfcAnnotation/Building plot-27 WEST | plot-26 1
IfcAnnotation/Building plot-27 EAST | plot-26 1
IfcAnnotation/Building plot-27 NORTH | plot-26 2
IfcAnnotation/Building plot-27 SOUTH | plot-26 2
IfcAnnotation/Building plot-27 WEST | plot-26 2
IfcAnnotation/Building plot-27 EAST | plot-26 2
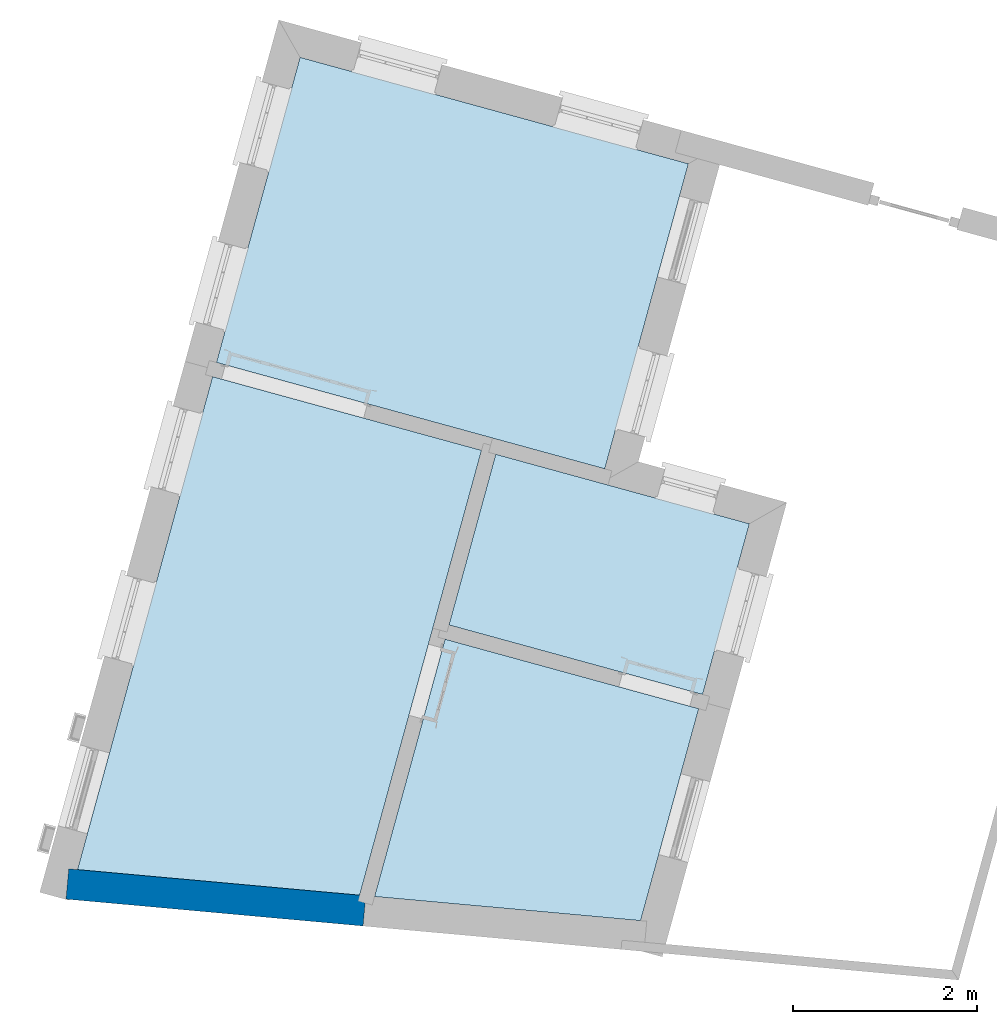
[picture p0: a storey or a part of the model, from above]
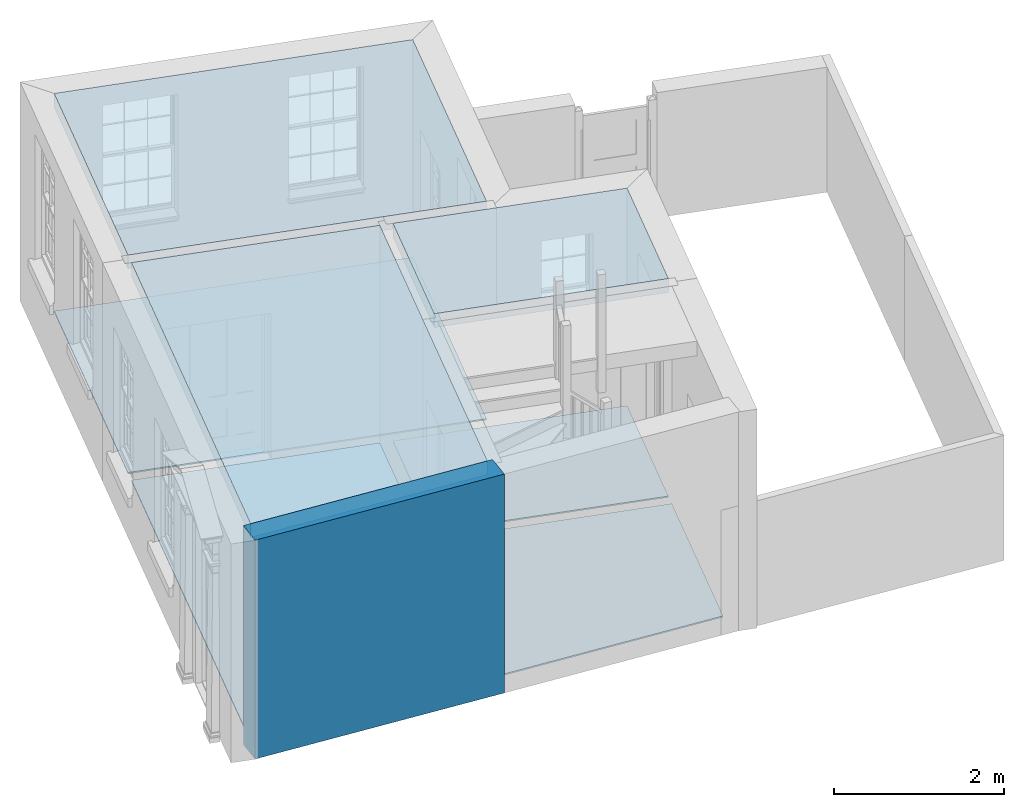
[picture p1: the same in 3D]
Properties of the parts of a building model (IFC4), part 3 of 4

# IfcAnnotation: ELEVATION (1369)
Name | Group
IfcAnnotation/Building plot-26 NORTH | plot-27 0
IfcAnnotation/Building plot-26 SOUTH | plot-27 0
IfcAnnotation/Building plot-26 WEST | plot-27 0
IfcAnnotation/Building plot-26 EAST | plot-27 0
IfcAnnotation/Building plot-27 NORTH | plot-27 0
IfcAnnotation/Building plot-27 SOUTH | plot-27 0
IfcAnnotation/Building plot-27 WEST | plot-27 0
IfcAnnotation/Building plot-27 EAST | plot-27 0
IfcAnnotation/Building plot-26 NORTH | plot-27 1
IfcAnnotation/Building plot-26 SOUTH | plot-27 1
IfcAnnotation/Building plot-26 WEST | plot-27 1
IfcAnnotation/Building plot-26 EAST | plot-27 1
IfcAnnotation/Building plot-27 NORTH | plot-27 1
IfcAnnotation/Building plot-27 SOUTH | plot-27 1
IfcAnnotation/Building plot-27 WEST | plot-27 1
IfcAnnotation/Building plot-27 EAST | plot-27 1
IfcAnnotation/Building plot-26 NORTH | plot-27 2
IfcAnnotation/Building plot-26 SOUTH | plot-27 2
IfcAnnotation/Building plot-26 WEST | plot-27 2
IfcAnnotation/Building plot-26 EAST | plot-27 2
IfcAnnotation/Building plot-28 NORTH | plot-28 0
IfcAnnotation/Building plot-28 SOUTH | plot-28 0
IfcAnnotation/Building plot-28 WEST | plot-28 0
IfcAnnotation/Building plot-28 EAST | plot-28 0
IfcAnnotation/Building plot-24 NORTH | plot-28 1
IfcAnnotation/Building plot-24 SOUTH | plot-28 1
IfcAnnotation/Building plot-28 NORTH | plot-28 1
IfcAnnotation/Building plot-28 SOUTH | plot-28 1
IfcAnnotation/Building plot-28 WEST | plot-28 1
IfcAnnotation/Building plot-28 EAST | plot-28 1
IfcAnnotation/Building plot-29 WEST | plot-28 1
IfcAnnotation/Building plot-29 EAST | plot-28 1
IfcAnnotation/Building plot-24 NORTH | plot-28 2
IfcAnnotation/Building plot-24 SOUTH | plot-28 2
IfcAnnotation/Building plot-29 WEST | plot-28 2
IfcAnnotation/Building plot-29 EAST | plot-28 2
IfcAnnotation/Building plot-28 WEST | plot-29 0
IfcAnnotation/Building plot-28 EAST | plot-29 0
IfcAnnotation/Building plot-29 NORTH | plot-29 0
IfcAnnotation/Building plot-29 SOUTH | plot-29 0
IfcAnnotation/Building plot-29 WEST | plot-29 0
IfcAnnotation/Building plot-29 EAST | plot-29 0
IfcAnnotation/Building plot-30 WEST | plot-29 0
IfcAnnotation/Building plot-30 EAST | plot-29 0
IfcAnnotation/Building plot-28 WEST | plot-29 1
IfcAnnotation/Building plot-28 EAST | plot-29 1
IfcAnnotation/Building plot-29 NORTH | plot-29 1
IfcAnnotation/Building plot-29 SOUTH | plot-29 1
IfcAnnotation/Building plot-29 WEST | plot-29 1
IfcAnnotation/Building plot-29 EAST | plot-29 1
IfcAnnotation/Building plot-30 WEST | plot-29 1
IfcAnnotation/Building plot-30 EAST | plot-29 1
IfcAnnotation/Building plot-28 WEST | plot-29 2
IfcAnnotation/Building plot-28 EAST | plot-29 2
IfcAnnotation/Building plot-30 WEST | plot-29 2
IfcAnnotation/Building plot-30 EAST | plot-29 2
IfcAnnotation/Building plot-0 EAST | plot-3 0
IfcAnnotation/Building plot-3 NORTH | plot-3 0
IfcAnnotation/Building plot-3 SOUTH | plot-3 0
IfcAnnotation/Building plot-3 WEST | plot-3 0
IfcAnnotation/Building plot-3 EAST | plot-3 0
IfcAnnotation/Building plot-4 NORTH | plot-3 0
IfcAnnotation/Building plot-4 SOUTH | plot-3 0
IfcAnnotation/Building plot-4 WEST | plot-3 0
IfcAnnotation/Building plot-4 EAST | plot-3 0
IfcAnnotation/Building plot-0 EAST | plot-3 1
IfcAnnotation/Building plot-1 NORTH | plot-3 1
IfcAnnotation/Building plot-1 SOUTH | plot-3 1
IfcAnnotation/Building plot-1 WEST | plot-3 1
IfcAnnotation/Building plot-1 EAST | plot-3 1
IfcAnnotation/Building plot-3 NORTH | plot-3 1
IfcAnnotation/Building plot-3 SOUTH | plot-3 1
IfcAnnotation/Building plot-3 WEST | plot-3 1
IfcAnnotation/Building plot-3 EAST | plot-3 1
IfcAnnotation/Building plot-4 NORTH | plot-3 1
IfcAnnotation/Building plot-4 SOUTH | plot-3 1
IfcAnnotation/Building plot-4 WEST | plot-3 1
IfcAnnotation/Building plot-4 EAST | plot-3 1
IfcAnnotation/Building plot-0 EAST | plot-3 2
IfcAnnotation/Building plot-1 NORTH | plot-3 2
IfcAnnotation/Building plot-1 SOUTH | plot-3 2
IfcAnnotation/Building plot-1 WEST | plot-3 2
IfcAnnotation/Building plot-1 EAST | plot-3 2
IfcAnnotation/Building plot-4 NORTH | plot-3 2
IfcAnnotation/Building plot-4 SOUTH | plot-3 2
IfcAnnotation/Building plot-4 WEST | plot-3 2
IfcAnnotation/Building plot-4 EAST | plot-3 2
IfcAnnotation/Building plot-3 NORTH | plot-4 0
IfcAnnotation/Building plot-3 SOUTH | plot-4 0
IfcAnnotation/Building plot-3 WEST | plot-4 0
IfcAnnotation/Building plot-3 EAST | plot-4 0
IfcAnnotation/Building plot-4 NORTH | plot-4 0
IfcAnnotation/Building plot-4 SOUTH | plot-4 0
IfcAnnotation/Building plot-4 WEST | plot-4 0
IfcAnnotation/Building plot-4 EAST | plot-4 0
IfcAnnotation/Building plot-5 NORTH | plot-4 0
IfcAnnotation/Building plot-5 SOUTH | plot-4 0
IfcAnnotation/Building plot-5 WEST | plot-4 0
IfcAnnotation/Building plot-5 EAST | plot-4 0
IfcAnnotation/Building plot-2 NORTH | plot-4 1
IfcAnnotation/Building plot-2 SOUTH | plot-4 1
IfcAnnotation/Building plot-3 NORTH | plot-4 1
IfcAnnotation/Building plot-3 SOUTH | plot-4 1
IfcAnnotation/Building plot-3 WEST | plot-4 1
IfcAnnotation/Building plot-3 EAST | plot-4 1
IfcAnnotation/Building plot-4 NORTH | plot-4 1
IfcAnnotation/Building plot-4 SOUTH | plot-4 1
IfcAnnotation/Building plot-4 WEST | plot-4 1
IfcAnnotation/Building plot-4 EAST | plot-4 1
IfcAnnotation/Building plot-5 NORTH | plot-4 1
IfcAnnotation/Building plot-5 SOUTH | plot-4 1
IfcAnnotation/Building plot-5 WEST | plot-4 1
IfcAnnotation/Building plot-5 EAST | plot-4 1
IfcAnnotation/Building plot-2 NORTH | plot-4 2
IfcAnnotation/Building plot-2 SOUTH | plot-4 2
IfcAnnotation/Building plot-3 NORTH | plot-4 2
IfcAnnotation/Building plot-3 SOUTH | plot-4 2
IfcAnnotation/Building plot-3 WEST | plot-4 2
IfcAnnotation/Building plot-3 EAST | plot-4 2
IfcAnnotation/Building plot-5 NORTH | plot-4 2
IfcAnnotation/Building plot-5 SOUTH | plot-4 2
IfcAnnotation/Building plot-5 WEST | plot-4 2
IfcAnnotation/Building plot-5 EAST | plot-4 2
IfcAnnotation/Building plot-5 NORTH | plot-5 0
IfcAnnotation/Building plot-5 SOUTH | plot-5 0
IfcAnnotation/Building plot-5 WEST | plot-5 0
IfcAnnotation/Building plot-5 EAST | plot-5 0
IfcAnnotation/Building plot-4 NORTH | plot-5 1
IfcAnnotation/Building plot-4 SOUTH | plot-5 1
IfcAnnotation/Building plot-4 WEST | plot-5 1
IfcAnnotation/Building plot-4 EAST | plot-5 1
IfcAnnotation/Building plot-5 NORTH | plot-5 1
IfcAnnotation/Building plot-5 SOUTH | plot-5 1
IfcAnnotation/Building plot-5 WEST | plot-5 1
IfcAnnotation/Building plot-5 EAST | plot-5 1
IfcAnnotation/Building plot-6 NORTH | plot-5 1
IfcAnnotation/Building plot-6 SOUTH | plot-5 1
IfcAnnotation/Building plot-6 WEST | plot-5 1
IfcAnnotation/Building plot-6 EAST | plot-5 1
IfcAnnotation/Building plot-4 NORTH | plot-5 2
IfcAnnotation/Building plot-4 SOUTH | plot-5 2
IfcAnnotation/Building plot-4 WEST | plot-5 2
IfcAnnotation/Building plot-4 EAST | plot-5 2
IfcAnnotation/Building plot-6 NORTH | plot-5 2
IfcAnnotation/Building plot-6 SOUTH | plot-5 2
IfcAnnotation/Building plot-6 WEST | plot-5 2
IfcAnnotation/Building plot-6 EAST | plot-5 2
IfcAnnotation/Building plot-5 NORTH | plot-6 0
IfcAnnotation/Building plot-5 SOUTH | plot-6 0
IfcAnnotation/Building plot-5 WEST | plot-6 0
IfcAnnotation/Building plot-5 EAST | plot-6 0
IfcAnnotation/Building plot-2 NORTH | plot-6 1
IfcAnnotation/Building plot-2 SOUTH | plot-6 1
IfcAnnotation/Building plot-5 NORTH | plot-6 1
IfcAnnotation/Building plot-5 SOUTH | plot-6 1
IfcAnnotation/Building plot-5 WEST | plot-6 1
IfcAnnotation/Building plot-5 EAST | plot-6 1
IfcAnnotation/Building plot-6 NORTH | plot-6 1
IfcAnnotation/Building plot-6 SOUTH | plot-6 1
IfcAnnotation/Building plot-6 WEST | plot-6 1
IfcAnnotation/Building plot-6 EAST | plot-6 1
IfcAnnotation/Building plot-7 NORTH | plot-6 1
IfcAnnotation/Building plot-7 SOUTH | plot-6 1
IfcAnnotation/Building plot-7 WEST | plot-6 1
IfcAnnotation/Building plot-7 EAST | plot-6 1
IfcAnnotation/Building plot-2 NORTH | plot-6 2
IfcAnnotation/Building plot-2 SOUTH | plot-6 2
IfcAnnotation/Building plot-5 NORTH | plot-6 2
IfcAnnotation/Building plot-5 SOUTH | plot-6 2
IfcAnnotation/Building plot-5 WEST | plot-6 2
IfcAnnotation/Building plot-5 EAST | plot-6 2
IfcAnnotation/Building plot-7 NORTH | plot-6 2
IfcAnnotation/Building plot-7 SOUTH | plot-6 2
IfcAnnotation/Building plot-7 WEST | plot-6 2
IfcAnnotation/Building plot-7 EAST | plot-6 2
IfcAnnotation/Building plot-2 WEST | plot-7 0
IfcAnnotation/Building plot-2 EAST | plot-7 0
IfcAnnotation/Building plot-5 WEST | plot-7 0
IfcAnnotation/Building plot-5 EAST | plot-7 0
IfcAnnotation/Building plot-6 NORTH | plot-7 0
IfcAnnotation/Building plot-6 SOUTH | plot-7 0
IfcAnnotation/Building plot-6 WEST | plot-7 0
IfcAnnotation/Building plot-6 EAST | plot-7 0
IfcAnnotation/Building plot-7 NORTH | plot-7 0
IfcAnnotation/Building plot-7 SOUTH | plot-7 0
IfcAnnotation/Building plot-7 WEST | plot-7 0
IfcAnnotation/Building plot-7 EAST | plot-7 0
IfcAnnotation/Building plot-22 WEST | plot-7 0
IfcAnnotation/Building plot-22 EAST | plot-7 0
IfcAnnotation/Building plot-2 WEST | plot-7 1
IfcAnnotation/Building plot-2 EAST | plot-7 1
IfcAnnotation/Building plot-5 WEST | plot-7 1
IfcAnnotation/Building plot-5 EAST | plot-7 1
IfcAnnotation/Building plot-6 NORTH | plot-7 1
IfcAnnotation/Building plot-6 SOUTH | plot-7 1
IfcAnnotation/Building plot-6 WEST | plot-7 1
IfcAnnotation/Building plot-6 EAST | plot-7 1
IfcAnnotation/Building plot-7 NORTH | plot-7 1
IfcAnnotation/Building plot-7 SOUTH | plot-7 1
IfcAnnotation/Building plot-7 WEST | plot-7 1
IfcAnnotation/Building plot-7 EAST | plot-7 1
IfcAnnotation/Building plot-22 WEST | plot-7 1
IfcAnnotation/Building plot-22 EAST | plot-7 1
IfcAnnotation/Building plot-2 WEST | plot-7 2
IfcAnnotation/Building plot-2 EAST | plot-7 2
IfcAnnotation/Building plot-5 WEST | plot-7 2
IfcAnnotation/Building plot-5 EAST | plot-7 2
IfcAnnotation/Building plot-6 NORTH | plot-7 2
IfcAnnotation/Building plot-6 SOUTH | plot-7 2
IfcAnnotation/Building plot-6 WEST | plot-7 2
IfcAnnotation/Building plot-6 EAST | plot-7 2
IfcAnnotation/Building plot-22 WEST | plot-7 2
IfcAnnotation/Building plot-22 EAST | plot-7 2
IfcAnnotation/Building plot-0 NORTH | plot-8 0
IfcAnnotation/Building plot-0 SOUTH | plot-8 0
IfcAnnotation/Building plot-0 EAST | plot-8 0
IfcAnnotation/Building plot-8 NORTH | plot-8 0
IfcAnnotation/Building plot-8 SOUTH | plot-8 0
IfcAnnotation/Building plot-8 WEST | plot-8 0
IfcAnnotation/Building plot-8 EAST | plot-8 0
IfcAnnotation/Building plot-9 NORTH | plot-8 0
IfcAnnotation/Building plot-9 SOUTH | plot-8 0
IfcAnnotation/Building plot-9 WEST | plot-8 0
IfcAnnotation/Building plot-9 EAST | plot-8 0
IfcAnnotation/Building plot-12 WEST | plot-8 0
IfcAnnotation/Building plot-12 EAST | plot-8 0
IfcAnnotation/Building plot-0 NORTH | plot-8 1
IfcAnnotation/Building plot-0 SOUTH | plot-8 1
IfcAnnotation/Building plot-0 EAST | plot-8 1
IfcAnnotation/Building plot-8 NORTH | plot-8 1
IfcAnnotation/Building plot-8 SOUTH | plot-8 1
IfcAnnotation/Building plot-8 WEST | plot-8 1
IfcAnnotation/Building plot-8 EAST | plot-8 1
IfcAnnotation/Building plot-9 NORTH | plot-8 1
IfcAnnotation/Building plot-9 SOUTH | plot-8 1
IfcAnnotation/Building plot-9 WEST | plot-8 1
IfcAnnotation/Building plot-9 EAST | plot-8 1
IfcAnnotation/Building plot-10 NORTH | plot-8 1
IfcAnnotation/Building plot-10 SOUTH | plot-8 1
IfcAnnotation/Building plot-10 WEST | plot-8 1
IfcAnnotation/Building plot-10 EAST | plot-8 1
IfcAnnotation/Building plot-12 WEST | plot-8 1
IfcAnnotation/Building plot-12 EAST | plot-8 1
IfcAnnotation/Building plot-0 NORTH | plot-8 2
IfcAnnotation/Building plot-0 SOUTH | plot-8 2
IfcAnnotation/Building plot-0 EAST | plot-8 2
IfcAnnotation/Building plot-9 NORTH | plot-8 2
IfcAnnotation/Building plot-9 SOUTH | plot-8 2
IfcAnnotation/Building plot-9 WEST | plot-8 2
IfcAnnotation/Building plot-9 EAST | plot-8 2
IfcAnnotation/Building plot-10 NORTH | plot-8 2
IfcAnnotation/Building plot-10 SOUTH | plot-8 2
IfcAnnotation/Building plot-10 WEST | plot-8 2
IfcAnnotation/Building plot-10 EAST | plot-8 2
IfcAnnotation/Building plot-12 WEST | plot-8 2
IfcAnnotation/Building plot-12 EAST | plot-8 2
IfcAnnotation/Building plot-8 NORTH | plot-9 0
IfcAnnotation/Building plot-8 SOUTH | plot-9 0
IfcAnnotation/Building plot-9 NORTH | plot-9 0
IfcAnnotation/Building plot-9 SOUTH | plot-9 0
IfcAnnotation/Building plot-9 WEST | plot-9 0
IfcAnnotation/Building plot-9 EAST | plot-9 0
IfcAnnotation/Building plot-8 NORTH | plot-9 1
IfcAnnotation/Building plot-8 SOUTH | plot-9 1
IfcAnnotation/Building plot-9 NORTH | plot-9 1
IfcAnnotation/Building plot-9 SOUTH | plot-9 1
IfcAnnotation/Building plot-9 WEST | plot-9 1
IfcAnnotation/Building plot-9 EAST | plot-9 1
IfcAnnotation/Building plot-10 NORTH | plot-9 1
IfcAnnotation/Building plot-10 SOUTH | plot-9 1
IfcAnnotation/Building plot-10 WEST | plot-9 1
IfcAnnotation/Building plot-10 EAST | plot-9 1
IfcAnnotation/Building plot-29 NORTH | plot-30 0
IfcAnnotation/Building plot-29 SOUTH | plot-30 0
IfcAnnotation/Building plot-29 WEST | plot-30 0
IfcAnnotation/Building plot-29 EAST | plot-30 0
IfcAnnotation/Building plot-30 NORTH | plot-30 0
IfcAnnotation/Building plot-30 SOUTH | plot-30 0
IfcAnnotation/Building plot-30 WEST | plot-30 0
IfcAnnotation/Building plot-30 EAST | plot-30 0
IfcAnnotation/Building plot-31 NORTH | plot-30 0
IfcAnnotation/Building plot-31 SOUTH | plot-30 0
IfcAnnotation/Building plot-31 WEST | plot-30 0
IfcAnnotation/Building plot-31 EAST | plot-30 0
IfcAnnotation/Building plot-29 NORTH | plot-30 1
IfcAnnotation/Building plot-29 SOUTH | plot-30 1
IfcAnnotation/Building plot-29 WEST | plot-30 1
IfcAnnotation/Building plot-29 EAST | plot-30 1
IfcAnnotation/Building plot-30 NORTH | plot-30 1
IfcAnnotation/Building plot-30 SOUTH | plot-30 1
IfcAnnotation/Building plot-30 WEST | plot-30 1
IfcAnnotation/Building plot-30 EAST | plot-30 1
IfcAnnotation/Building plot-31 NORTH | plot-30 1
IfcAnnotation/Building plot-31 SOUTH | plot-30 1
IfcAnnotation/Building plot-31 WEST | plot-30 1
IfcAnnotation/Building plot-31 EAST | plot-30 1
IfcAnnotation/Building plot-29 NORTH | plot-30 2
IfcAnnotation/Building plot-29 SOUTH | plot-30 2
IfcAnnotation/Building plot-29 WEST | plot-30 2
IfcAnnotation/Building plot-29 EAST | plot-30 2
IfcAnnotation/Building plot-30 NORTH | plot-30 2
IfcAnnotation/Building plot-30 SOUTH | plot-30 2
IfcAnnotation/Building plot-30 WEST | plot-30 2
IfcAnnotation/Building plot-30 EAST | plot-30 2
IfcAnnotation/Building plot-31 NORTH | plot-30 2
IfcAnnotation/Building plot-31 SOUTH | plot-30 2
IfcAnnotation/Building plot-31 WEST | plot-30 2
IfcAnnotation/Building plot-31 EAST | plot-30 2
IfcAnnotation/Building plot-26 NORTH | plot-31 0
IfcAnnotation/Building plot-26 SOUTH | plot-31 0
IfcAnnotation/Building plot-26 WEST | plot-31 0
IfcAnnotation/Building plot-26 EAST | plot-31 0
IfcAnnotation/Building plot-30 NORTH | plot-31 0
IfcAnnotation/Building plot-30 SOUTH | plot-31 0
IfcAnnotation/Building plot-30 WEST | plot-31 0
IfcAnnotation/Building plot-30 EAST | plot-31 0
IfcAnnotation/Building plot-31 NORTH | plot-31 0
IfcAnnotation/Building plot-31 SOUTH | plot-31 0
IfcAnnotation/Building plot-31 WEST | plot-31 0
IfcAnnotation/Building plot-31 EAST | plot-31 0
IfcAnnotation/Building plot-26 NORTH | plot-31 1
IfcAnnotation/Building plot-26 SOUTH | plot-31 1
IfcAnnotation/Building plot-26 WEST | plot-31 1
IfcAnnotation/Building plot-26 EAST | plot-31 1
IfcAnnotation/Building plot-30 NORTH | plot-31 1
IfcAnnotation/Building plot-30 SOUTH | plot-31 1
IfcAnnotation/Building plot-30 WEST | plot-31 1
IfcAnnotation/Building plot-30 EAST | plot-31 1
IfcAnnotation/Building plot-31 NORTH | plot-31 1
IfcAnnotation/Building plot-31 SOUTH | plot-31 1
IfcAnnotation/Building plot-31 WEST | plot-31 1
IfcAnnotation/Building plot-31 EAST | plot-31 1
IfcAnnotation/Building plot-26 NORTH | plot-31 2
IfcAnnotation/Building plot-26 SOUTH | plot-31 2
IfcAnnotation/Building plot-26 WEST | plot-31 2
IfcAnnotation/Building plot-26 EAST | plot-31 2
IfcAnnotation/Building plot-30 NORTH | plot-31 2
IfcAnnotation/Building plot-30 SOUTH | plot-31 2
IfcAnnotation/Building plot-30 WEST | plot-31 2
IfcAnnotation/Building plot-30 EAST | plot-31 2
IfcAnnotation/Building plot-31 NORTH | plot-31 2
IfcAnnotation/Building plot-31 SOUTH | plot-31 2
IfcAnnotation/Building plot-31 WEST | plot-31 2
IfcAnnotation/Building plot-31 EAST | plot-31 2
IfcAnnotation/Building plot-30 WEST | Building plot-0 LOCATION
IfcAnnotation/Building plot-30 EAST | Building plot-0 LOCATION
IfcAnnotation/Building plot-31 WEST | Building plot-0 LOCATION
IfcAnnotation/Building plot-9 WEST | Building plot-1 LOCATION
IfcAnnotation/Building plot-9 EAST | Building plot-1 LOCATION
IfcAnnotation/Building plot-14 NORTH | Building plot-1 LOCATION
IfcAnnotation/Building plot-14 SOUTH | Building plot-1 LOCATION
IfcAnnotation/Building plot-30 WEST | Building plot-1 LOCATION
IfcAnnotation/Building plot-30 EAST | Building plot-1 LOCATION
IfcAnnotation/Building plot-31 NORTH | Building plot-1 LOCATION
IfcAnnotation/Building plot-31 SOUTH | Building plot-1 LOCATION
IfcAnnotation/Building plot-31 WEST | Building plot-1 LOCATION
IfcAnnotation/Building plot-31 EAST | Building plot-1 LOCATION
IfcAnnotation/Building plot-9 WEST | Building plot-10 LOCATION
IfcAnnotation/Building plot-9 EAST | Building plot-10 LOCATION
IfcAnnotation/Building plot-14 NORTH | Building plot-10 LOCATION
IfcAnnotation/Building plot-14 SOUTH | Building plot-10 LOCATION
IfcAnnotation/Building plot-30 WEST | Building plot-10 LOCATION
IfcAnnotation/Building plot-30 EAST | Building plot-10 LOCATION
IfcAnnotation/Building plot-31 NORTH | Building plot-10 LOCATION
IfcAnnotation/Building plot-31 SOUTH | Building plot-10 LOCATION
IfcAnnotation/Building plot-31 WEST | Building plot-10 LOCATION
IfcAnnotation/Building plot-31 EAST | Building plot-10 LOCATION
IfcAnnotation/Building plot-9 WEST | Building plot-11 LOCATION
IfcAnnotation/Building plot-9 EAST | Building plot-11 LOCATION
IfcAnnotation/Building plot-14 NORTH | Building plot-11 LOCATION
IfcAnnotation/Building plot-14 SOUTH | Building plot-11 LOCATION
IfcAnnotation/Building plot-30 WEST | Building plot-11 LOCATION
IfcAnnotation/Building plot-30 EAST | Building plot-11 LOCATION
IfcAnnotation/Building plot-31 NORTH | Building plot-11 LOCATION
IfcAnnotation/Building plot-31 SOUTH | Building plot-11 LOCATION
IfcAnnotation/Building plot-31 WEST | Building plot-11 LOCATION
IfcAnnotation/Building plot-31 EAST | Building plot-11 LOCATION
IfcAnnotation/Building plot-9 WEST | Building plot-12 LOCATION
IfcAnnotation/Building plot-9 EAST | Building plot-12 LOCATION
IfcAnnotation/Building plot-14 NORTH | Building plot-12 LOCATION
IfcAnnotation/Building plot-14 SOUTH | Building plot-12 LOCATION
IfcAnnotation/Building plot-30 WEST | Building plot-12 LOCATION
IfcAnnotation/Building plot-30 EAST | Building plot-12 LOCATION
IfcAnnotation/Building plot-31 NORTH | Building plot-12 LOCATION
IfcAnnotation/Building plot-31 SOUTH | Building plot-12 LOCATION
IfcAnnotation/Building plot-31 WEST | Building plot-12 LOCATION
IfcAnnotation/Building plot-31 EAST | Building plot-12 LOCATION
IfcAnnotation/Building plot-9 WEST | Building plot-13 LOCATION
IfcAnnotation/Building plot-9 EAST | Building plot-13 LOCATION
IfcAnnotation/Building plot-14 NORTH | Building plot-13 LOCATION
IfcAnnotation/Building plot-14 SOUTH | Building plot-13 LOCATION
IfcAnnotation/Building plot-30 WEST | Building plot-13 LOCATION
IfcAnnotation/Building plot-30 EAST | Building plot-13 LOCATION
IfcAnnotation/Building plot-31 NORTH | Building plot-13 LOCATION
IfcAnnotation/Building plot-31 SOUTH | Building plot-13 LOCATION
IfcAnnotation/Building plot-31 WEST | Building plot-13 LOCATION
IfcAnnotation/Building plot-31 EAST | Building plot-13 LOCATION
IfcAnnotation/Building plot-9 WEST | Building plot-14 LOCATION
IfcAnnotation/Building plot-9 EAST | Building plot-14 LOCATION
IfcAnnotation/Building plot-14 NORTH | Building plot-14 LOCATION
IfcAnnotation/Building plot-14 SOUTH | Building plot-14 LOCATION
IfcAnnotation/Building plot-30 WEST | Building plot-14 LOCATION
IfcAnnotation/Building plot-30 EAST | Building plot-14 LOCATION
IfcAnnotation/Building plot-31 NORTH | Building plot-14 LOCATION
IfcAnnotation/Building plot-31 SOUTH | Building plot-14 LOCATION
IfcAnnotation/Building plot-31 WEST | Building plot-14 LOCATION
IfcAnnotation/Building plot-31 EAST | Building plot-14 LOCATION
IfcAnnotation/Building plot-9 WEST | Building plot-15 LOCATION
IfcAnnotation/Building plot-9 EAST | Building plot-15 LOCATION
IfcAnnotation/Building plot-14 NORTH | Building plot-15 LOCATION
IfcAnnotation/Building plot-14 SOUTH | Building plot-15 LOCATION
IfcAnnotation/Building plot-30 WEST | Building plot-15 LOCATION
IfcAnnotation/Building plot-30 EAST | Building plot-15 LOCATION
IfcAnnotation/Building plot-31 NORTH | Building plot-15 LOCATION
IfcAnnotation/Building plot-31 SOUTH | Building plot-15 LOCATION
IfcAnnotation/Building plot-31 WEST | Building plot-15 LOCATION
IfcAnnotation/Building plot-31 EAST | Building plot-15 LOCATION
IfcAnnotation/Building plot-9 WEST | Building plot-16 LOCATION
IfcAnnotation/Building plot-9 EAST | Building plot-16 LOCATION
IfcAnnotation/Building plot-14 NORTH | Building plot-16 LOCATION
IfcAnnotation/Building plot-14 SOUTH | Building plot-16 LOCATION
IfcAnnotation/Building plot-30 WEST | Building plot-16 LOCATION
IfcAnnotation/Building plot-30 EAST | Building plot-16 LOCATION
IfcAnnotation/Building plot-31 NORTH | Building plot-16 LOCATION
IfcAnnotation/Building plot-31 SOUTH | Building plot-16 LOCATION
IfcAnnotation/Building plot-31 WEST | Building plot-16 LOCATION
IfcAnnotation/Building plot-31 EAST | Building plot-16 LOCATION
IfcAnnotation/Building plot-9 WEST | Building plot-17 LOCATION
IfcAnnotation/Building plot-9 EAST | Building plot-17 LOCATION
IfcAnnotation/Building plot-14 NORTH | Building plot-17 LOCATION
IfcAnnotation/Building plot-14 SOUTH | Building plot-17 LOCATION
IfcAnnotation/Building plot-30 WEST | Building plot-17 LOCATION
IfcAnnotation/Building plot-30 EAST | Building plot-17 LOCATION
IfcAnnotation/Building plot-31 NORTH | Building plot-17 LOCATION
IfcAnnotation/Building plot-31 SOUTH | Building plot-17 LOCATION
IfcAnnotation/Building plot-31 WEST | Building plot-17 LOCATION
IfcAnnotation/Building plot-31 EAST | Building plot-17 LOCATION
IfcAnnotation/Building plot-9 WEST | Building plot-18 LOCATION
IfcAnnotation/Building plot-9 EAST | Building plot-18 LOCATION
IfcAnnotation/Building plot-14 NORTH | Building plot-18 LOCATION
IfcAnnotation/Building plot-14 SOUTH | Building plot-18 LOCATION
IfcAnnotation/Building plot-30 WEST | Building plot-18 LOCATION
IfcAnnotation/Building plot-30 EAST | Building plot-18 LOCATION
IfcAnnotation/Building plot-31 NORTH | Building plot-18 LOCATION
IfcAnnotation/Building plot-31 SOUTH | Building plot-18 LOCATION
IfcAnnotation/Building plot-31 WEST | Building plot-18 LOCATION
IfcAnnotation/Building plot-31 EAST | Building plot-18 LOCATION
IfcAnnotation/Building plot-9 WEST | Building plot-19 LOCATION
IfcAnnotation/Building plot-9 EAST | Building plot-19 LOCATION
IfcAnnotation/Building plot-14 NORTH | Building plot-19 LOCATION
IfcAnnotation/Building plot-14 SOUTH | Building plot-19 LOCATION
IfcAnnotation/Building plot-30 WEST | Building plot-19 LOCATION
IfcAnnotation/Building plot-30 EAST | Building plot-19 LOCATION
IfcAnnotation/Building plot-31 NORTH | Building plot-19 LOCATION
IfcAnnotation/Building plot-31 SOUTH | Building plot-19 LOCATION
IfcAnnotation/Building plot-31 WEST | Building plot-19 LOCATION
IfcAnnotation/Building plot-31 EAST | Building plot-19 LOCATION
IfcAnnotation/Building plot-9 WEST | Building plot-2 LOCATION
IfcAnnotation/Building plot-9 EAST | Building plot-2 LOCATION
IfcAnnotation/Building plot-14 NORTH | Building plot-2 LOCATION
IfcAnnotation/Building plot-14 SOUTH | Building plot-2 LOCATION
IfcAnnotation/Building plot-30 WEST | Building plot-2 LOCATION
IfcAnnotation/Building plot-30 EAST | Building plot-2 LOCATION
IfcAnnotation/Building plot-31 NORTH | Building plot-2 LOCATION
IfcAnnotation/Building plot-31 SOUTH | Building plot-2 LOCATION
IfcAnnotation/Building plot-31 WEST | Building plot-2 LOCATION
IfcAnnotation/Building plot-31 EAST | Building plot-2 LOCATION
IfcAnnotation/Building plot-9 WEST | Building plot-20 LOCATION
IfcAnnotation/Building plot-9 EAST | Building plot-20 LOCATION
IfcAnnotation/Building plot-14 NORTH | Building plot-20 LOCATION
IfcAnnotation/Building plot-14 SOUTH | Building plot-20 LOCATION
IfcAnnotation/Building plot-30 WEST | Building plot-20 LOCATION
IfcAnnotation/Building plot-30 EAST | Building plot-20 LOCATION
IfcAnnotation/Building plot-31 NORTH | Building plot-20 LOCATION
IfcAnnotation/Building plot-31 SOUTH | Building plot-20 LOCATION
IfcAnnotation/Building plot-31 WEST | Building plot-20 LOCATION
IfcAnnotation/Building plot-31 EAST | Building plot-20 LOCATION
IfcAnnotation/Building plot-9 WEST | Building plot-21 LOCATION
IfcAnnotation/Building plot-9 EAST | Building plot-21 LOCATION
IfcAnnotation/Building plot-14 NORTH | Building plot-21 LOCATION
IfcAnnotation/Building plot-14 SOUTH | Building plot-21 LOCATION
IfcAnnotation/Building plot-30 WEST | Building plot-21 LOCATION
IfcAnnotation/Building plot-30 EAST | Building plot-21 LOCATION
IfcAnnotation/Building plot-31 NORTH | Building plot-21 LOCATION
IfcAnnotation/Building plot-31 SOUTH | Building plot-21 LOCATION
IfcAnnotation/Building plot-31 WEST | Building plot-21 LOCATION
IfcAnnotation/Building plot-31 EAST | Building plot-21 LOCATION
IfcAnnotation/Building plot-9 WEST | Building plot-22 LOCATION
IfcAnnotation/Building plot-9 EAST | Building plot-22 LOCATION
IfcAnnotation/Building plot-14 NORTH | Building plot-22 LOCATION
IfcAnnotation/Building plot-14 SOUTH | Building plot-22 LOCATION
IfcAnnotation/Building plot-30 WEST | Building plot-22 LOCATION
IfcAnnotation/Building plot-30 EAST | Building plot-22 LOCATION
IfcAnnotation/Building plot-31 NORTH | Building plot-22 LOCATION
IfcAnnotation/Building plot-31 SOUTH | Building plot-22 LOCATION
IfcAnnotation/Building plot-31 WEST | Building plot-22 LOCATION
IfcAnnotation/Building plot-31 EAST | Building plot-22 LOCATION
IfcAnnotation/Building plot-9 WEST | Building plot-23 LOCATION
IfcAnnotation/Building plot-9 EAST | Building plot-23 LOCATION
IfcAnnotation/Building plot-14 NORTH | Building plot-23 LOCATION
IfcAnnotation/Building plot-14 SOUTH | Building plot-23 LOCATION
IfcAnnotation/Building plot-30 WEST | Building plot-23 LOCATION
IfcAnnotation/Building plot-30 EAST | Building plot-23 LOCATION
IfcAnnotation/Building plot-31 NORTH | Building plot-23 LOCATION
IfcAnnotation/Building plot-31 SOUTH | Building plot-23 LOCATION
IfcAnnotation/Building plot-31 WEST | Building plot-23 LOCATION
IfcAnnotation/Building plot-31 EAST | Building plot-23 LOCATION
IfcAnnotation/Building plot-9 WEST | Building plot-24 LOCATION
IfcAnnotation/Building plot-9 EAST | Building plot-24 LOCATION
IfcAnnotation/Building plot-14 NORTH | Building plot-24 LOCATION
IfcAnnotation/Building plot-14 SOUTH | Building plot-24 LOCATION
IfcAnnotation/Building plot-30 WEST | Building plot-24 LOCATION
IfcAnnotation/Building plot-30 EAST | Building plot-24 LOCATION
IfcAnnotation/Building plot-31 NORTH | Building plot-24 LOCATION
IfcAnnotation/Building plot-31 SOUTH | Building plot-24 LOCATION
IfcAnnotation/Building plot-31 WEST | Building plot-24 LOCATION
IfcAnnotation/Building plot-31 EAST | Building plot-24 LOCATION
IfcAnnotation/Building plot-9 WEST | Building plot-25 LOCATION
IfcAnnotation/Building plot-9 EAST | Building plot-25 LOCATION
IfcAnnotation/Building plot-14 NORTH | Building plot-25 LOCATION
IfcAnnotation/Building plot-14 SOUTH | Building plot-25 LOCATION
IfcAnnotation/Building plot-30 WEST | Building plot-25 LOCATION
IfcAnnotation/Building plot-30 EAST | Building plot-25 LOCATION
IfcAnnotation/Building plot-31 NORTH | Building plot-25 LOCATION
IfcAnnotation/Building plot-31 SOUTH | Building plot-25 LOCATION
IfcAnnotation/Building plot-31 WEST | Building plot-25 LOCATION
IfcAnnotation/Building plot-31 EAST | Building plot-25 LOCATION
IfcAnnotation/Building plot-9 WEST | Building plot-26 LOCATION
IfcAnnotation/Building plot-9 EAST | Building plot-26 LOCATION
IfcAnnotation/Building plot-14 NORTH | Building plot-26 LOCATION
IfcAnnotation/Building plot-14 SOUTH | Building plot-26 LOCATION
IfcAnnotation/Building plot-30 WEST | Building plot-26 LOCATION
IfcAnnotation/Building plot-30 EAST | Building plot-26 LOCATION
IfcAnnotation/Building plot-31 NORTH | Building plot-26 LOCATION
IfcAnnotation/Building plot-31 SOUTH | Building plot-26 LOCATION
IfcAnnotation/Building plot-31 WEST | Building plot-26 LOCATION
IfcAnnotation/Building plot-31 EAST | Building plot-26 LOCATION
IfcAnnotation/Building plot-9 WEST | Building plot-27 LOCATION
IfcAnnotation/Building plot-9 EAST | Building plot-27 LOCATION
IfcAnnotation/Building plot-14 NORTH | Building plot-27 LOCATION
IfcAnnotation/Building plot-14 SOUTH | Building plot-27 LOCATION
IfcAnnotation/Building plot-30 WEST | Building plot-27 LOCATION
IfcAnnotation/Building plot-30 EAST | Building plot-27 LOCATION
IfcAnnotation/Building plot-31 NORTH | Building plot-27 LOCATION
IfcAnnotation/Building plot-31 SOUTH | Building plot-27 LOCATION
IfcAnnotation/Building plot-31 WEST | Building plot-27 LOCATION
IfcAnnotation/Building plot-31 EAST | Building plot-27 LOCATION
IfcAnnotation/Building plot-9 WEST | Building plot-28 LOCATION
IfcAnnotation/Building plot-9 EAST | Building plot-28 LOCATION
IfcAnnotation/Building plot-14 NORTH | Building plot-28 LOCATION
IfcAnnotation/Building plot-14 SOUTH | Building plot-28 LOCATION
IfcAnnotation/Building plot-30 WEST | Building plot-28 LOCATION
IfcAnnotation/Building plot-30 EAST | Building plot-28 LOCATION
IfcAnnotation/Building plot-31 NORTH | Building plot-28 LOCATION
IfcAnnotation/Building plot-31 SOUTH | Building plot-28 LOCATION
IfcAnnotation/Building plot-31 WEST | Building plot-28 LOCATION
IfcAnnotation/Building plot-31 EAST | Building plot-28 LOCATION
IfcAnnotation/Building plot-9 WEST | Building plot-29 LOCATION
IfcAnnotation/Building plot-9 EAST | Building plot-29 LOCATION
IfcAnnotation/Building plot-14 NORTH | Building plot-29 LOCATION
IfcAnnotation/Building plot-14 SOUTH | Building plot-29 LOCATION
IfcAnnotation/Building plot-30 WEST | Building plot-29 LOCATION
IfcAnnotation/Building plot-30 EAST | Building plot-29 LOCATION
IfcAnnotation/Building plot-31 NORTH | Building plot-29 LOCATION
IfcAnnotation/Building plot-31 SOUTH | Building plot-29 LOCATION
IfcAnnotation/Building plot-31 WEST | Building plot-29 LOCATION
IfcAnnotation/Building plot-31 EAST | Building plot-29 LOCATION
IfcAnnotation/Building plot-9 WEST | Building plot-3 LOCATION
IfcAnnotation/Building plot-9 EAST | Building plot-3 LOCATION
IfcAnnotation/Building plot-14 NORTH | Building plot-3 LOCATION
IfcAnnotation/Building plot-14 SOUTH | Building plot-3 LOCATION
IfcAnnotation/Building plot-30 WEST | Building plot-3 LOCATION
IfcAnnotation/Building plot-30 EAST | Building plot-3 LOCATION
IfcAnnotation/Building plot-31 NORTH | Building plot-3 LOCATION
IfcAnnotation/Building plot-31 SOUTH | Building plot-3 LOCATION
IfcAnnotation/Building plot-31 WEST | Building plot-3 LOCATION
IfcAnnotation/Building plot-31 EAST | Building plot-3 LOCATION
IfcAnnotation/Building plot-9 WEST | Building plot-30 LOCATION
IfcAnnotation/Building plot-9 EAST | Building plot-30 LOCATION
IfcAnnotation/Building plot-14 NORTH | Building plot-30 LOCATION
IfcAnnotation/Building plot-14 SOUTH | Building plot-30 LOCATION
IfcAnnotation/Building plot-30 WEST | Building plot-30 LOCATION
IfcAnnotation/Building plot-30 EAST | Building plot-30 LOCATION
IfcAnnotation/Building plot-31 NORTH | Building plot-30 LOCATION
IfcAnnotation/Building plot-31 SOUTH | Building plot-30 LOCATION
IfcAnnotation/Building plot-31 WEST | Building plot-30 LOCATION
IfcAnnotation/Building plot-31 EAST | Building plot-30 LOCATION
IfcAnnotation/Building plot-9 WEST | Building plot-31 LOCATION
IfcAnnotation/Building plot-9 EAST | Building plot-31 LOCATION
IfcAnnotation/Building plot-14 NORTH | Building plot-31 LOCATION
IfcAnnotation/Building plot-14 SOUTH | Building plot-31 LOCATION
IfcAnnotation/Building plot-30 WEST | Building plot-31 LOCATION
IfcAnnotation/Building plot-30 EAST | Building plot-31 LOCATION
IfcAnnotation/Building plot-31 NORTH | Building plot-31 LOCATION
IfcAnnotation/Building plot-31 SOUTH | Building plot-31 LOCATION
IfcAnnotation/Building plot-31 WEST | Building plot-31 LOCATION
IfcAnnotation/Building plot-31 EAST | Building plot-31 LOCATION
IfcAnnotation/Building plot-9 WEST | Building plot-4 LOCATION
IfcAnnotation/Building plot-9 EAST | Building plot-4 LOCATION
IfcAnnotation/Building plot-14 NORTH | Building plot-4 LOCATION
IfcAnnotation/Building plot-14 SOUTH | Building plot-4 LOCATION
IfcAnnotation/Building plot-30 WEST | Building plot-4 LOCATION
IfcAnnotation/Building plot-30 EAST | Building plot-4 LOCATION
IfcAnnotation/Building plot-31 NORTH | Building plot-4 LOCATION
IfcAnnotation/Building plot-31 SOUTH | Building plot-4 LOCATION
IfcAnnotation/Building plot-31 WEST | Building plot-4 LOCATION
IfcAnnotation/Building plot-31 EAST | Building plot-4 LOCATION
IfcAnnotation/Building plot-9 WEST | Building plot-5 LOCATION
IfcAnnotation/Building plot-9 EAST | Building plot-5 LOCATION
IfcAnnotation/Building plot-14 NORTH | Building plot-5 LOCATION
IfcAnnotation/Building plot-14 SOUTH | Building plot-5 LOCATION
IfcAnnotation/Building plot-30 WEST | Building plot-5 LOCATION
IfcAnnotation/Building plot-30 EAST | Building plot-5 LOCATION
IfcAnnotation/Building plot-31 NORTH | Building plot-5 LOCATION
IfcAnnotation/Building plot-31 SOUTH | Building plot-5 LOCATION
IfcAnnotation/Building plot-31 WEST | Building plot-5 LOCATION
IfcAnnotation/Building plot-31 EAST | Building plot-5 LOCATION
IfcAnnotation/Building plot-9 WEST | Building plot-6 LOCATION
IfcAnnotation/Building plot-9 EAST | Building plot-6 LOCATION
IfcAnnotation/Building plot-14 NORTH | Building plot-6 LOCATION
IfcAnnotation/Building plot-14 SOUTH | Building plot-6 LOCATION
IfcAnnotation/Building plot-30 WEST | Building plot-6 LOCATION
IfcAnnotation/Building plot-30 EAST | Building plot-6 LOCATION
IfcAnnotation/Building plot-31 NORTH | Building plot-6 LOCATION
IfcAnnotation/Building plot-31 SOUTH | Building plot-6 LOCATION
IfcAnnotation/Building plot-31 WEST | Building plot-6 LOCATION
IfcAnnotation/Building plot-31 EAST | Building plot-6 LOCATION
IfcAnnotation/Building plot-9 WEST | Building plot-7 LOCATION
IfcAnnotation/Building plot-9 EAST | Building plot-7 LOCATION
IfcAnnotation/Building plot-14 NORTH | Building plot-7 LOCATION
IfcAnnotation/Building plot-14 SOUTH | Building plot-7 LOCATION
IfcAnnotation/Building plot-30 WEST | Building plot-7 LOCATION
IfcAnnotation/Building plot-30 EAST | Building plot-7 LOCATION
IfcAnnotation/Building plot-31 NORTH | Building plot-7 LOCATION
IfcAnnotation/Building plot-31 SOUTH | Building plot-7 LOCATION
IfcAnnotation/Building plot-31 WEST | Building plot-7 LOCATION
IfcAnnotation/Building plot-31 EAST | Building plot-7 LOCATION
IfcAnnotation/Building plot-9 WEST | Building plot-8 LOCATION
IfcAnnotation/Building plot-9 EAST | Building plot-8 LOCATION
IfcAnnotation/Building plot-14 NORTH | Building plot-8 LOCATION
IfcAnnotation/Building plot-14 SOUTH | Building plot-8 LOCATION
IfcAnnotation/Building plot-30 WEST | Building plot-8 LOCATION
IfcAnnotation/Building plot-30 EAST | Building plot-8 LOCATION
IfcAnnotation/Building plot-31 NORTH | Building plot-8 LOCATION
IfcAnnotation/Building plot-31 SOUTH | Building plot-8 LOCATION
IfcAnnotation/Building plot-31 WEST | Building plot-8 LOCATION
IfcAnnotation/Building plot-31 EAST | Building plot-8 LOCATION
IfcAnnotation/Building plot-9 WEST | Building plot-9 LOCATION
IfcAnnotation/Building plot-9 EAST | Building plot-9 LOCATION
IfcAnnotation/Building plot-14 NORTH | Building plot-9 LOCATION
IfcAnnotation/Building plot-14 SOUTH | Building plot-9 LOCATION
IfcAnnotation/Building plot-30 WEST | Building plot-9 LOCATION
IfcAnnotation/Building plot-30 EAST | Building plot-9 LOCATION
IfcAnnotation/Building plot-31 NORTH | Building plot-9 LOCATION
IfcAnnotation/Building plot-31 SOUTH | Building plot-9 LOCATION
IfcAnnotation/Building plot-31 WEST | Building plot-9 LOCATION
IfcAnnotation/Building plot-31 EAST | Building plot-9 LOCATION
IfcAnnotation/Building plot-0 NORTH | Building plot-0 LOCATION
IfcAnnotation/Building plot-0 SOUTH | Building plot-0 LOCATION
IfcAnnotation/Building plot-9 WEST | Building plot-0 LOCATION
IfcAnnotation/Building plot-9 EAST | Building plot-0 LOCATION
IfcAnnotation/Building plot-14 NORTH | Building plot-0 LOCATION
IfcAnnotation/Building plot-14 SOUTH | Building plot-0 LOCATION
IfcAnnotation/Building plot-31 NORTH | Building plot-0 LOCATION
IfcAnnotation/Building plot-31 SOUTH | Building plot-0 LOCATION
IfcAnnotation/Building plot-31 EAST | Building plot-0 LOCATION

# IfcAnnotation: TEXT (375)
EPset_Annotation - Classes: header
Name | Group
6 x TEXT | plot-0 0
3 x TEXT | plot-0 1
3 x TEXT | plot-0 2
6 x TEXT | plot-1 0
3 x TEXT | plot-1 1
3 x TEXT | plot-1 2
4 x TEXT | plot-2 0
3 x TEXT | plot-2 1
3 x TEXT | plot-2 2
4 x TEXT | plot-3 0
4 x TEXT | plot-3 1
4 x TEXT | plot-3 2
6 x TEXT | plot-4 0
3 x TEXT | plot-4 1
3 x TEXT | plot-4 2
6 x TEXT | plot-5 0
4 x TEXT | plot-5 1
3 x TEXT | plot-5 2
4 x TEXT | plot-6 0
4 x TEXT | plot-6 1
3 x TEXT | plot-6 2
4 x TEXT | plot-7 0
4 x TEXT | plot-7 1
3 x TEXT | plot-7 2
6 x TEXT | plot-8 0
4 x TEXT | plot-8 1
4 x TEXT | plot-8 2
4 x TEXT | plot-9 0
4 x TEXT | plot-9 1
4 x TEXT | plot-10 0
3 x TEXT | plot-10 1
2 x TEXT | plot-10 2
2 x TEXT | plot-10 3
7 x TEXT | plot-11 0
4 x TEXT | plot-11 1
4 x TEXT | plot-11 2
4 x TEXT | plot-12 0
3 x TEXT | plot-12 1
3 x TEXT | plot-12 2
4 x TEXT | plot-13 0
4 x TEXT | plot-13 1
3 x TEXT | plot-13 2
5 x TEXT | plot-14 0
3 x TEXT | plot-14 1
3 x TEXT | plot-14 2
2 x TEXT | plot-14 3
6 x TEXT | plot-15 0
4 x TEXT | plot-15 1
3 x TEXT | plot-15 2
4 x TEXT | plot-16 0
4 x TEXT | plot-16 1
3 x TEXT | plot-16 2
3 x TEXT | plot-16 3
4 x TEXT | plot-17 0
3 x TEXT | plot-17 1
3 x TEXT | plot-17 2
4 x TEXT | plot-18 0
3 x TEXT | plot-18 1
3 x TEXT | plot-18 2
3 x TEXT | plot-18 3
5 x TEXT | plot-19 0
4 x TEXT | plot-19 1
6 x TEXT | plot-20 0
4 x TEXT | plot-20 1
3 x TEXT | plot-20 2
6 x TEXT | plot-21 0
3 x TEXT | plot-21 1
3 x TEXT | plot-21 2
4 x TEXT | plot-22 0
3 x TEXT | plot-22 1
3 x TEXT | plot-22 2
6 x TEXT | plot-23 0
3 x TEXT | plot-23 1
3 x TEXT | plot-23 2
5 x TEXT | plot-24 0
3 x TEXT | plot-24 1
3 x TEXT | plot-24 2
5 x TEXT | plot-25 0
3 x TEXT | plot-25 1
4 x TEXT | plot-26 0
3 x TEXT | plot-26 1
4 x TEXT | plot-26 2
5 x TEXT | plot-27 0
3 x TEXT | plot-27 1
2 x TEXT | plot-27 2
6 x TEXT | plot-28 0
4 x TEXT | plot-28 1
4 x TEXT | plot-28 2
6 x TEXT | plot-29 0
4 x TEXT | plot-29 1
4 x TEXT | plot-29 2
6 x TEXT | plot-30 0
4 x TEXT | plot-30 1
4 x TEXT | plot-30 2
5 x TEXT | plot-31 0
4 x TEXT | plot-31 1
3 x TEXT | plot-31 2

# IfcDoor: door_inside (171)
Type - OperationType: SINGLE_SWING_LEFT
OverallHeight: 2.1 m; OverallWidth: 0.8 m
Name | In
circulation inside door | plot-0 0
2 x bedroom inside door | plot-0 0
toilet inside door | plot-0 0
kitchen inside door | plot-0 1
living inside door | plot-0 1
bedroom inside door | plot-0 2
circulation inside door | plot-1 0
bedroom inside door | plot-1 0
toilet inside door | plot-1 0
kitchen inside door | plot-1 1
living inside door | plot-1 1
bedroom inside door | plot-1 2
living inside door | plot-10 0
kitchen inside door | plot-10 0
toilet inside door | plot-10 1
bedroom inside door | plot-10 2
bedroom inside door | plot-10 3
bedroom inside door | plot-11 0
toilet inside door | plot-11 0
circulation inside door | plot-11 0
bedroom inside door | plot-11 1
living inside door | plot-11 1
bedroom inside door | plot-11 2
kitchen inside door | plot-12 0
living inside door | plot-12 0
bedroom inside door | plot-12 1
toilet inside door | plot-12 1
bedroom inside door | plot-12 2
living inside door | plot-13 0
kitchen inside door | plot-13 0
bedroom inside door | plot-13 1
toilet inside door | plot-13 1
2 x bedroom inside door | plot-13 2
living inside door | plot-14 0
toilet inside door | plot-14 1
bedroom inside door | plot-14 1
bedroom inside door | plot-14 2
2 x bedroom inside door | plot-15 1
toilet inside door | plot-15 2
bedroom inside door | plot-15 2
kitchen inside door | plot-16 0
living inside door | plot-16 0
2 x bedroom inside door | plot-16 1
bedroom inside door | plot-16 2
toilet inside door | plot-16 2
living inside door | plot-17 0
kitchen inside door | plot-17 0
bedroom inside door | plot-17 1
toilet inside door | plot-17 1
kitchen inside door | plot-18 0
living inside door | plot-18 0
toilet inside door | plot-18 1
bedroom inside door | plot-18 1
2 x bedroom inside door | plot-18 2
toilet inside door | plot-19 0
living inside door | plot-19 0
2 x bedroom inside door | plot-19 1
kitchen inside door | plot-2 0
living inside door | plot-2 0
2 x bedroom inside door | plot-2 1
toilet inside door | plot-2 2
living inside door | plot-20 0
toilet inside door | plot-20 0
2 x bedroom inside door | plot-20 1
bedroom inside door | plot-20 2
2 x bedroom inside door | plot-21 0
toilet inside door | plot-21 0
circulation inside door | plot-21 0
kitchen inside door | plot-21 1
living inside door | plot-21 1
bedroom inside door | plot-21 2
kitchen inside door | plot-22 0
living inside door | plot-22 0
toilet inside door | plot-22 1
bedroom inside door | plot-22 1
bedroom inside door | plot-22 2
living inside door | plot-23 0
bedroom inside door | plot-23 0
kitchen inside door | plot-23 1
living inside door | plot-23 1
kitchen living inside door | plot-23 1
toilet inside door | plot-23 2
bedroom inside door | plot-23 2
kitchen inside door | plot-24 1
living inside door | plot-24 1
bedroom inside door | plot-24 2
toilet inside door | plot-24 2
living inside door | plot-25 0
bedroom inside door | plot-25 1
toilet inside door | plot-25 1
toilet inside door | plot-26 0
2 x bedroom inside door | plot-26 1
bedroom inside door | plot-26 2
living inside door | plot-26 2
living inside door | plot-27 0
toilet inside door | plot-27 0
bedroom inside door | plot-27 1
bedroom inside door | plot-27 2
living inside door | plot-28 0
toilet inside door | plot-28 0
2 x bedroom inside door | plot-28 1
circulation inside door | plot-28 1
bedroom inside door | plot-28 2
toilet inside door | plot-28 2
kitchen living inside door | plot-29 0
kitchen inside door | plot-29 0
living inside door | plot-29 0
2 x bedroom inside door | plot-29 1
toilet inside door | plot-29 1
2 x bedroom inside door | plot-29 2
bedroom inside door | plot-3 0
toilet inside door | plot-3 1
living inside door | plot-3 1
bedroom inside door | plot-3 2
living inside door | plot-30 0
kitchen inside door | plot-30 0
kitchen living inside door | plot-30 0
toilet inside door | plot-30 1
2 x bedroom inside door | plot-30 1
toilet inside door | plot-30 2
living inside door | plot-31 0
bedroom inside door | plot-31 1
toilet inside door | plot-31 1
2 x bedroom inside door | plot-31 2
circulation inside door | plot-4 0
2 x bedroom inside door | plot-4 0
toilet inside door | plot-4 0
living inside door | plot-4 1
kitchen inside door | plot-4 1
bedroom inside door | plot-4 2
living inside door | plot-5 0
kitchen living inside door | plot-5 0
toilet inside door | plot-5 0
2 x bedroom inside door | plot-5 1
bedroom inside door | plot-5 2
bedroom inside door | plot-6 1
living inside door | plot-6 1
toilet inside door | plot-6 2
bedroom inside door | plot-6 2
kitchen inside door | plot-7 0
living inside door | plot-7 0
2 x bedroom inside door | plot-7 1
bedroom inside door | plot-7 2
toilet inside door | plot-7 2
living inside door | plot-8 0
bedroom inside door | plot-8 0
kitchen inside door | plot-8 0
toilet inside door | plot-8 1
2 x bedroom inside door | plot-8 1
bedroom inside door | plot-8 2
bedroom inside door | plot-9 1
toilet inside door | plot-9 1

# IfcDoor: door_inside_double (28)
Type - OperationType: SINGLE_SWING_LEFT
OverallHeight: 2.1 m; OverallWidth: 1.6 m
Name | In
kitchen living inside door | plot-0 1
kitchen living inside door | plot-1 1
kitchen living inside door | plot-10 0
kitchen living inside door | plot-11 1
kitchen living inside door | plot-12 0
kitchen living inside door | plot-13 0
kitchen living inside door | plot-14 0
kitchen living inside door | plot-15 0
kitchen living inside door | plot-16 0
kitchen living inside door | plot-17 0
kitchen living inside door | plot-18 0
kitchen living inside door | plot-19 0
kitchen living inside door | plot-2 0
kitchen living inside door | plot-20 0
kitchen living inside door | plot-21 1
kitchen living inside door | plot-22 0
kitchen living inside door | plot-24 1
kitchen living inside door | plot-25 0
kitchen living inside door | plot-26 2
kitchen living inside door | plot-27 0
kitchen living inside door | plot-28 0
kitchen living inside door | plot-3 1
kitchen living inside door | plot-31 0
kitchen living inside door | plot-4 1
kitchen living inside door | plot-6 1
kitchen living inside door | plot-7 0
kitchen living inside door | plot-8 0
kitchen living inside door | plot-9 0

# IfcDoor: door_panelled (80)
Type - OperationType: SINGLE_SWING_LEFT
OverallHeight: 2.08 m; OverallWidth: 0.91 m
Name | In
2 x bedroom outside door | plot-0 0
circulation outside door | plot-0 2
bedroom outside door | plot-0 2
bedroom outside door | plot-1 0
circulation outside door | plot-1 2
bedroom outside door | plot-1 2
circulation outside door | plot-10 1
circulation outside door | plot-11 0
bedroom outside door | plot-11 0
bedroom outside door | plot-11 2
circulation outside door | plot-11 2
bedroom outside door | plot-12 2
circulation outside door | plot-12 2
bedroom outside door | plot-13 1
kitchen outside door | plot-14 0
circulation outside door | plot-14 0
circulation outside door | plot-14 2
circulation outside door | plot-14 3
circulation outside door | plot-15 0
kitchen outside door | plot-15 0
kitchen sahn door | plot-15 0
bedroom outside door | plot-15 1
2 x bedroom outside door | plot-16 1
2 x circulation outside door | plot-16 3
circulation outside door | plot-17 2
circulation outside door | plot-18 3
bedroom outside door | plot-19 1
circulation sahn door | plot-2 0
circulation outside door | plot-2 2
kitchen outside door | plot-20 0
bedroom outside door | plot-20 1
circulation outside door | plot-20 2
2 x bedroom outside door | plot-21 0
circulation outside door | plot-21 2
bedroom outside door | plot-21 2
circulation outside door | plot-22 2
bedroom outside door | plot-22 2
2 x bedroom outside door | plot-23 0
circulation sahn door | plot-24 0
bedroom sahn door | plot-24 0
kitchen outside door | plot-25 0
circulation outside door | plot-26 0
circulation outside door | plot-27 1
bedroom outside door | plot-27 1
circulation outside door | plot-28 0
kitchen outside door | plot-28 0
bedroom outside door | plot-28 2
2 x kitchen outside door | plot-29 0
circulation outside door | plot-29 2
bedroom outside door | plot-29 2
circulation sahn door | plot-3 0
circulation sahn door | plot-3 2
circulation sahn door | plot-30 0
kitchen outside door | plot-30 0
circulation sahn door | plot-30 2
circulation outside door | plot-31 0
bedroom outside door | plot-31 1
2 x bedroom outside door | plot-4 0
circulation outside door | plot-4 2
bedroom outside door | plot-4 2
kitchen outside door | plot-5 0
bedroom outside door | plot-5 1
bedroom outside door | plot-5 2
circulation outside door | plot-5 2
circulation sahn door | plot-6 0
bedroom sahn door | plot-6 0
2 x bedroom outside door | plot-7 1
bedroom outside door | plot-8 0
bedroom outside door | plot-8 2
circulation outside door | plot-8 2
kitchen sahn door | plot-9 0
bedroom outside door | plot-9 1

# IfcDoor: door_panelled_double (11)
Type - OperationType: SINGLE_SWING_LEFT
OverallHeight: 2.08 m; OverallWidth: 1.8 m
Name | In
living outside door | plot-14 0
living sahn door | plot-15 0
living outside door | plot-20 0
living outside door | plot-23 0
living outside door | plot-25 0
living outside door | plot-29 0
living outside door | plot-30 0
living outside door | plot-31 0
living outside door | plot-5 0
living outside door | plot-8 0
living sahn door | plot-9 0

# IfcDoor: door_panelled_short, house entrance
In: plot-2 0
Type - OperationType: SINGLE_SWING_LEFT
OverallHeight: 2.08 m; OverallWidth: 0.91 m

# IfcDoor: door_panelled_tall (22)
Type - OperationType: SINGLE_SWING_LEFT
OverallHeight: 2.545 m; OverallWidth: 0.91 m
Name | In
house entrance | plot-0 0
house entrance | plot-10 0
house entrance | plot-12 0
house entrance | plot-13 0
house entrance | plot-15 0
house entrance | plot-16 0
house entrance | plot-17 0
house entrance | plot-18 0
house entrance | plot-21 0
house entrance | plot-22 0
house entrance | plot-23 0
house entrance | plot-24 0
house entrance | plot-27 0
house entrance | plot-28 0
house entrance | plot-3 0
house entrance | plot-30 0
house entrance | plot-4 0
house entrance | plot-5 0
house entrance | plot-6 0
house entrance | plot-7 0
house entrance | plot-8 0
house entrance | plot-9 0

# IfcDoor: door_panelled_tall_flat (5)
Type - OperationType: SINGLE_SWING_LEFT
OverallHeight: 2.545 m; OverallWidth: 0.91 m
Name | In
house entrance covered | plot-1 0
house entrance covered | plot-11 0
house entrance covered | plot-25 0
house entrance covered | plot-29 0
house entrance covered | plot-31 0

# IfcDoor: gate (13)
Type - OperationType: SINGLE_SWING_LEFT
OverallHeight: 1.81 m; OverallWidth: 1.41 m
Name | In
house entrance gate | plot-10 0
house entrance gate | plot-12 0
house entrance gate | plot-13 0
house entrance gate | plot-16 0
house entrance gate | plot-18 0
house entrance gate | plot-19 0
house entrance gate | plot-20 0
house entrance gate | plot-22 0
house entrance gate | plot-23 0
house entrance gate | plot-27 0
house entrance gate | plot-5 0
house entrance gate | plot-7 0
house entrance gate | plot-8 0

# IfcDoor: gate-small (6)
Type - OperationType: SINGLE_SWING_LEFT
OverallHeight: 1.81 m; OverallWidth: 1 m
Name | In
gate | plot-15 0
gate | plot-2 0
gate | plot-21 0
gate | plot-28 0
gate | plot-8 0
gate | plot-9 0

# IfcGeographicElement, Terrain
In: Tamar
PredefinedType: TERRAIN

# IfcRoof (32)
PredefinedType: FREEFORM
Name | In
Roof | plot-0 2
Roof | plot-1 2
Roof | plot-10 3
Roof | plot-11 2
Roof | plot-12 2
Roof | plot-13 2
Roof | plot-14 3
Roof | plot-15 2
Roof | plot-16 3
Roof | plot-17 2
Roof | plot-18 3
Roof | plot-19 1
Roof | plot-2 2
Roof | plot-20 2
Roof | plot-21 2
Roof | plot-22 2
Roof | plot-23 2
Roof | plot-24 2
Roof | plot-25 1
Roof | plot-26 2
Roof | plot-27 2
Roof | plot-28 2
Roof | plot-29 2
Roof | plot-3 2
Roof | plot-30 2
Roof | plot-31 2
Roof | plot-4 2
Roof | plot-5 2
Roof | plot-6 2
Roof | plot-7 2
Roof | plot-8 2
Roof | plot-9 1

# IfcRoof: eaves_0 (161)
Type - PredefinedType: FREEFORM
Name | In
4 x eaves_0 | plot-0 2
4 x eaves_0 | plot-1 2
3 x eaves_0 | plot-10 3
6 x eaves_0 | plot-11 2
4 x eaves_0 | plot-12 2
6 x eaves_0 | plot-13 2
4 x eaves_0 | plot-14 3
7 x eaves_0 | plot-15 2
4 x eaves_0 | plot-16 3
4 x eaves_0 | plot-17 2
3 x eaves_0 | plot-18 3
7 x eaves_0 | plot-19 1
4 x eaves_0 | plot-2 2
7 x eaves_0 | plot-20 2
4 x eaves_0 | plot-21 2
6 x eaves_0 | plot-22 2
7 x eaves_0 | plot-23 2
3 x eaves_0 | plot-24 2
3 x eaves_0 | plot-25 1
4 x eaves_0 | plot-26 2
4 x eaves_0 | plot-27 2
6 x eaves_0 | plot-28 2
8 x eaves_0 | plot-29 2
5 x eaves_0 | plot-3 2
7 x eaves_0 | plot-30 2
5 x eaves_0 | plot-31 2
4 x eaves_0 | plot-4 2
5 x eaves_0 | plot-5 2
4 x eaves_0 | plot-6 2
7 x eaves_0 | plot-7 2
7 x eaves_0 | plot-8 2
5 x eaves_0 | plot-9 1

# IfcRoof: eaves_1 (161)
Type - PredefinedType: FREEFORM
Name | In
4 x eaves_1 | plot-0 2
4 x eaves_1 | plot-1 2
3 x eaves_1 | plot-10 3
6 x eaves_1 | plot-11 2
4 x eaves_1 | plot-12 2
6 x eaves_1 | plot-13 2
4 x eaves_1 | plot-14 3
7 x eaves_1 | plot-15 2
4 x eaves_1 | plot-16 3
4 x eaves_1 | plot-17 2
3 x eaves_1 | plot-18 3
7 x eaves_1 | plot-19 1
4 x eaves_1 | plot-2 2
7 x eaves_1 | plot-20 2
4 x eaves_1 | plot-21 2
6 x eaves_1 | plot-22 2
7 x eaves_1 | plot-23 2
3 x eaves_1 | plot-24 2
3 x eaves_1 | plot-25 1
4 x eaves_1 | plot-26 2
4 x eaves_1 | plot-27 2
6 x eaves_1 | plot-28 2
8 x eaves_1 | plot-29 2
5 x eaves_1 | plot-3 2
7 x eaves_1 | plot-30 2
5 x eaves_1 | plot-31 2
4 x eaves_1 | plot-4 2
5 x eaves_1 | plot-5 2
4 x eaves_1 | plot-6 2
7 x eaves_1 | plot-7 2
7 x eaves_1 | plot-8 2
5 x eaves_1 | plot-9 1

# IfcSlab: Slab (448)
PredefinedType: FLOOR
Name | In
9 x My Slab | plot-0 0
4 x My Slab | plot-0 1
3 x My Slab | plot-0 2
8 x My Slab | plot-1 0
4 x My Slab | plot-1 1
3 x My Slab | plot-1 2
5 x My Slab | plot-10 0
2 x My Slab | plot-10 1
2 x My Slab | plot-10 2
3 x My Slab | plot-10 3
8 x My Slab | plot-11 0
6 x My Slab | plot-11 1
3 x My Slab | plot-11 2
5 x My Slab | plot-12 0
4 x My Slab | plot-12 1
3 x My Slab | plot-12 2
5 x My Slab | plot-13 0
4 x My Slab | plot-13 1
5 x My Slab | plot-13 2
6 x My Slab | plot-14 0
4 x My Slab | plot-14 1
2 x My Slab | plot-14 2
My Slab | plot-14 3
5 x My Slab | plot-15 0
4 x My Slab | plot-15 1
5 x My Slab | plot-15 2
5 x My Slab | plot-16 0
4 x My Slab | plot-16 1
4 x My Slab | plot-16 2
My Slab | plot-16 3
5 x My Slab | plot-17 0
4 x My Slab | plot-17 1
My Slab | plot-17 2
5 x My Slab | plot-18 0
4 x My Slab | plot-18 1
4 x My Slab | plot-18 2
My Slab | plot-18 3
7 x My Slab | plot-19 0
5 x My Slab | plot-19 1
5 x My Slab | plot-2 0
4 x My Slab | plot-2 1
3 x My Slab | plot-2 2
7 x My Slab | plot-20 0
4 x My Slab | plot-20 1
3 x My Slab | plot-20 2
9 x My Slab | plot-21 0
4 x My Slab | plot-21 1
3 x My Slab | plot-21 2
5 x My Slab | plot-22 0
4 x My Slab | plot-22 1
3 x My Slab | plot-22 2
5 x My Slab | plot-23 0
4 x My Slab | plot-23 1
5 x My Slab | plot-23 2
5 x My Slab | plot-24 0
4 x My Slab | plot-24 1
5 x My Slab | plot-24 2
6 x My Slab | plot-25 0
5 x My Slab | plot-25 1
4 x My Slab | plot-26 0
4 x My Slab | plot-26 1
7 x My Slab | plot-26 2
7 x My Slab | plot-27 0
2 x My Slab | plot-27 1
3 x My Slab | plot-27 2
7 x My Slab | plot-28 0
6 x My Slab | plot-28 1
5 x My Slab | plot-28 2
6 x My Slab | plot-29 0
6 x My Slab | plot-29 1
5 x My Slab | plot-29 2
4 x My Slab | plot-3 0
6 x My Slab | plot-3 1
3 x My Slab | plot-3 2
6 x My Slab | plot-30 0
6 x My Slab | plot-30 1
5 x My Slab | plot-30 2
6 x My Slab | plot-31 0
4 x My Slab | plot-31 1
5 x My Slab | plot-31 2
9 x My Slab | plot-4 0
4 x My Slab | plot-4 1
3 x My Slab | plot-4 2
7 x My Slab | plot-5 0
4 x My Slab | plot-5 1
3 x My Slab | plot-5 2
4 x My Slab | plot-6 0
6 x My Slab | plot-6 1
5 x My Slab | plot-6 2
5 x My Slab | plot-7 0
4 x My Slab | plot-7 1
5 x My Slab | plot-7 2
7 x My Slab | plot-8 0
6 x My Slab | plot-8 1
3 x My Slab | plot-8 2
5 x My Slab | plot-9 0
5 x My Slab | plot-9 1

# IfcWall: exterior_0.08_0.25 (528)
Type - PredefinedType: SOLIDWALL; Material: Masonry 0.33 m
Name | In
5 x exterior | plot-0 0
4 x exterior | plot-0 1
4 x exterior | plot-0 2
6 x exterior | plot-1 0
4 x exterior | plot-1 1
4 x exterior | plot-1 2
3 x exterior | plot-10 0
3 x exterior | plot-10 1
3 x exterior | plot-10 2
3 x exterior | plot-10 3
7 x exterior | plot-11 0
6 x exterior | plot-11 1
6 x exterior | plot-11 2
5 x exterior | plot-12 0
5 x exterior | plot-12 1
4 x exterior | plot-12 2
5 x exterior | plot-13 0
6 x exterior | plot-13 1
6 x exterior | plot-13 2
7 x exterior | plot-14 0
6 x exterior | plot-14 1
5 x exterior | plot-14 2
4 x exterior | plot-14 3
7 x exterior | plot-15 0
7 x exterior | plot-15 1
7 x exterior | plot-15 2
6 x exterior | plot-16 0
7 x exterior | plot-16 1
7 x exterior | plot-16 2
4 x exterior | plot-16 3
4 x exterior | plot-17 0
4 x exterior | plot-17 1
4 x exterior | plot-17 2
5 x exterior | plot-18 0
5 x exterior | plot-18 1
5 x exterior | plot-18 2
3 x exterior | plot-18 3
8 x exterior | plot-19 0
7 x exterior | plot-19 1
5 x exterior | plot-2 0
5 x exterior | plot-2 1
4 x exterior | plot-2 2
9 x exterior | plot-20 0
9 x exterior | plot-20 1
7 x exterior | plot-20 2
7 x exterior | plot-21 0
5 x exterior | plot-21 1
4 x exterior | plot-21 2
6 x exterior | plot-22 0
6 x exterior | plot-22 1
6 x exterior | plot-22 2
7 x exterior | plot-23 0
7 x exterior | plot-23 1
7 x exterior | plot-23 2
5 x exterior | plot-24 0
3 x exterior | plot-24 1
3 x exterior | plot-24 2
6 x exterior | plot-25 0
3 x exterior | plot-25 1
4 x exterior | plot-26 0
4 x exterior | plot-26 1
4 x exterior | plot-26 2
4 x exterior | plot-27 0
4 x exterior | plot-27 1
4 x exterior | plot-27 2
7 x exterior | plot-28 0
7 x exterior | plot-28 1
6 x exterior | plot-28 2
7 x exterior | plot-29 0
8 x exterior | plot-29 1
8 x exterior | plot-29 2
4 x exterior | plot-3 0
5 x exterior | plot-3 1
5 x exterior | plot-3 2
7 x exterior | plot-30 0
7 x exterior | plot-30 1
7 x exterior | plot-30 2
6 x exterior | plot-31 0
5 x exterior | plot-31 1
5 x exterior | plot-31 2
5 x exterior | plot-4 0
4 x exterior | plot-4 1
4 x exterior | plot-4 2
7 x exterior | plot-5 0
6 x exterior | plot-5 1
5 x exterior | plot-5 2
4 x exterior | plot-6 0
4 x exterior | plot-6 1
4 x exterior | plot-6 2
6 x exterior | plot-7 0
7 x exterior | plot-7 1
7 x exterior | plot-7 2
8 x exterior | plot-8 0
8 x exterior | plot-8 1
7 x exterior | plot-8 2
4 x exterior | plot-9 0
5 x exterior | plot-9 1

# IfcWall: fence_-0.15_0.25 (86)
Type - PredefinedType: SOLIDWALL; Material: Masonry 0.1 m
Name | In
3 x fence | plot-0 0
3 x fence | plot-1 0
2 x fence | plot-10 0
4 x fence | plot-11 0
2 x fence | plot-12 0
2 x fence | plot-13 0
3 x fence | plot-14 0
5 x fence | plot-15 0
2 x fence | plot-16 0
2 x fence | plot-17 0
2 x fence | plot-18 0
2 x fence | plot-2 0
3 x fence | plot-20 0
2 x fence | plot-21 0
2 x fence | plot-22 0
5 x fence | plot-23 0
3 x fence | plot-24 0
3 x fence | plot-25 0
3 x fence | plot-26 0
2 x fence | plot-27 0
3 x fence | plot-28 0
4 x fence | plot-29 0
2 x fence | plot-3 0
4 x fence | plot-30 0
3 x fence | plot-31 0
3 x fence | plot-4 0
3 x fence | plot-5 0
3 x fence | plot-6 0
2 x fence | plot-7 0
3 x fence | plot-8 0
fence | plot-9 0

# IfcWall: fence_0_0.25 (20)
Type - PredefinedType: SOLIDWALL; Material: Masonry 0.25 m
Name | In
fence | plot-10 0
fence | plot-12 0
fence | plot-13 0
fence | plot-15 0
fence | plot-16 0
fence | plot-17 0
fence | plot-18 0
fence | plot-19 0
fence | plot-2 0
fence | plot-20 0
fence | plot-21 0
fence | plot-22 0
fence | plot-23 0
fence | plot-27 0
fence | plot-28 0
fence | plot-5 0
fence | plot-7 0
2 x fence | plot-8 0
fence | plot-9 0

# IfcWall: interior_0.08_0.08 (264)
Type - PredefinedType: SOLIDWALL; Material: Masonry 0.16 m
Name | In
7 x interior | plot-0 0
3 x interior | plot-0 1
interior | plot-0 2
5 x interior | plot-1 0
3 x interior | plot-1 1
interior | plot-1 2
3 x interior | plot-10 0
interior | plot-10 1
interior | plot-10 2
interior | plot-10 3
5 x interior | plot-11 0
5 x interior | plot-11 1
interior | plot-11 2
3 x interior | plot-12 0
3 x interior | plot-12 1
interior | plot-12 2
3 x interior | plot-13 0
3 x interior | plot-13 1
3 x interior | plot-13 2
2 x interior | plot-14 0
2 x interior | plot-14 1
interior | plot-14 2
2 x interior | plot-15 0
3 x interior | plot-15 1
3 x interior | plot-15 2
3 x interior | plot-16 0
3 x interior | plot-16 1
3 x interior | plot-16 2
3 x interior | plot-17 0
3 x interior | plot-17 1
3 x interior | plot-18 0
3 x interior | plot-18 1
3 x interior | plot-18 2
3 x interior | plot-19 0
2 x interior | plot-19 1
3 x interior | plot-2 0
3 x interior | plot-2 1
interior | plot-2 2
4 x interior | plot-20 0
2 x interior | plot-20 1
interior | plot-20 2
7 x interior | plot-21 0
3 x interior | plot-21 1
interior | plot-21 2
3 x interior | plot-22 0
3 x interior | plot-22 1
interior | plot-22 2
3 x interior | plot-23 0
3 x interior | plot-23 1
3 x interior | plot-23 2
interior | plot-24 0
3 x interior | plot-24 1
3 x interior | plot-24 2
2 x interior | plot-25 0
3 x interior | plot-25 1
interior | plot-26 0
3 x interior | plot-26 1
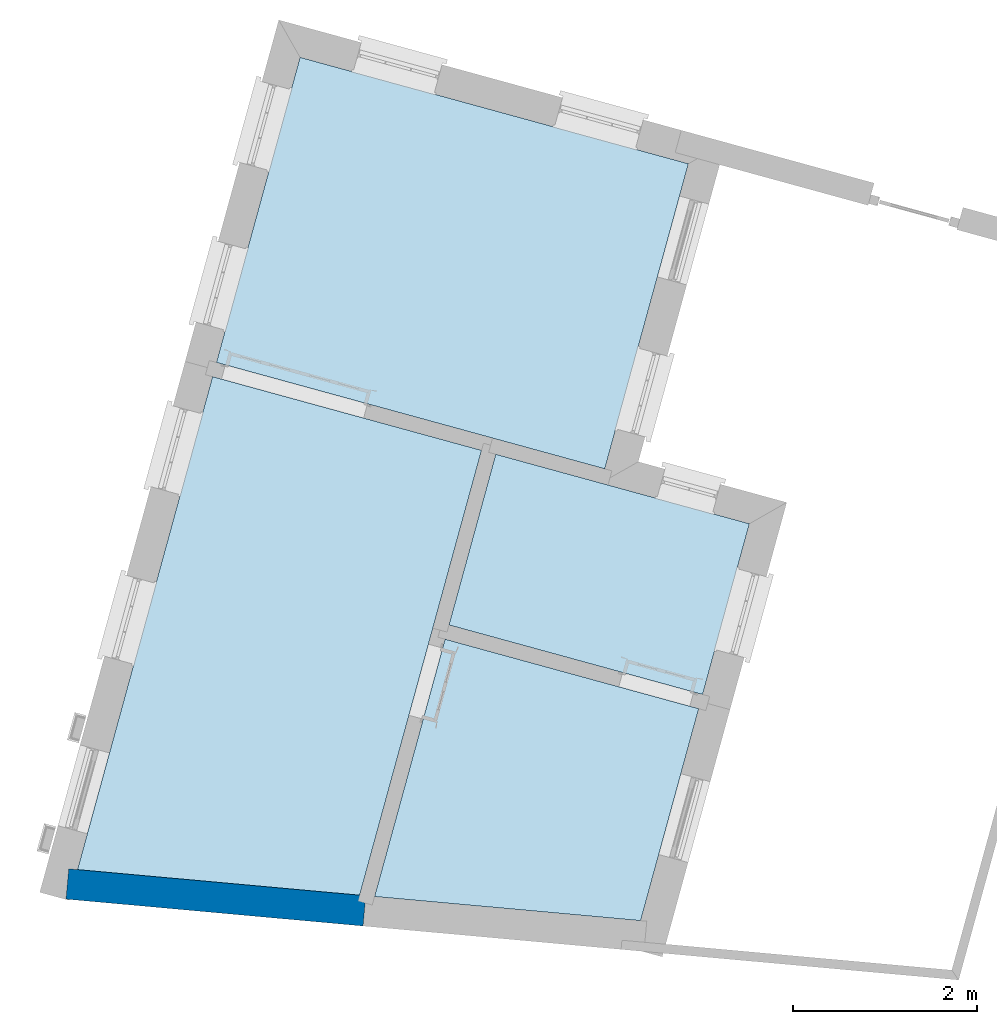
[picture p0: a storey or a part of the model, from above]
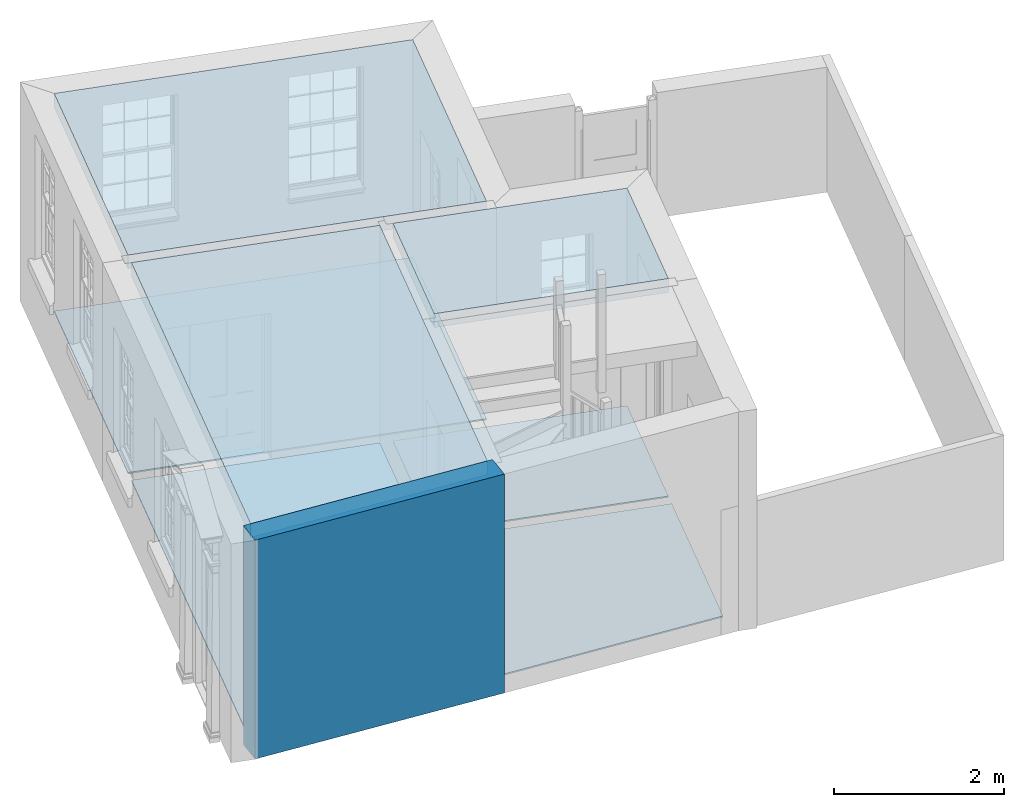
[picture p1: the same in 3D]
Properties of the parts of a building model (IFC4), part 4 of 4

# IfcWall: interior_0.08_0.08 (264)
Name | In
5 x interior | plot-26 2
5 x interior | plot-27 0
interior | plot-27 1
interior | plot-27 2
5 x interior | plot-28 0
5 x interior | plot-28 1
3 x interior | plot-28 2
3 x interior | plot-29 0
4 x interior | plot-29 1
2 x interior | plot-29 2
interior | plot-3 0
4 x interior | plot-3 1
interior | plot-3 2
3 x interior | plot-30 0
5 x interior | plot-30 1
3 x interior | plot-30 2
2 x interior | plot-31 0
3 x interior | plot-31 1
3 x interior | plot-31 2
7 x interior | plot-4 0
3 x interior | plot-4 1
interior | plot-4 2
4 x interior | plot-5 0
3 x interior | plot-5 1
interior | plot-5 2
interior | plot-6 0
5 x interior | plot-6 1
3 x interior | plot-6 2
3 x interior | plot-7 0
3 x interior | plot-7 1
3 x interior | plot-7 2
5 x interior | plot-8 0
5 x interior | plot-8 1
interior | plot-8 2
2 x interior | plot-9 0
3 x interior | plot-9 1

# IfcWall: parapet_0 (164)
Type - PredefinedType: PARAPET
Name | In
5 x parapet_0 | plot-0 2
5 x parapet_0 | plot-1 2
5 x parapet_0 | plot-10 1
7 x parapet_0 | plot-11 2
5 x parapet_0 | plot-12 2
4 x parapet_0 | plot-13 1
5 x parapet_0 | plot-14 2
5 x parapet_0 | plot-14 3
5 x parapet_0 | plot-15 1
4 x parapet_0 | plot-16 1
8 x parapet_0 | plot-16 3
7 x parapet_0 | plot-17 2
7 x parapet_0 | plot-18 3
5 x parapet_0 | plot-19 1
5 x parapet_0 | plot-2 2
5 x parapet_0 | plot-20 1
5 x parapet_0 | plot-20 2
5 x parapet_0 | plot-21 2
5 x parapet_0 | plot-22 2
4 x parapet_0 | plot-27 1
5 x parapet_0 | plot-28 2
5 x parapet_0 | plot-29 2
7 x parapet_0 | plot-3 2
5 x parapet_0 | plot-30 2
4 x parapet_0 | plot-31 1
5 x parapet_0 | plot-4 2
6 x parapet_0 | plot-5 1
6 x parapet_0 | plot-5 2
4 x parapet_0 | plot-7 1
6 x parapet_0 | plot-8 2
5 x parapet_0 | plot-9 1

# IfcWall: parapet_1 (164)
Type - PredefinedType: PARAPET
Name | In
5 x parapet_1 | plot-0 2
5 x parapet_1 | plot-1 2
5 x parapet_1 | plot-10 1
7 x parapet_1 | plot-11 2
5 x parapet_1 | plot-12 2
4 x parapet_1 | plot-13 1
5 x parapet_1 | plot-14 2
5 x parapet_1 | plot-14 3
5 x parapet_1 | plot-15 1
4 x parapet_1 | plot-16 1
8 x parapet_1 | plot-16 3
7 x parapet_1 | plot-17 2
7 x parapet_1 | plot-18 3
5 x parapet_1 | plot-19 1
5 x parapet_1 | plot-2 2
5 x parapet_1 | plot-20 1
5 x parapet_1 | plot-20 2
5 x parapet_1 | plot-21 2
5 x parapet_1 | plot-22 2
4 x parapet_1 | plot-27 1
5 x parapet_1 | plot-28 2
5 x parapet_1 | plot-29 2
7 x parapet_1 | plot-3 2
5 x parapet_1 | plot-30 2
4 x parapet_1 | plot-31 1
5 x parapet_1 | plot-4 2
6 x parapet_1 | plot-5 1
6 x parapet_1 | plot-5 2
4 x parapet_1 | plot-7 1
6 x parapet_1 | plot-8 2
5 x parapet_1 | plot-9 1

# IfcWall: parapet_2 (164)
Type - PredefinedType: PARAPET
Name | In
5 x parapet_2 | plot-0 2
5 x parapet_2 | plot-1 2
5 x parapet_2 | plot-10 1
7 x parapet_2 | plot-11 2
5 x parapet_2 | plot-12 2
4 x parapet_2 | plot-13 1
5 x parapet_2 | plot-14 2
5 x parapet_2 | plot-14 3
5 x parapet_2 | plot-15 1
4 x parapet_2 | plot-16 1
8 x parapet_2 | plot-16 3
7 x parapet_2 | plot-17 2
7 x parapet_2 | plot-18 3
5 x parapet_2 | plot-19 1
5 x parapet_2 | plot-2 2
5 x parapet_2 | plot-20 1
5 x parapet_2 | plot-20 2
5 x parapet_2 | plot-21 2
5 x parapet_2 | plot-22 2
4 x parapet_2 | plot-27 1
5 x parapet_2 | plot-28 2
5 x parapet_2 | plot-29 2
7 x parapet_2 | plot-3 2
5 x parapet_2 | plot-30 2
4 x parapet_2 | plot-31 1
5 x parapet_2 | plot-4 2
6 x parapet_2 | plot-5 1
6 x parapet_2 | plot-5 2
4 x parapet_2 | plot-7 1
6 x parapet_2 | plot-8 2
5 x parapet_2 | plot-9 1

# IfcWall: party_0.08_0.25 (232)
Type - PredefinedType: SOLIDWALL; Material: Masonry 0.33 m
Name | In
4 x party | plot-0 0
3 x party | plot-0 1
2 x party | plot-0 2
4 x party | plot-1 0
3 x party | plot-1 1
2 x party | plot-1 2
4 x party | plot-10 0
3 x party | plot-10 1
3 x party | plot-10 2
3 x party | plot-10 3
4 x party | plot-11 0
4 x party | plot-11 1
2 x party | plot-11 2
2 x party | plot-12 0
2 x party | plot-12 1
2 x party | plot-12 2
2 x party | plot-13 0
2 x party | plot-13 1
2 x party | plot-13 2
2 x party | plot-14 0
2 x party | plot-14 1
party | plot-14 2
2 x party | plot-15 0
party | plot-15 1
party | plot-15 2
party | plot-16 0
party | plot-16 1
party | plot-16 2
3 x party | plot-17 0
3 x party | plot-17 1
2 x party | plot-18 0
2 x party | plot-18 1
2 x party | plot-18 2
party | plot-18 3
4 x party | plot-19 0
3 x party | plot-19 1
2 x party | plot-2 0
2 x party | plot-2 1
2 x party | plot-2 2
2 x party | plot-20 0
party | plot-20 1
party | plot-20 2
2 x party | plot-21 0
2 x party | plot-21 1
2 x party | plot-21 2
party | plot-22 0
party | plot-22 1
2 x party | plot-23 0
2 x party | plot-23 1
2 x party | plot-23 2
4 x party | plot-24 0
4 x party | plot-24 1
4 x party | plot-24 2
4 x party | plot-25 0
4 x party | plot-25 1
3 x party | plot-26 0
3 x party | plot-26 1
4 x party | plot-26 2
4 x party | plot-27 0
3 x party | plot-27 1
3 x party | plot-27 2
2 x party | plot-28 0
2 x party | plot-28 1
2 x party | plot-28 2
3 x party | plot-29 0
3 x party | plot-29 1
2 x party | plot-29 2
4 x party | plot-3 0
5 x party | plot-3 1
2 x party | plot-3 2
3 x party | plot-30 0
3 x party | plot-30 1
2 x party | plot-30 2
4 x party | plot-31 0
3 x party | plot-31 1
3 x party | plot-31 2
4 x party | plot-4 0
3 x party | plot-4 1
2 x party | plot-4 2
4 x party | plot-5 0
2 x party | plot-5 1
party | plot-5 2
3 x party | plot-6 0
4 x party | plot-6 1
3 x party | plot-6 2
party | plot-7 0
party | plot-7 1
party | plot-7 2
party | plot-8 0
party | plot-8 1
party | plot-8 2
5 x party | plot-9 0
3 x party | plot-9 1

# IfcWindow: sash_big (144)
Type - PartitioningType: DOUBLE_PANEL_HORIZONTAL
OverallHeight: 1.82 m; OverallWidth: 0.91 m
Name | In
circulation outside window | plot-0 1
4 x living outside window | plot-0 1
2 x kitchen street window | plot-10 0
2 x kitchen outside window | plot-11 1
6 x living street window | plot-13 0
3 x bedroom outside window | plot-13 1
5 x toilet outside window | plot-13 1
2 x circulation outside window | plot-13 1
6 x bedroom outside window | plot-14 1
2 x circulation outside window | plot-14 1
2 x toilet outside window | plot-14 1
kitchen outside window | plot-15 0
kitchen sahn window | plot-15 0
living sahn window | plot-15 0
2 x living street window | plot-15 0
2 x circulation outside window | plot-15 1
3 x bedroom outside window | plot-15 1
2 x bedroom sahn window | plot-15 1
3 x kitchen street window | plot-16 0
9 x bedroom outside window | plot-18 2
2 x circulation outside window | plot-18 2
circulation outside window | plot-2 1
8 x bedroom outside window | plot-2 1
3 x kitchen outside window | plot-20 0
toilet outside window | plot-20 0
3 x toilet street window | plot-20 0
circulation street window | plot-20 0
2 x living street window | plot-20 0
2 x kitchen street window | plot-22 0
4 x toilet outside window | plot-23 2
3 x circulation outside window | plot-23 2
3 x bedroom outside window | plot-23 2
kitchen outside window | plot-25 0
toilet street window | plot-26 0
toilet outside window | plot-26 0
2 x circulation outside window | plot-26 0
kitchen outside window | plot-27 0
kitchen street window | plot-27 0
toilet outside window | plot-28 0
kitchen outside window | plot-28 0
4 x kitchen street window | plot-28 0
2 x living street window | plot-28 0
2 x circulation street window | plot-29 0
living street window | plot-29 0
2 x kitchen street window | plot-30 0
kitchen outside window | plot-30 0
2 x kitchen street window | plot-31 0
kitchen outside window | plot-31 0
living outside window | plot-31 0
living outside window | plot-5 0
circulation street window | plot-5 0
2 x toilet street window | plot-5 0
3 x bedroom outside window | plot-6 2
2 x toilet outside window | plot-6 2
2 x circulation outside window | plot-6 2
living street window | plot-7 0
4 x kitchen street window | plot-7 0
circulation street window | plot-7 0
3 x living outside window | plot-7 0
living outside window | plot-8 0
2 x living street window | plot-8 0
circulation street window | plot-8 0
circulation outside window | plot-8 0
2 x bedroom outside window | plot-8 0

# IfcWindow: sash_big_taller (180)
Type - PartitioningType: DOUBLE_PANEL_HORIZONTAL
OverallHeight: 2.23 m; OverallWidth: 0.91 m
Name | In
circulation street window | plot-0 0
toilet street window | plot-0 0
2 x bedroom outside window | plot-0 0
3 x bedroom outside window | plot-1 0
2 x toilet outside window | plot-1 0
3 x circulation street window | plot-1 0
2 x circulation outside window | plot-1 1
4 x living outside window | plot-1 1
2 x kitchen outside window | plot-1 1
living outside window | plot-10 0
2 x living street window | plot-10 0
2 x toilet outside window | plot-11 0
4 x circulation street window | plot-11 0
2 x bedroom outside window | plot-11 0
4 x living outside window | plot-11 1
4 x circulation outside window | plot-11 1
3 x bedroom outside window | plot-11 1
2 x kitchen street window | plot-12 0
4 x living street window | plot-12 0
2 x living outside window | plot-12 0
circulation outside window | plot-12 0
2 x circulation outside window | plot-14 0
circulation street window | plot-14 0
living street window | plot-14 0
kitchen street window | plot-14 0
3 x living outside window | plot-16 0
circulation outside window | plot-16 0
circulation street window | plot-16 0
3 x living street window | plot-16 0
kitchen street window | plot-17 0
circulation street window | plot-17 0
circulation outside window | plot-17 0
2 x living outside window | plot-17 0
toilet outside window | plot-17 1
3 x circulation outside window | plot-17 1
2 x bedroom outside window | plot-17 1
2 x kitchen street window | plot-18 0
5 x living street window | plot-18 0
2 x living outside window | plot-18 0
circulation outside window | plot-18 0
toilet street window | plot-19 0
2 x toilet outside window | plot-19 0
2 x kitchen outside window | plot-19 0
2 x kitchen street window | plot-19 0
2 x living street window | plot-19 0
circulation street window | plot-19 0
4 x circulation street window | plot-21 0
toilet street window | plot-21 0
toilet outside window | plot-21 0
bedroom outside window | plot-21 0
2 x living outside window | plot-22 0
circulation outside window | plot-22 0
circulation street window | plot-22 0
2 x living street window | plot-22 0
3 x bedroom outside window | plot-23 0
circulation outside window | plot-23 0
circulation street window | plot-23 0
2 x living street window | plot-23 0
4 x kitchen outside window | plot-23 1
3 x circulation outside window | plot-23 1
3 x living outside window | plot-23 1
bedroom outside window | plot-24 0
circulation outside window | plot-24 2
toilet outside window | plot-24 2
3 x bedroom outside window | plot-24 2
circulation street window | plot-25 0
3 x bedroom outside window | plot-25 1
toilet outside window | plot-25 1
circulation outside window | plot-25 1
3 x bedroom outside window | plot-26 1
circulation outside window | plot-26 1
toilet street window | plot-27 0
3 x bedroom sahn window | plot-3 0
2 x living sahn window | plot-30 0
2 x circulation street window | plot-4 0
toilet street window | plot-4 0
bedroom outside window | plot-4 0
2 x circulation outside window | plot-4 1
4 x living outside window | plot-4 1
kitchen outside window | plot-4 1
4 x bedroom outside window | plot-5 1
2 x circulation outside window | plot-5 1
circulation street window | plot-6 0
2 x bedroom sahn window | plot-6 0
kitchen outside window | plot-6 1
2 x bedroom outside window | plot-6 1
2 x circulation outside window | plot-6 1
2 x living outside window | plot-6 1
2 x living street window | plot-9 0
toilet sahn window | plot-9 1
2 x toilet outside window | plot-9 1
circulation outside window | plot-9 1

# IfcWindow: sash_narrow (4)
Type - PartitioningType: DOUBLE_PANEL_HORIZONTAL
OverallHeight: 1.82 m; OverallWidth: 0.625 m
Name | In
circulation outside window | plot-13 0
toilet outside window | plot-28 0
circulation outside window | plot-7 0
kitchen sahn window | plot-9 0

# IfcWindow: sash_narrow_shorter (5)
Type - PartitioningType: DOUBLE_PANEL_HORIZONTAL
OverallHeight: 1.445 m; OverallWidth: 0.625 m
Name | In
circulation sahn window | plot-2 0
circulation outside window | plot-27 1
circulation outside window | plot-28 1
bedroom outside window | plot-4 2
bedroom outside window | plot-5 2

# IfcWindow: sash_shorter (342)
Type - PartitioningType: DOUBLE_PANEL_HORIZONTAL
OverallHeight: 1.445 m; OverallWidth: 0.91 m
Name | In
kitchen outside window | plot-0 1
circulation outside window | plot-0 2
2 x bedroom outside window | plot-0 2
2 x circulation outside window | plot-1 2
3 x bedroom outside window | plot-1 2
3 x toilet outside window | plot-10 1
circulation outside window | plot-10 2
3 x bedroom outside window | plot-10 2
circulation outside window | plot-10 3
3 x bedroom outside window | plot-10 3
4 x circulation outside window | plot-11 2
4 x bedroom outside window | plot-11 2
2 x toilet outside window | plot-12 1
6 x bedroom outside window | plot-12 1
2 x circulation outside window | plot-12 1
2 x bedroom outside window | plot-12 2
2 x circulation outside window | plot-12 2
kitchen street window | plot-13 0
2 x kitchen outside window | plot-13 0
9 x bedroom outside window | plot-13 2
2 x circulation outside window | plot-13 2
6 x bedroom outside window | plot-14 2
3 x circulation outside window | plot-14 2
5 x circulation outside window | plot-14 3
circulation sahn window | plot-15 2
3 x toilet outside window | plot-15 2
3 x bedroom outside window | plot-15 2
circulation outside window | plot-15 2
8 x bedroom outside window | plot-16 1
3 x circulation outside window | plot-16 1
6 x bedroom outside window | plot-16 2
3 x circulation outside window | plot-16 2
4 x toilet outside window | plot-16 2
4 x circulation outside window | plot-16 3
5 x circulation outside window | plot-17 2
2 x toilet outside window | plot-18 1
7 x bedroom outside window | plot-18 1
2 x circulation outside window | plot-18 1
4 x circulation outside window | plot-18 3
6 x bedroom outside window | plot-19 1
circulation outside window | plot-19 1
2 x living sahn window | plot-2 0
4 x living street window | plot-2 0
kitchen street window | plot-2 0
circulation outside window | plot-2 2
2 x toilet outside window | plot-2 2
7 x bedroom outside window | plot-20 1
circulation outside window | plot-20 1
4 x bedroom outside window | plot-20 2
2 x circulation outside window | plot-20 2
2 x circulation outside window | plot-21 1
7 x living outside window | plot-21 1
2 x kitchen outside window | plot-21 1
2 x circulation outside window | plot-21 2
3 x bedroom outside window | plot-21 2
4 x bedroom outside window | plot-22 1
3 x circulation outside window | plot-22 1
2 x toilet outside window | plot-22 1
3 x circulation outside window | plot-22 2
2 x bedroom outside window | plot-22 2
circulation outside window | plot-24 1
kitchen outside window | plot-24 1
3 x living outside window | plot-24 1
bedroom outside window | plot-26 2
circulation outside window | plot-26 2
living outside window | plot-26 2
kitchen outside window | plot-26 2
5 x bedroom outside window | plot-27 1
circulation outside window | plot-27 2
6 x bedroom outside window | plot-27 2
2 x circulation outside window | plot-28 1
9 x bedroom outside window | plot-28 1
circulation outside window | plot-28 2
2 x toilet outside window | plot-28 2
4 x bedroom outside window | plot-28 2
kitchen outside window | plot-29 0
5 x bedroom outside window | plot-29 1
4 x toilet outside window | plot-29 1
2 x circulation outside window | plot-29 1
7 x bedroom outside window | plot-29 2
2 x circulation outside window | plot-29 2
2 x toilet outside window | plot-3 1
living outside window | plot-3 1
kitchen outside window | plot-3 1
2 x circulation outside window | plot-3 1
2 x bedroom outside window | plot-3 2
circulation sahn window | plot-3 2
2 x circulation outside window | plot-3 2
toilet outside window | plot-30 1
circulation outside window | plot-30 1
6 x bedroom outside window | plot-30 1
2 x bedroom sahn window | plot-30 1
toilet sahn window | plot-30 1
2 x bedroom sahn window | plot-30 2
toilet sahn window | plot-30 2
toilet outside window | plot-30 2
circulation outside window | plot-30 2
2 x bedroom outside window | plot-30 2
3 x bedroom outside window | plot-31 1
2 x toilet outside window | plot-31 1
circulation outside window | plot-31 1
6 x bedroom outside window | plot-31 2
circulation outside window | plot-31 2
2 x circulation outside window | plot-4 2
bedroom outside window | plot-4 2
kitchen outside window | plot-5 0
2 x circulation outside window | plot-5 2
2 x bedroom outside window | plot-5 2
8 x bedroom outside window | plot-7 1
2 x circulation outside window | plot-7 1
5 x bedroom outside window | plot-7 2
5 x toilet outside window | plot-7 2
2 x circulation outside window | plot-7 2
3 x kitchen street window | plot-8 0
3 x toilet outside window | plot-8 1
7 x bedroom outside window | plot-8 1
3 x circulation outside window | plot-8 1
3 x bedroom outside window | plot-8 2
4 x circulation outside window | plot-8 2
